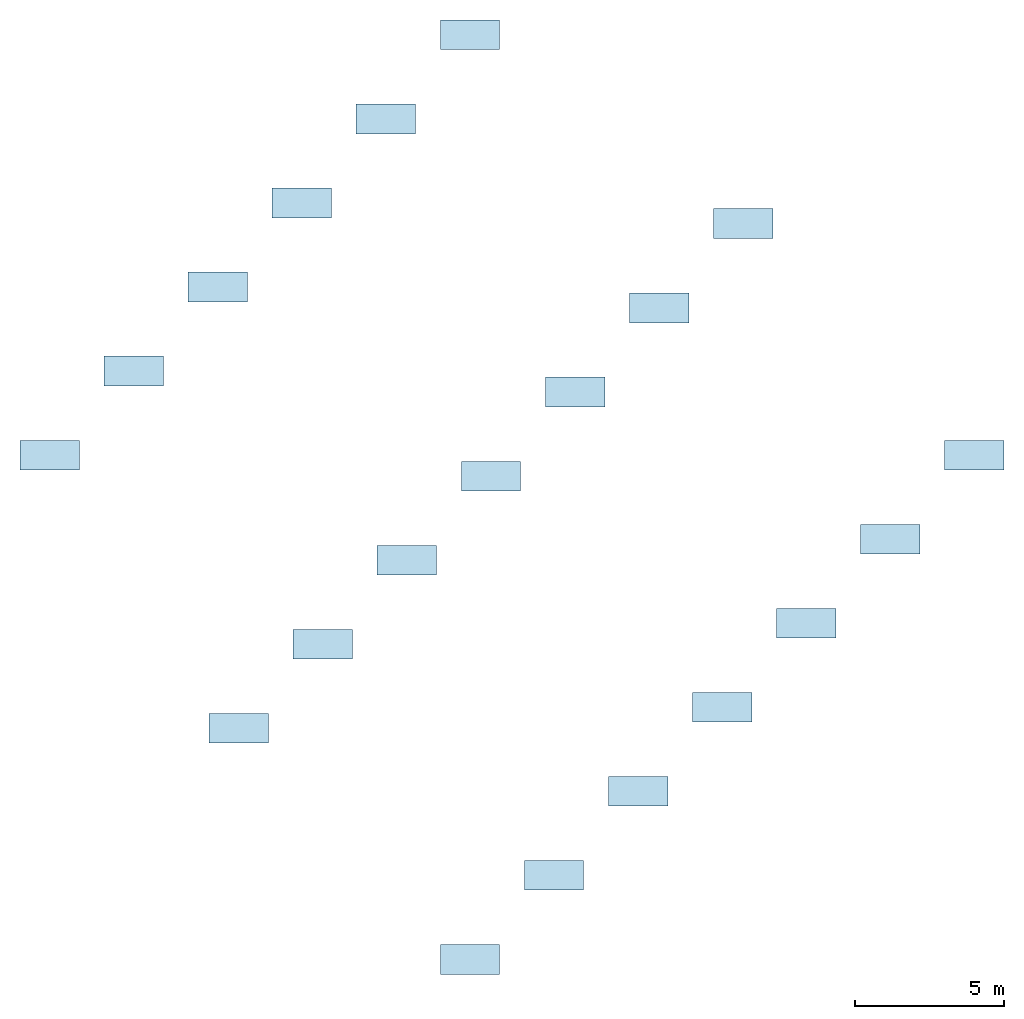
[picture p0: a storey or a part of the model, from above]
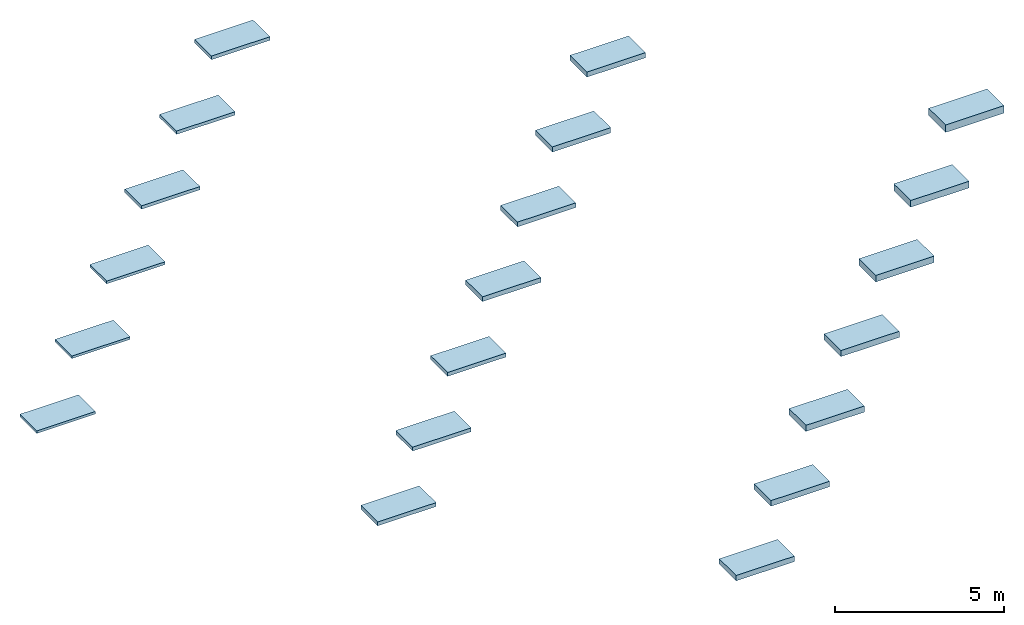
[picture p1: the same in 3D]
Properties of the parts of a building model (IFC2X3), part 1 of 3

# File
Description: ViewDefinition [CoordinationView_V2.0, QuantityTakeOffAddOnView]
Time: 2021-05-19T20:18:04
Written by: The EXPRESS Data Manager Version 5.02.0100.07 : 28 Aug 2013
Made in: 20190108_1515(x64) - Exporter 19.1.0.0 - Alternate UI 19.1.0.0
Comment: STEP Physical File produced by: The EXPRESS Data Manager Version 5.02.0100.07 : 28 Aug 2013 * Module: EDMstepFileFactory/EDMstandAlone * Creation date: Wed May 19 20:18:04 2021 * Host: lt-026 * Database: C:\Users\WF2BF~1.POE\AppData\Local\Temp\{3EFBC2A2-9184-4C69-A8A8-B9213D36A009}\ifc * Database version: 5507 * Database creation date: Wed May 19 20:18:03 2021 * Schema: IFC2X3 * Model: DataRepository.ifc * Model creation date: Wed May 19 20:18:03 2021 * Header model: DataRepository.ifc_HeaderModel * Header model creation date: Wed May 19 20:18:03 2021 * EDMuser: sdai-user * EDMgroup: sdai-group * License ID and type: 5605 : Permanent license. Expiry date: * EDMstepFileFactory options: 020000

# IfcSite, Default
RefLatitude: 42, 24, 53, 508911; RefLongitude: -71, -15, -29, -58837; RefElevation: 0 mm
Other - Category: Project Information

# IfcBuilding
Pset_BuildingCommon - NumberOfStoreys: 2
Pset_ProductRequirements - Category: Project Information; sets with these values: 2

# IfcBuildingStorey: Level:NL_00_niveau (2)
Pset_ProductRequirements - Category: Levels
Dimensions - Computation Height: 0 mm
Identity Data - Structural: no; Building Story: yes
Other - Category: Levels; Family: Level: NL_00_niveau; Family and Type: Level: NL_00_niveau; Type: Level: NL_00_niveau; Type Id: Level: NL_00_niveau
Constraints(Type) - Elevation Base: Project Base Point
Graphics(Type) - Color: 16711680; Line Pattern: NL_00_niveau; Line Weight: 1; Symbol: NLRS_00_LAB_niveau bovenkant_gen_cadix: 1.8mm; Symbol at End 1 Default: no; Symbol at End 2 Default: yes
Identity Data(Type) - Type Name: NL_00_niveau
Other(Type) - Category: Levels; Family Name: Level
Name | LongName = Pset_AirSideSystemInformation, Name = Pset_ProductRequirements, Name = Identity Data, Name | Elevation (mm) = Constraints, Elevation (mm)
Begane grond | Begane grond | 0
Lengte | Lengte | 2500

# IfcRoof: Basic Roof:NLRS_27_RO_Naturoll 035_100x580x7400mm, Basic Roof:NLRS_27_RO_Naturoll 035_100x580x7400mm:35001
In: Lengte
Classification: 27 Daken (Uniformat)
Pset_ElementShading - Roughness: 304.8 mm
Pset_ManufacturerTypeInformation - Manufacturer: Knauf Insulation B.V.
Pset_ProductRequirements - Category: Roofs
Pset_QuantityTakeOff - Reference: NLRS_27_RO_Naturoll 035_100x580x7400mm
Pset_RoofCommon - IsExternal: yes; Reference: NLRS_27_RO_Naturoll 035_100x580x7400mm; ProjectedArea: 2 m2; TotalArea: 2 m2
Constraints - Related to Mass: no; Room Bounding: yes; Base Level: Level: Lengte; Base Offset From Level: 0 mm; Cutoff Offset: 0 mm
Construction - Fascia Depth: 0 mm; Rafter Cut: Plumb Cut; Maximum Ridge Height: 2600 mm
Dimensions - Area: 2 m2; Thickness: 100 mm; Volume: 0.2 m3
Other - Category: Roofs; Family: Basic Roof: NLRS_27_RO_Naturoll 035_100x580x7400mm; Family and Type: Basic Roof: NLRS_27_RO_Naturoll 035_100x580x7400mm; Type: Basic Roof: NLRS_27_RO_Naturoll 035_100x580x7400mm; Type Id: Basic Roof: NLRS_27_RO_Naturoll 035_100x580x7400mm
Phasing - Phase Created: New Construction
Analytical Properties(Type) - Roughness: 1; Thermal mass: 0; Absorptance: 0.1; Heat Transfer Coefficient (U): 0.35; Thermal Resistance (R): 2.85714
Construction(Type) - Default Thickness: 100 mm
Graphics(Type) - Coarse Scale Fill Color: 0
Identity Data(Type) - Type Image: Raster image: Naturoll 035 .jpg (2); Assembly Code: 27; Assembly Description: Daken; Description: Naturoll 035 - 100mm; Manufacturer: Knauf Insulation B.V.; Model: Naturoll 035 is een onbeklede glaswoldeken met ECOSE® Technology; Type Name: NLRS_27_RO_Naturoll 035_100x580x7400mm; URL: www.knaufinsulation.nl
Other(Type) - Category: Roofs; Family Name: Basic Roof

# IfcRoof: Basic Roof:NLRS_27_RO_Naturoll 035_120x380x6200mm, Basic Roof:NLRS_27_RO_Naturoll 035_120x380x6200mm:35023
In: Lengte
Classification: 27 Daken (Uniformat)
Pset_ElementShading - Roughness: 304.8 mm
Pset_ManufacturerTypeInformation - Manufacturer: Knauf Insulation B.V.
Pset_ProductRequirements - Category: Roofs
Pset_QuantityTakeOff - Reference: NLRS_27_RO_Naturoll 035_120x380x6200mm
Pset_RoofCommon - IsExternal: yes; Reference: NLRS_27_RO_Naturoll 035_120x380x6200mm; ProjectedArea: 2 m2; TotalArea: 2 m2
Constraints - Related to Mass: no; Room Bounding: yes; Base Level: Level: Lengte; Base Offset From Level: 0 mm; Cutoff Offset: 0 mm
Construction - Fascia Depth: 0 mm; Rafter Cut: Plumb Cut; Maximum Ridge Height: 2620 mm
Dimensions - Area: 2 m2; Thickness: 120 mm; Volume: 0.24 m3
Other - Category: Roofs; Family: Basic Roof: NLRS_27_RO_Naturoll 035_120x380x6200mm; Family and Type: Basic Roof: NLRS_27_RO_Naturoll 035_120x380x6200mm; Type: Basic Roof: NLRS_27_RO_Naturoll 035_120x380x6200mm; Type Id: Basic Roof: NLRS_27_RO_Naturoll 035_120x380x6200mm
Phasing - Phase Created: New Construction
Analytical Properties(Type) - Roughness: 1; Thermal mass: 0; Absorptance: 0.1; Heat Transfer Coefficient (U): 0.291667; Thermal Resistance (R): 3.42857
Construction(Type) - Default Thickness: 120 mm
Graphics(Type) - Coarse Scale Fill Color: 0
Identity Data(Type) - Type Image: Raster image: Naturoll 035 .jpg (2); Assembly Code: 27; Assembly Description: Daken; Description: Naturoll 035 - 120mm; Manufacturer: Knauf Insulation B.V.; Model: Naturoll 035 is een onbeklede glaswoldeken met ECOSE® Technology; Type Name: NLRS_27_RO_Naturoll 035_120x380x6200mm; URL: www.knaufinsulation.nl
Other(Type) - Category: Roofs; Family Name: Basic Roof

# IfcRoof: Basic Roof:NLRS_27_RO_Naturoll 035_120x580x6200mm, Basic Roof:NLRS_27_RO_Naturoll 035_120x580x6200mm:35045
In: Lengte
Classification: 27 Daken (Uniformat)
Pset_ElementShading - Roughness: 304.8 mm
Pset_ManufacturerTypeInformation - Manufacturer: Knauf Insulation B.V.
Pset_ProductRequirements - Category: Roofs
Pset_QuantityTakeOff - Reference: NLRS_27_RO_Naturoll 035_120x580x6200mm
Pset_RoofCommon - IsExternal: yes; Reference: NLRS_27_RO_Naturoll 035_120x580x6200mm; ProjectedArea: 2 m2; TotalArea: 2 m2
Constraints - Related to Mass: no; Room Bounding: yes; Base Level: Level: Lengte; Base Offset From Level: 0 mm; Cutoff Offset: 0 mm
Construction - Fascia Depth: 0 mm; Rafter Cut: Plumb Cut; Maximum Ridge Height: 2620 mm
Dimensions - Area: 2 m2; Thickness: 120 mm; Volume: 0.24 m3
Other - Category: Roofs; Family: Basic Roof: NLRS_27_RO_Naturoll 035_120x580x6200mm; Family and Type: Basic Roof: NLRS_27_RO_Naturoll 035_120x580x6200mm; Type: Basic Roof: NLRS_27_RO_Naturoll 035_120x580x6200mm; Type Id: Basic Roof: NLRS_27_RO_Naturoll 035_120x580x6200mm
Phasing - Phase Created: New Construction
Analytical Properties(Type) - Roughness: 1; Thermal mass: 0; Absorptance: 0.1; Heat Transfer Coefficient (U): 0.291667; Thermal Resistance (R): 3.42857
Construction(Type) - Default Thickness: 120 mm
Graphics(Type) - Coarse Scale Fill Color: 0
Identity Data(Type) - Type Image: Raster image: Naturoll 035 .jpg (2); Assembly Code: 27; Assembly Description: Daken; Description: Naturoll 035 - 120mm; Manufacturer: Knauf Insulation B.V.; Model: Naturoll 035 is een onbeklede glaswoldeken met ECOSE® Technology; Type Name: NLRS_27_RO_Naturoll 035_120x580x6200mm; URL: www.knaufinsulation.nl
Other(Type) - Category: Roofs; Family Name: Basic Roof

# IfcRoof: Basic Roof:NLRS_27_RO_Naturoll 035_130x590x5500mm, Basic Roof:NLRS_27_RO_Naturoll 035_130x590x5500mm:35067
In: Lengte
Classification: 27 Daken (Uniformat)
Pset_ElementShading - Roughness: 304.8 mm
Pset_ManufacturerTypeInformation - Manufacturer: Knauf Insulation B.V.
Pset_ProductRequirements - Category: Roofs
Pset_QuantityTakeOff - Reference: NLRS_27_RO_Naturoll 035_130x590x5500mm
Pset_RoofCommon - IsExternal: yes; Reference: NLRS_27_RO_Naturoll 035_130x590x5500mm; ProjectedArea: 2 m2; TotalArea: 2 m2
Constraints - Related to Mass: no; Room Bounding: yes; Base Level: Level: Lengte; Base Offset From Level: 0 mm; Cutoff Offset: 0 mm
Construction - Fascia Depth: 0 mm; Rafter Cut: Plumb Cut; Maximum Ridge Height: 2630 mm
Dimensions - Area: 2 m2; Thickness: 130 mm; Volume: 0.26 m3
Other - Category: Roofs; Family: Basic Roof: NLRS_27_RO_Naturoll 035_130x590x5500mm; Family and Type: Basic Roof: NLRS_27_RO_Naturoll 035_130x590x5500mm; Type: Basic Roof: NLRS_27_RO_Naturoll 035_130x590x5500mm; Type Id: Basic Roof: NLRS_27_RO_Naturoll 035_130x590x5500mm
Phasing - Phase Created: New Construction
Analytical Properties(Type) - Roughness: 1; Thermal mass: 0; Absorptance: 0.1; Heat Transfer Coefficient (U): 0.269231; Thermal Resistance (R): 3.71429
Construction(Type) - Default Thickness: 130 mm
Graphics(Type) - Coarse Scale Fill Color: 0
Identity Data(Type) - Type Image: Raster image: Naturoll 035 .jpg (2); Assembly Code: 27; Assembly Description: Daken; Description: Naturoll 035 - 130mm; Manufacturer: Knauf Insulation B.V.; Model: Naturoll 035 is een onbeklede glaswoldeken met ECOSE® Technology; Type Name: NLRS_27_RO_Naturoll 035_130x590x5500mm; URL: www.knaufinsulation.nl
Other(Type) - Category: Roofs; Family Name: Basic Roof

# IfcRoof: Basic Roof:NLRS_27_RO_Naturoll 035_140x380x5300mm, Basic Roof:NLRS_27_RO_Naturoll 035_140x380x5300mm:35117
In: Lengte
Classification: 27 Daken (Uniformat)
Pset_ElementShading - Roughness: 304.8 mm
Pset_ManufacturerTypeInformation - Manufacturer: Knauf Insulation B.V.
Pset_ProductRequirements - Category: Roofs
Pset_QuantityTakeOff - Reference: NLRS_27_RO_Naturoll 035_140x380x5300mm
Pset_RoofCommon - IsExternal: yes; Reference: NLRS_27_RO_Naturoll 035_140x380x5300mm; ProjectedArea: 2 m2; TotalArea: 2 m2
Constraints - Related to Mass: no; Room Bounding: yes; Base Level: Level: Lengte; Base Offset From Level: 0 mm; Cutoff Offset: 0 mm
Construction - Fascia Depth: 0 mm; Rafter Cut: Plumb Cut; Maximum Ridge Height: 2640 mm
Dimensions - Area: 2 m2; Thickness: 140 mm; Volume: 0.28 m3
Other - Category: Roofs; Family: Basic Roof: NLRS_27_RO_Naturoll 035_140x380x5300mm; Family and Type: Basic Roof: NLRS_27_RO_Naturoll 035_140x380x5300mm; Type: Basic Roof: NLRS_27_RO_Naturoll 035_140x380x5300mm; Type Id: Basic Roof: NLRS_27_RO_Naturoll 035_140x380x5300mm
Phasing - Phase Created: New Construction
Analytical Properties(Type) - Roughness: 1; Thermal mass: 0; Thermal Resistance (R): 4; Absorptance: 0.1; Heat Transfer Coefficient (U): 0.25
Construction(Type) - Default Thickness: 140 mm
Graphics(Type) - Coarse Scale Fill Color: 0
Identity Data(Type) - Type Image: Raster image: Naturoll 035 .jpg (2); Assembly Code: 27; Assembly Description: Daken; Description: Naturoll 035 - 140mm; Manufacturer: Knauf Insulation B.V.; Model: Naturoll 035 is een onbeklede glaswoldeken met ECOSE® Technology; Type Name: NLRS_27_RO_Naturoll 035_140x380x5300mm; URL: www.knaufinsulation.nl
Other(Type) - Category: Roofs; Family Name: Basic Roof

# IfcRoof: Basic Roof:NLRS_27_RO_Naturoll 035_140x580x5300mm, Basic Roof:NLRS_27_RO_Naturoll 035_140x580x5300mm:35137
In: Lengte
Classification: 27 Daken (Uniformat)
Pset_ElementShading - Roughness: 304.8 mm
Pset_ManufacturerTypeInformation - Manufacturer: Knauf Insulation B.V.
Pset_ProductRequirements - Category: Roofs
Pset_QuantityTakeOff - Reference: NLRS_27_RO_Naturoll 035_140x580x5300mm
Pset_RoofCommon - IsExternal: yes; Reference: NLRS_27_RO_Naturoll 035_140x580x5300mm; ProjectedArea: 2 m2; TotalArea: 2 m2
Constraints - Related to Mass: no; Room Bounding: yes; Base Level: Level: Lengte; Base Offset From Level: 0 mm; Cutoff Offset: 0 mm
Construction - Fascia Depth: 0 mm; Rafter Cut: Plumb Cut; Maximum Ridge Height: 2640 mm
Dimensions - Area: 2 m2; Thickness: 140 mm; Volume: 0.28 m3
Other - Category: Roofs; Family: Basic Roof: NLRS_27_RO_Naturoll 035_140x580x5300mm; Family and Type: Basic Roof: NLRS_27_RO_Naturoll 035_140x580x5300mm; Type: Basic Roof: NLRS_27_RO_Naturoll 035_140x580x5300mm; Type Id: Basic Roof: NLRS_27_RO_Naturoll 035_140x580x5300mm
Phasing - Phase Created: New Construction
Analytical Properties(Type) - Roughness: 1; Thermal mass: 0; Thermal Resistance (R): 4; Absorptance: 0.1; Heat Transfer Coefficient (U): 0.25
Construction(Type) - Default Thickness: 140 mm
Graphics(Type) - Coarse Scale Fill Color: 0
Identity Data(Type) - Type Image: Raster image: Naturoll 035 .jpg (2); Assembly Code: 27; Assembly Description: Daken; Description: Naturoll 035 - 140mm; Manufacturer: Knauf Insulation B.V.; Model: Naturoll 035 is een onbeklede glaswoldeken met ECOSE® Technology; Type Name: NLRS_27_RO_Naturoll 035_140x580x5300mm; URL: www.knaufinsulation.nl
Other(Type) - Category: Roofs; Family Name: Basic Roof

# IfcRoof: Basic Roof:NLRS_27_RO_Naturoll 035_140x600x5300mm, Basic Roof:NLRS_27_RO_Naturoll 035_140x600x5300mm:35157
In: Lengte
Classification: 27 Daken (Uniformat)
Pset_ElementShading - Roughness: 304.8 mm
Pset_ManufacturerTypeInformation - Manufacturer: Knauf Insulation B.V.
Pset_ProductRequirements - Category: Roofs
Pset_QuantityTakeOff - Reference: NLRS_27_RO_Naturoll 035_140x600x5300mm
Pset_RoofCommon - IsExternal: yes; Reference: NLRS_27_RO_Naturoll 035_140x600x5300mm; ProjectedArea: 2 m2; TotalArea: 2 m2
Constraints - Related to Mass: no; Room Bounding: yes; Base Level: Level: Lengte; Base Offset From Level: 0 mm; Cutoff Offset: 0 mm
Construction - Fascia Depth: 0 mm; Rafter Cut: Plumb Cut; Maximum Ridge Height: 2640 mm
Dimensions - Area: 2 m2; Thickness: 140 mm; Volume: 0.28 m3
Other - Category: Roofs; Family: Basic Roof: NLRS_27_RO_Naturoll 035_140x600x5300mm; Family and Type: Basic Roof: NLRS_27_RO_Naturoll 035_140x600x5300mm; Type: Basic Roof: NLRS_27_RO_Naturoll 035_140x600x5300mm; Type Id: Basic Roof: NLRS_27_RO_Naturoll 035_140x600x5300mm
Phasing - Phase Created: New Construction
Analytical Properties(Type) - Roughness: 1; Thermal mass: 0; Thermal Resistance (R): 4; Absorptance: 0.1; Heat Transfer Coefficient (U): 0.25
Construction(Type) - Default Thickness: 140 mm
Graphics(Type) - Coarse Scale Fill Color: 0
Identity Data(Type) - Type Image: Raster image: Naturoll 035 .jpg (2); Assembly Code: 27; Assembly Description: Daken; Description: Naturoll 035 - 140mm; Manufacturer: Knauf Insulation B.V.; Model: Naturoll 035 is een onbeklede glaswoldeken met ECOSE® Technology; Type Name: NLRS_27_RO_Naturoll 035_140x600x5300mm; URL: www.knaufinsulation.nl
Other(Type) - Category: Roofs; Family Name: Basic Roof

# IfcRoof: Basic Roof:NLRS_27_RO_Naturoll 035_170x380x4350mm, Basic Roof:NLRS_27_RO_Naturoll 035_170x380x4350mm:35177
In: Lengte
Classification: 27 Daken (Uniformat)
Pset_ElementShading - Roughness: 304.8 mm
Pset_ManufacturerTypeInformation - Manufacturer: Knauf Insulation B.V.
Pset_ProductRequirements - Category: Roofs
Pset_QuantityTakeOff - Reference: NLRS_27_RO_Naturoll 035_170x380x4350mm
Pset_RoofCommon - IsExternal: yes; Reference: NLRS_27_RO_Naturoll 035_170x380x4350mm; ProjectedArea: 2 m2; TotalArea: 2 m2
Constraints - Related to Mass: no; Room Bounding: yes; Base Level: Level: Lengte; Base Offset From Level: 0 mm; Cutoff Offset: 0 mm
Construction - Fascia Depth: 0 mm; Rafter Cut: Plumb Cut; Maximum Ridge Height: 2670 mm
Dimensions - Area: 2 m2; Thickness: 170 mm; Volume: 0.34 m3
Other - Category: Roofs; Family: Basic Roof: NLRS_27_RO_Naturoll 035_170x380x4350mm; Family and Type: Basic Roof: NLRS_27_RO_Naturoll 035_170x380x4350mm; Type: Basic Roof: NLRS_27_RO_Naturoll 035_170x380x4350mm; Type Id: Basic Roof: NLRS_27_RO_Naturoll 035_170x380x4350mm
Phasing - Phase Created: New Construction
Analytical Properties(Type) - Roughness: 1; Thermal mass: 0; Absorptance: 0.1; Heat Transfer Coefficient (U): 0.205882; Thermal Resistance (R): 4.85714
Construction(Type) - Default Thickness: 170 mm
Graphics(Type) - Coarse Scale Fill Color: 0
Identity Data(Type) - Type Image: Raster image: Naturoll 035 .jpg (2); Assembly Code: 27; Assembly Description: Daken; Description: Naturoll 035 - 170mm; Manufacturer: Knauf Insulation B.V.; Model: Naturoll 035 is een onbeklede glaswoldeken met ECOSE® Technology; Type Name: NLRS_27_RO_Naturoll 035_170x380x4350mm; URL: www.knaufinsulation.nl
Other(Type) - Category: Roofs; Family Name: Basic Roof

# IfcRoof: Basic Roof:NLRS_27_RO_Naturoll 035_170x580x4350mm, Basic Roof:NLRS_27_RO_Naturoll 035_170x580x4350mm:35197
In: Lengte
Classification: 27 Daken (Uniformat)
Pset_ElementShading - Roughness: 304.8 mm
Pset_ManufacturerTypeInformation - Manufacturer: Knauf Insulation B.V.
Pset_ProductRequirements - Category: Roofs
Pset_QuantityTakeOff - Reference: NLRS_27_RO_Naturoll 035_170x580x4350mm
Pset_RoofCommon - IsExternal: yes; Reference: NLRS_27_RO_Naturoll 035_170x580x4350mm; ProjectedArea: 2 m2; TotalArea: 2 m2
Constraints - Related to Mass: no; Room Bounding: yes; Base Level: Level: Lengte; Base Offset From Level: 0 mm; Cutoff Offset: 0 mm
Construction - Fascia Depth: 0 mm; Rafter Cut: Plumb Cut; Maximum Ridge Height: 2670 mm
Dimensions - Area: 2 m2; Thickness: 170 mm; Volume: 0.34 m3
Other - Category: Roofs; Family: Basic Roof: NLRS_27_RO_Naturoll 035_170x580x4350mm; Family and Type: Basic Roof: NLRS_27_RO_Naturoll 035_170x580x4350mm; Type: Basic Roof: NLRS_27_RO_Naturoll 035_170x580x4350mm; Type Id: Basic Roof: NLRS_27_RO_Naturoll 035_170x580x4350mm
Phasing - Phase Created: New Construction
Analytical Properties(Type) - Roughness: 1; Thermal mass: 0; Absorptance: 0.1; Heat Transfer Coefficient (U): 0.205882; Thermal Resistance (R): 4.85714
Construction(Type) - Default Thickness: 170 mm
Graphics(Type) - Coarse Scale Fill Color: 0
Identity Data(Type) - Type Image: Raster image: Naturoll 035 .jpg (2); Assembly Code: 27; Assembly Description: Daken; Description: Naturoll 035 - 170mm; Manufacturer: Knauf Insulation B.V.; Model: Naturoll 035 is een onbeklede glaswoldeken met ECOSE® Technology; Type Name: NLRS_27_RO_Naturoll 035_170x580x4350mm; URL: www.knaufinsulation.nl
Other(Type) - Category: Roofs; Family Name: Basic Roof

# IfcRoof: Basic Roof:NLRS_27_RO_Naturoll 035_185x380x4000mm, Basic Roof:NLRS_27_RO_Naturoll 035_185x380x4000mm:35217
In: Lengte
Classification: 27 Daken (Uniformat)
Pset_ElementShading - Roughness: 304.8 mm
Pset_ManufacturerTypeInformation - Manufacturer: Knauf Insulation B.V.
Pset_ProductRequirements - Category: Roofs
Pset_QuantityTakeOff - Reference: NLRS_27_RO_Naturoll 035_185x380x4000mm
Pset_RoofCommon - IsExternal: yes; Reference: NLRS_27_RO_Naturoll 035_185x380x4000mm; ProjectedArea: 2 m2; TotalArea: 2 m2
Constraints - Related to Mass: no; Room Bounding: yes; Base Level: Level: Lengte; Base Offset From Level: 0 mm; Cutoff Offset: 0 mm
Construction - Fascia Depth: 0 mm; Rafter Cut: Plumb Cut; Maximum Ridge Height: 2685 mm
Dimensions - Area: 2 m2; Thickness: 185 mm; Volume: 0.37 m3
Other - Category: Roofs; Family: Basic Roof: NLRS_27_RO_Naturoll 035_185x380x4000mm; Family and Type: Basic Roof: NLRS_27_RO_Naturoll 035_185x380x4000mm; Type: Basic Roof: NLRS_27_RO_Naturoll 035_185x380x4000mm; Type Id: Basic Roof: NLRS_27_RO_Naturoll 035_185x380x4000mm
Phasing - Phase Created: New Construction
Analytical Properties(Type) - Roughness: 1; Thermal mass: 0; Absorptance: 0.1; Heat Transfer Coefficient (U): 0.189189; Thermal Resistance (R): 5.28571
Construction(Type) - Default Thickness: 185 mm
Graphics(Type) - Coarse Scale Fill Color: 0
Identity Data(Type) - Type Image: Raster image: Naturoll 035 .jpg (2); Assembly Code: 27; Assembly Description: Daken; Description: Naturoll 035 - 185mm; Manufacturer: Knauf Insulation B.V.; Model: Naturoll 035 is een onbeklede glaswoldeken met ECOSE® Technology; Type Name: NLRS_27_RO_Naturoll 035_185x380x4000mm; URL: www.knaufinsulation.nl
Other(Type) - Category: Roofs; Family Name: Basic Roof

# IfcRoof: Basic Roof:NLRS_27_RO_Naturoll 035_185x580x4000mm, Basic Roof:NLRS_27_RO_Naturoll 035_185x580x4000mm:37505
In: Lengte
Classification: 27 Daken (Uniformat)
Pset_ElementShading - Roughness: 304.8 mm
Pset_ManufacturerTypeInformation - Manufacturer: Knauf Insulation B.V.
Pset_ProductRequirements - Category: Roofs
Pset_QuantityTakeOff - Reference: NLRS_27_RO_Naturoll 035_185x580x4000mm
Pset_RoofCommon - IsExternal: yes; Reference: NLRS_27_RO_Naturoll 035_185x580x4000mm; ProjectedArea: 2 m2; TotalArea: 2 m2
Constraints - Related to Mass: no; Room Bounding: yes; Base Level: Level: Lengte; Base Offset From Level: 0 mm; Cutoff Offset: 0 mm
Construction - Fascia Depth: 0 mm; Rafter Cut: Plumb Cut; Maximum Ridge Height: 2685 mm
Dimensions - Area: 2 m2; Thickness: 185 mm; Volume: 0.37 m3
Other - Category: Roofs; Family: Basic Roof: NLRS_27_RO_Naturoll 035_185x580x4000mm; Family and Type: Basic Roof: NLRS_27_RO_Naturoll 035_185x580x4000mm; Type: Basic Roof: NLRS_27_RO_Naturoll 035_185x580x4000mm; Type Id: Basic Roof: NLRS_27_RO_Naturoll 035_185x580x4000mm
Phasing - Phase Created: New Construction
Analytical Properties(Type) - Roughness: 1; Thermal mass: 0; Absorptance: 0.1; Heat Transfer Coefficient (U): 0.189189; Thermal Resistance (R): 5.28571
Construction(Type) - Default Thickness: 185 mm
Graphics(Type) - Coarse Scale Fill Color: 0
Identity Data(Type) - Type Image: Raster image: Naturoll 035 .jpg (2); Assembly Code: 27; Assembly Description: Daken; Description: Naturoll 035 - 185mm; Manufacturer: Knauf Insulation B.V.; Model: Naturoll 035 is een onbeklede glaswoldeken met ECOSE® Technology; Type Name: NLRS_27_RO_Naturoll 035_185x580x4000mm; URL: www.knaufinsulation.nl
Other(Type) - Category: Roofs; Family Name: Basic Roof

# IfcRoof: Basic Roof:NLRS_27_RO_Naturoll 035_195x580x3800mm, Basic Roof:NLRS_27_RO_Naturoll 035_195x580x3800mm:35644
In: Lengte
Classification: 27 Daken (Uniformat)
Pset_ElementShading - Roughness: 304.8 mm
Pset_ManufacturerTypeInformation - Manufacturer: Knauf Insulation B.V.
Pset_ProductRequirements - Category: Roofs
Pset_QuantityTakeOff - Reference: NLRS_27_RO_Naturoll 035_195x580x3800mm
Pset_RoofCommon - IsExternal: yes; Reference: NLRS_27_RO_Naturoll 035_195x580x3800mm; ProjectedArea: 2 m2; TotalArea: 2 m2
Constraints - Related to Mass: no; Room Bounding: yes; Base Level: Level: Lengte; Base Offset From Level: 0 mm; Cutoff Offset: 0 mm
Construction - Fascia Depth: 0 mm; Rafter Cut: Plumb Cut; Maximum Ridge Height: 2695 mm
Dimensions - Area: 2 m2; Thickness: 195 mm; Volume: 0.39 m3
Other - Category: Roofs; Family: Basic Roof: NLRS_27_RO_Naturoll 035_195x580x3800mm; Family and Type: Basic Roof: NLRS_27_RO_Naturoll 035_195x580x3800mm; Type: Basic Roof: NLRS_27_RO_Naturoll 035_195x580x3800mm; Type Id: Basic Roof: NLRS_27_RO_Naturoll 035_195x580x3800mm
Phasing - Phase Created: New Construction
Analytical Properties(Type) - Roughness: 1; Thermal mass: 0; Absorptance: 0.1; Heat Transfer Coefficient (U): 0.179487; Thermal Resistance (R): 5.57143
Construction(Type) - Default Thickness: 195 mm
Graphics(Type) - Coarse Scale Fill Color: 0
Identity Data(Type) - Type Image: Raster image: Naturoll 035 .jpg (2); Assembly Code: 27; Assembly Description: Daken; Description: Naturoll 035 - 195mm; Manufacturer: Knauf Insulation B.V.; Model: Naturoll 035 is een onbeklede glaswoldeken met ECOSE® Technology; Type Name: NLRS_27_RO_Naturoll 035_195x580x3800mm; URL: www.knaufinsulation.nl
Other(Type) - Category: Roofs; Family Name: Basic Roof

# IfcRoof: Basic Roof:NLRS_27_RO_Naturoll 035_200x580x3700mm, Basic Roof:NLRS_27_RO_Naturoll 035_200x580x3700mm:35405
In: Lengte
Classification: 27 Daken (Uniformat)
Pset_ElementShading - Roughness: 304.8 mm
Pset_ManufacturerTypeInformation - Manufacturer: Knauf Insulation B.V.
Pset_ProductRequirements - Category: Roofs
Pset_QuantityTakeOff - Reference: NLRS_27_RO_Naturoll 035_200x580x3700mm
Pset_RoofCommon - IsExternal: yes; Reference: NLRS_27_RO_Naturoll 035_200x580x3700mm; ProjectedArea: 2 m2; TotalArea: 2 m2
Constraints - Related to Mass: no; Room Bounding: yes; Base Level: Level: Lengte; Base Offset From Level: 0 mm; Cutoff Offset: 0 mm
Construction - Fascia Depth: 0 mm; Rafter Cut: Plumb Cut; Maximum Ridge Height: 2700 mm
Dimensions - Area: 2 m2; Thickness: 200 mm; Volume: 0.4 m3
Other - Category: Roofs; Family: Basic Roof: NLRS_27_RO_Naturoll 035_200x580x3700mm; Family and Type: Basic Roof: NLRS_27_RO_Naturoll 035_200x580x3700mm; Type: Basic Roof: NLRS_27_RO_Naturoll 035_200x580x3700mm; Type Id: Basic Roof: NLRS_27_RO_Naturoll 035_200x580x3700mm
Phasing - Phase Created: New Construction
Analytical Properties(Type) - Roughness: 1; Thermal mass: 0; Absorptance: 0.1; Heat Transfer Coefficient (U): 0.175; Thermal Resistance (R): 5.71429
Construction(Type) - Default Thickness: 200 mm
Graphics(Type) - Coarse Scale Fill Color: 0
Identity Data(Type) - Type Image: Raster image: Naturoll 035 .jpg (2); Assembly Code: 27; Assembly Description: Daken; Description: Naturoll 035 - 200mm; Manufacturer: Knauf Insulation B.V.; Model: Naturoll 035 is een onbeklede glaswoldeken met ECOSE® Technology; Type Name: NLRS_27_RO_Naturoll 035_200x580x3700mm; URL: www.knaufinsulation.nl
Other(Type) - Category: Roofs; Family Name: Basic Roof

# IfcRoof: Basic Roof:NLRS_27_RO_Naturoll 035_220x380x3400mm, Basic Roof:NLRS_27_RO_Naturoll 035_220x380x3400mm:35424
In: Lengte
Classification: 27 Daken (Uniformat)
Pset_ElementShading - Roughness: 304.8 mm
Pset_ManufacturerTypeInformation - Manufacturer: Knauf Insulation B.V.
Pset_ProductRequirements - Category: Roofs
Pset_QuantityTakeOff - Reference: NLRS_27_RO_Naturoll 035_220x380x3400mm
Pset_RoofCommon - IsExternal: yes; Reference: NLRS_27_RO_Naturoll 035_220x380x3400mm; ProjectedArea: 2 m2; TotalArea: 2 m2
Constraints - Related to Mass: no; Room Bounding: yes; Base Level: Level: Lengte; Base Offset From Level: 0 mm; Cutoff Offset: 0 mm
Construction - Fascia Depth: 0 mm; Rafter Cut: Plumb Cut; Maximum Ridge Height: 2720 mm
Dimensions - Area: 2 m2; Thickness: 220 mm; Volume: 0.44 m3
Other - Category: Roofs; Family: Basic Roof: NLRS_27_RO_Naturoll 035_220x380x3400mm; Family and Type: Basic Roof: NLRS_27_RO_Naturoll 035_220x380x3400mm; Type: Basic Roof: NLRS_27_RO_Naturoll 035_220x380x3400mm; Type Id: Basic Roof: NLRS_27_RO_Naturoll 035_220x380x3400mm
Phasing - Phase Created: New Construction
Analytical Properties(Type) - Roughness: 1; Thermal mass: 0; Absorptance: 0.1; Heat Transfer Coefficient (U): 0.159091; Thermal Resistance (R): 6.28571
Construction(Type) - Default Thickness: 220 mm
Graphics(Type) - Coarse Scale Fill Color: 0
Identity Data(Type) - Type Image: Raster image: Naturoll 035 .jpg (2); Assembly Code: 27; Assembly Description: Daken; Description: Naturoll 035 - 220mm; Manufacturer: Knauf Insulation B.V.; Model: Naturoll 035 is een onbeklede glaswoldeken met ECOSE® Technology; Type Name: NLRS_27_RO_Naturoll 035_220x380x3400mm; URL: www.knaufinsulation.nl
Other(Type) - Category: Roofs; Family Name: Basic Roof

# IfcRoof: Basic Roof:NLRS_27_RO_Naturoll 035_220x580x3100mm, Basic Roof:NLRS_27_RO_Naturoll 035_220x580x3100mm:35443
In: Lengte
Classification: 27 Daken (Uniformat)
Pset_ElementShading - Roughness: 304.8 mm
Pset_ManufacturerTypeInformation - Manufacturer: Knauf Insulation B.V.
Pset_ProductRequirements - Category: Roofs
Pset_QuantityTakeOff - Reference: NLRS_27_RO_Naturoll 035_220x580x3100mm
Pset_RoofCommon - IsExternal: yes; Reference: NLRS_27_RO_Naturoll 035_220x580x3100mm; ProjectedArea: 2 m2; TotalArea: 2 m2
Constraints - Related to Mass: no; Room Bounding: yes; Base Level: Level: Lengte; Base Offset From Level: 0 mm; Cutoff Offset: 0 mm
Construction - Fascia Depth: 0 mm; Rafter Cut: Plumb Cut; Maximum Ridge Height: 2720 mm
Dimensions - Area: 2 m2; Thickness: 220 mm; Volume: 0.44 m3
Other - Category: Roofs; Family: Basic Roof: NLRS_27_RO_Naturoll 035_220x580x3100mm; Family and Type: Basic Roof: NLRS_27_RO_Naturoll 035_220x580x3100mm; Type: Basic Roof: NLRS_27_RO_Naturoll 035_220x580x3100mm; Type Id: Basic Roof: NLRS_27_RO_Naturoll 035_220x580x3100mm
Phasing - Phase Created: New Construction
Analytical Properties(Type) - Roughness: 1; Thermal mass: 0; Absorptance: 0.1; Heat Transfer Coefficient (U): 0.159091; Thermal Resistance (R): 6.28571
Construction(Type) - Default Thickness: 220 mm
Graphics(Type) - Coarse Scale Fill Color: 0
Identity Data(Type) - Type Image: Raster image: Naturoll 035 .jpg (2); Assembly Code: 27; Assembly Description: Daken; Description: Naturoll 035 - 220mm; Manufacturer: Knauf Insulation B.V.; Model: Naturoll 035 is een onbeklede glaswoldeken met ECOSE® Technology; Type Name: NLRS_27_RO_Naturoll 035_220x580x3100mm; URL: www.knaufinsulation.nl
Other(Type) - Category: Roofs; Family Name: Basic Roof

# IfcRoof: Basic Roof:NLRS_27_RO_Naturoll 035_235x580x3100mm, Basic Roof:NLRS_27_RO_Naturoll 035_235x580x3100mm:35462
In: Lengte
Classification: 27 Daken (Uniformat)
Pset_ElementShading - Roughness: 304.8 mm
Pset_ManufacturerTypeInformation - Manufacturer: Knauf Insulation B.V.
Pset_ProductRequirements - Category: Roofs
Pset_QuantityTakeOff - Reference: NLRS_27_RO_Naturoll 035_235x580x3100mm
Pset_RoofCommon - IsExternal: yes; Reference: NLRS_27_RO_Naturoll 035_235x580x3100mm; ProjectedArea: 2 m2; TotalArea: 2 m2
Constraints - Related to Mass: no; Room Bounding: yes; Base Level: Level: Lengte; Base Offset From Level: 0 mm; Cutoff Offset: 0 mm
Construction - Fascia Depth: 0 mm; Rafter Cut: Plumb Cut; Maximum Ridge Height: 2735 mm
Dimensions - Area: 2 m2; Thickness: 235 mm; Volume: 0.47 m3
Other - Category: Roofs; Family: Basic Roof: NLRS_27_RO_Naturoll 035_235x580x3100mm; Family and Type: Basic Roof: NLRS_27_RO_Naturoll 035_235x580x3100mm; Type: Basic Roof: NLRS_27_RO_Naturoll 035_235x580x3100mm; Type Id: Basic Roof: NLRS_27_RO_Naturoll 035_235x580x3100mm
Phasing - Phase Created: New Construction
Analytical Properties(Type) - Roughness: 1; Thermal mass: 0; Absorptance: 0.1; Heat Transfer Coefficient (U): 0.148936; Thermal Resistance (R): 6.71429
Construction(Type) - Default Thickness: 235 mm
Graphics(Type) - Coarse Scale Fill Color: 0
Identity Data(Type) - Type Image: Raster image: Naturoll 035 .jpg (2); Assembly Code: 27; Assembly Description: Daken; Description: Naturoll 035 - 235mm; Manufacturer: Knauf Insulation B.V.; Model: Naturoll 035 is een onbeklede glaswoldeken met ECOSE® Technology; Type Name: NLRS_27_RO_Naturoll 035_235x580x3100mm; URL: www.knaufinsulation.nl
Other(Type) - Category: Roofs; Family Name: Basic Roof

# IfcRoof: Basic Roof:NLRS_27_RO_Naturoll 035_240x580x3100mm, Basic Roof:NLRS_27_RO_Naturoll 035_240x580x3100mm:35481
In: Lengte
Classification: 27 Daken (Uniformat)
Pset_ElementShading - Roughness: 304.8 mm
Pset_ManufacturerTypeInformation - Manufacturer: Knauf Insulation B.V.
Pset_ProductRequirements - Category: Roofs
Pset_QuantityTakeOff - Reference: NLRS_27_RO_Naturoll 035_240x580x3100mm
Pset_RoofCommon - IsExternal: yes; Reference: NLRS_27_RO_Naturoll 035_240x580x3100mm; ProjectedArea: 2 m2; TotalArea: 2 m2
Constraints - Related to Mass: no; Room Bounding: yes; Base Level: Level: Lengte; Base Offset From Level: 0 mm; Cutoff Offset: 0 mm
Construction - Fascia Depth: 0 mm; Rafter Cut: Plumb Cut; Maximum Ridge Height: 2740 mm
Dimensions - Area: 2 m2; Thickness: 240 mm; Volume: 0.48 m3
Other - Category: Roofs; Family: Basic Roof: NLRS_27_RO_Naturoll 035_240x580x3100mm; Family and Type: Basic Roof: NLRS_27_RO_Naturoll 035_240x580x3100mm; Type: Basic Roof: NLRS_27_RO_Naturoll 035_240x580x3100mm; Type Id: Basic Roof: NLRS_27_RO_Naturoll 035_240x580x3100mm
Phasing - Phase Created: New Construction
Analytical Properties(Type) - Roughness: 1; Thermal mass: 0; Absorptance: 0.1; Heat Transfer Coefficient (U): 0.145833; Thermal Resistance (R): 6.85714
Construction(Type) - Default Thickness: 240 mm
Graphics(Type) - Coarse Scale Fill Color: 0
Identity Data(Type) - Type Image: Raster image: Naturoll 035 .jpg (2); Assembly Code: 27; Assembly Description: Daken; Description: Naturoll 035 - 240mm; Manufacturer: Knauf Insulation B.V.; Model: Naturoll 035 is een onbeklede glaswoldeken met ECOSE® Technology; Type Name: NLRS_27_RO_Naturoll 035_240x580x3100mm; URL: www.knaufinsulation.nl
Other(Type) - Category: Roofs; Family Name: Basic Roof

# IfcRoof: Basic Roof:NLRS_27_RO_Naturoll 035_270x590x2600mm, Basic Roof:NLRS_27_RO_Naturoll 035_270x590x2600mm:35500
In: Lengte
Classification: 27 Daken (Uniformat)
Pset_ElementShading - Roughness: 304.8 mm
Pset_ManufacturerTypeInformation - Manufacturer: Knauf Insulation B.V.
Pset_ProductRequirements - Category: Roofs
Pset_QuantityTakeOff - Reference: NLRS_27_RO_Naturoll 035_270x590x2600mm
Pset_RoofCommon - IsExternal: yes; Reference: NLRS_27_RO_Naturoll 035_270x590x2600mm; ProjectedArea: 2 m2; TotalArea: 2 m2
Constraints - Related to Mass: no; Room Bounding: yes; Base Level: Level: Lengte; Base Offset From Level: 0 mm; Cutoff Offset: 0 mm
Construction - Fascia Depth: 0 mm; Rafter Cut: Plumb Cut; Maximum Ridge Height: 2770 mm
Dimensions - Area: 2 m2; Thickness: 270 mm; Volume: 0.54 m3
Other - Category: Roofs; Family: Basic Roof: NLRS_27_RO_Naturoll 035_270x590x2600mm; Family and Type: Basic Roof: NLRS_27_RO_Naturoll 035_270x590x2600mm; Type: Basic Roof: NLRS_27_RO_Naturoll 035_270x590x2600mm; Type Id: Basic Roof: NLRS_27_RO_Naturoll 035_270x590x2600mm
Phasing - Phase Created: New Construction
Analytical Properties(Type) - Roughness: 1; Thermal mass: 0; Absorptance: 0.1; Heat Transfer Coefficient (U): 0.12963; Thermal Resistance (R): 7.71429
Construction(Type) - Default Thickness: 270 mm
Graphics(Type) - Coarse Scale Fill Color: 0
Identity Data(Type) - Type Image: Raster image: Naturoll 035 .jpg (2); Assembly Code: 27; Assembly Description: Daken; Description: Naturoll 035 - 270mm; Manufacturer: Knauf Insulation B.V.; Model: Naturoll 035 is een onbeklede glaswoldeken met ECOSE® Technology; Type Name: NLRS_27_RO_Naturoll 035_270x590x2600mm; URL: www.knaufinsulation.nl
Other(Type) - Category: Roofs; Family Name: Basic Roof

# IfcRoof: Basic Roof:NLRS_27_RO_Naturoll 035_90x380x7600mm, Basic Roof:NLRS_27_RO_Naturoll 035_90x380x7600mm:34727
In: Lengte
Classification: 27 Daken (Uniformat)
Pset_ElementShading - Roughness: 304.8 mm
Pset_ManufacturerTypeInformation - Manufacturer: Knauf Insulation B.V.
Pset_ProductRequirements - Category: Roofs
Pset_QuantityTakeOff - Reference: NLRS_27_RO_Naturoll 035_90x380x7600mm
Pset_RoofCommon - IsExternal: yes; Reference: NLRS_27_RO_Naturoll 035_90x380x7600mm; ProjectedArea: 2 m2; TotalArea: 2 m2
Constraints - Related to Mass: no; Room Bounding: yes; Base Level: Level: Lengte; Base Offset From Level: 0 mm; Cutoff Offset: 0 mm
Construction - Fascia Depth: 0 mm; Maximum Ridge Height: 2590 mm; Rafter Cut: Plumb Cut
Dimensions - Area: 2 m2; Thickness: 90 mm; Volume: 0.18 m3
Other - Category: Roofs; Family: Basic Roof: NLRS_27_RO_Naturoll 035_90x380x7600mm; Family and Type: Basic Roof: NLRS_27_RO_Naturoll 035_90x380x7600mm; Type: Basic Roof: NLRS_27_RO_Naturoll 035_90x380x7600mm; Type Id: Basic Roof: NLRS_27_RO_Naturoll 035_90x380x7600mm
Phasing - Phase Created: New Construction
Analytical Properties(Type) - Roughness: 1; Thermal mass: 0; Absorptance: 0.1; Heat Transfer Coefficient (U): 0.388889; Thermal Resistance (R): 2.57143
Construction(Type) - Default Thickness: 90 mm
Graphics(Type) - Coarse Scale Fill Color: 0
Identity Data(Type) - Type Image: Raster image: Naturoll 035 .jpg (2); Assembly Code: 27; Assembly Description: Daken; Description: Naturoll 035 - 90mm; Manufacturer: Knauf Insulation B.V.; Model: Naturoll 035 is een onbeklede glaswoldeken met ECOSE® Technology; Type Name: NLRS_27_RO_Naturoll 035_90x380x7600mm; URL: www.knaufinsulation.nl
Other(Type) - Category: Roofs; Family Name: Basic Roof

# IfcRoof: Basic Roof:NLRS_27_RO_Naturoll 035_90x580x7600mm, Basic Roof:NLRS_27_RO_Naturoll 035_90x580x7600mm:34921
In: Lengte
Classification: 27 Daken (Uniformat)
Pset_ElementShading - Roughness: 304.8 mm
Pset_ManufacturerTypeInformation - Manufacturer: Knauf Insulation B.V.
Pset_ProductRequirements - Category: Roofs
Pset_QuantityTakeOff - Reference: NLRS_27_RO_Naturoll 035_90x580x7600mm
Pset_RoofCommon - IsExternal: yes; Reference: NLRS_27_RO_Naturoll 035_90x580x7600mm; ProjectedArea: 2 m2; TotalArea: 2 m2
Constraints - Related to Mass: no; Room Bounding: yes; Base Level: Level: Lengte; Base Offset From Level: 0 mm; Cutoff Offset: 0 mm
Construction - Fascia Depth: 0 mm; Rafter Cut: Plumb Cut; Maximum Ridge Height: 2590 mm
Dimensions - Area: 2 m2; Thickness: 90 mm; Volume: 0.18 m3
Other - Category: Roofs; Family: Basic Roof: NLRS_27_RO_Naturoll 035_90x580x7600mm; Family and Type: Basic Roof: NLRS_27_RO_Naturoll 035_90x580x7600mm; Type: Basic Roof: NLRS_27_RO_Naturoll 035_90x580x7600mm; Type Id: Basic Roof: NLRS_27_RO_Naturoll 035_90x580x7600mm
Phasing - Phase Created: New Construction
Analytical Properties(Type) - Roughness: 1; Thermal mass: 0; Absorptance: 0.1; Heat Transfer Coefficient (U): 0.388889; Thermal Resistance (R): 2.57143
Construction(Type) - Default Thickness: 90 mm
Graphics(Type) - Coarse Scale Fill Color: 0
Identity Data(Type) - Type Image: Raster image: Naturoll 035 .jpg (2); Assembly Code: 27; Assembly Description: Daken; Description: Naturoll 035 - 90mm; Manufacturer: Knauf Insulation B.V.; Model: Naturoll 035 is een onbeklede glaswoldeken met ECOSE® Technology; Type Name: NLRS_27_RO_Naturoll 035_90x580x7600mm; URL: www.knaufinsulation.nl
Other(Type) - Category: Roofs; Family Name: Basic Roof

# IfcSlab: Basic Roof:NLRS_27_RO_Naturoll 035_100x580x7400mm, Basic Roof:NLRS_27_RO_Naturoll 035_100x580x7400mm:35001
In: Lengte
PredefinedType: ROOF; Classification: 27 Daken (Uniformat); Material: Knauf Insulation_Ecose® glaswol_naturoll 035 100 mm
Pset_ElementShading - Roughness: 304.8 mm
Pset_ManufacturerTypeInformation - Manufacturer: Knauf Insulation B.V.
Pset_ProductRequirements - Category: Roofs
Pset_QuantityTakeOff - Reference: NLRS_27_RO_Naturoll 035_100x580x7400mm
Pset_ReinforcementBarPitchOfSlab - Description: Naturoll 035 - 100mm; Reference: NLRS_27_RO_Naturoll 035_100x580x7400mm
Pset_SlabCommon - PitchAngle: 0 deg; IsExternal: yes; ThermalTransmittance: 0.35 kg/K/s3; Reference: NLRS_27_RO_Naturoll 035_100x580x7400mm
BaseQuantities - GrossArea: 0.185806 m2; NetArea: 4.6 m2; GrossVolume: 18.5806 m3; NetVolume: 0.2 m3; Perimeter: 6000 mm; Width: 100 mm

# IfcSlab: Basic Roof:NLRS_27_RO_Naturoll 035_120x380x6200mm, Basic Roof:NLRS_27_RO_Naturoll 035_120x380x6200mm:35023
In: Lengte
PredefinedType: ROOF; Classification: 27 Daken (Uniformat); Material: Knauf Insulation_Ecose® glaswol_naturoll 035 120 mm
Pset_ElementShading - Roughness: 304.8 mm
Pset_ManufacturerTypeInformation - Manufacturer: Knauf Insulation B.V.
Pset_ProductRequirements - Category: Roofs
Pset_QuantityTakeOff - Reference: NLRS_27_RO_Naturoll 035_120x380x6200mm
Pset_ReinforcementBarPitchOfSlab - Description: Naturoll 035 - 120mm; Reference: NLRS_27_RO_Naturoll 035_120x380x6200mm
Pset_SlabCommon - PitchAngle: 0 deg; IsExternal: yes; Reference: NLRS_27_RO_Naturoll 035_120x380x6200mm; ThermalTransmittance: 0.291667 kg/K/s3
BaseQuantities - GrossArea: 0.185806 m2; NetArea: 4.72 m2; GrossVolume: 22.2967 m3; NetVolume: 0.24 m3; Perimeter: 6000 mm; Width: 120 mm

# IfcSlab: Basic Roof:NLRS_27_RO_Naturoll 035_120x580x6200mm, Basic Roof:NLRS_27_RO_Naturoll 035_120x580x6200mm:35045
In: Lengte
PredefinedType: ROOF; Classification: 27 Daken (Uniformat); Material: Knauf Insulation_Ecose® glaswol_naturoll 035 120 mm
Pset_ElementShading - Roughness: 304.8 mm
Pset_ManufacturerTypeInformation - Manufacturer: Knauf Insulation B.V.
Pset_ProductRequirements - Category: Roofs
Pset_QuantityTakeOff - Reference: NLRS_27_RO_Naturoll 035_120x580x6200mm
Pset_ReinforcementBarPitchOfSlab - Description: Naturoll 035 - 120mm; Reference: NLRS_27_RO_Naturoll 035_120x580x6200mm
Pset_SlabCommon - PitchAngle: 0 deg; IsExternal: yes; Reference: NLRS_27_RO_Naturoll 035_120x580x6200mm; ThermalTransmittance: 0.291667 kg/K/s3
BaseQuantities - GrossArea: 0.185806 m2; NetArea: 4.72 m2; GrossVolume: 22.2967 m3; NetVolume: 0.24 m3; Perimeter: 6000 mm; Width: 120 mm

# IfcSlab: Basic Roof:NLRS_27_RO_Naturoll 035_130x590x5500mm, Basic Roof:NLRS_27_RO_Naturoll 035_130x590x5500mm:35067
In: Lengte
PredefinedType: ROOF; Classification: 27 Daken (Uniformat); Material: Knauf Insulation_Ecose® glaswol_naturoll 035 130 mm
Pset_ElementShading - Roughness: 304.8 mm
Pset_ManufacturerTypeInformation - Manufacturer: Knauf Insulation B.V.
Pset_ProductRequirements - Category: Roofs
Pset_QuantityTakeOff - Reference: NLRS_27_RO_Naturoll 035_130x590x5500mm
Pset_ReinforcementBarPitchOfSlab - Description: Naturoll 035 - 130mm; Reference: NLRS_27_RO_Naturoll 035_130x590x5500mm
Pset_SlabCommon - PitchAngle: 0 deg; IsExternal: yes; Reference: NLRS_27_RO_Naturoll 035_130x590x5500mm; ThermalTransmittance: 0.269231 kg/K/s3
BaseQuantities - GrossArea: 0.185806 m2; NetArea: 4.78 m2; GrossVolume: 24.1548 m3; NetVolume: 0.26 m3; Perimeter: 6000 mm; Width: 130 mm

# IfcSlab: Basic Roof:NLRS_27_RO_Naturoll 035_140x380x5300mm, Basic Roof:NLRS_27_RO_Naturoll 035_140x380x5300mm:35117
In: Lengte
PredefinedType: ROOF; Classification: 27 Daken (Uniformat); Material: Knauf Insulation_Ecose® glaswol_naturoll 035 140 mm
Pset_ElementShading - Roughness: 304.8 mm
Pset_ManufacturerTypeInformation - Manufacturer: Knauf Insulation B.V.
Pset_ProductRequirements - Category: Roofs
Pset_QuantityTakeOff - Reference: NLRS_27_RO_Naturoll 035_140x380x5300mm
Pset_ReinforcementBarPitchOfSlab - Description: Naturoll 035 - 140mm; Reference: NLRS_27_RO_Naturoll 035_140x380x5300mm
Pset_SlabCommon - PitchAngle: 0 deg; IsExternal: yes; ThermalTransmittance: 0.25 kg/K/s3; Reference: NLRS_27_RO_Naturoll 035_140x380x5300mm
BaseQuantities - GrossArea: 0.185806 m2; NetArea: 4.84 m2; GrossVolume: 26.0129 m3; NetVolume: 0.28 m3; Perimeter: 6000 mm; Width: 140 mm

# IfcSlab: Basic Roof:NLRS_27_RO_Naturoll 035_140x580x5300mm, Basic Roof:NLRS_27_RO_Naturoll 035_140x580x5300mm:35137
In: Lengte
PredefinedType: ROOF; Classification: 27 Daken (Uniformat); Material: Knauf Insulation_Ecose® glaswol_naturoll 035 140 mm
Pset_ElementShading - Roughness: 304.8 mm
Pset_ManufacturerTypeInformation - Manufacturer: Knauf Insulation B.V.
Pset_ProductRequirements - Category: Roofs
Pset_QuantityTakeOff - Reference: NLRS_27_RO_Naturoll 035_140x580x5300mm
Pset_ReinforcementBarPitchOfSlab - Description: Naturoll 035 - 140mm; Reference: NLRS_27_RO_Naturoll 035_140x580x5300mm
Pset_SlabCommon - PitchAngle: 0 deg; IsExternal: yes; ThermalTransmittance: 0.25 kg/K/s3; Reference: NLRS_27_RO_Naturoll 035_140x580x5300mm
BaseQuantities - GrossArea: 0.185806 m2; NetArea: 4.84 m2; GrossVolume: 26.0129 m3; NetVolume: 0.28 m3; Perimeter: 6000 mm; Width: 140 mm

# IfcSlab: Basic Roof:NLRS_27_RO_Naturoll 035_140x600x5300mm, Basic Roof:NLRS_27_RO_Naturoll 035_140x600x5300mm:35157
In: Lengte
PredefinedType: ROOF; Classification: 27 Daken (Uniformat); Material: Knauf Insulation_Ecose® glaswol_naturoll 035 140 mm
Pset_ElementShading - Roughness: 304.8 mm
Pset_ManufacturerTypeInformation - Manufacturer: Knauf Insulation B.V.
Pset_ProductRequirements - Category: Roofs
Pset_QuantityTakeOff - Reference: NLRS_27_RO_Naturoll 035_140x600x5300mm
Pset_ReinforcementBarPitchOfSlab - Description: Naturoll 035 - 140mm; Reference: NLRS_27_RO_Naturoll 035_140x600x5300mm
Pset_SlabCommon - PitchAngle: 0 deg; IsExternal: yes; ThermalTransmittance: 0.25 kg/K/s3; Reference: NLRS_27_RO_Naturoll 035_140x600x5300mm
BaseQuantities - GrossArea: 0.185806 m2; NetArea: 4.84 m2; GrossVolume: 26.0129 m3; NetVolume: 0.28 m3; Perimeter: 6000 mm; Width: 140 mm

# IfcSlab: Basic Roof:NLRS_27_RO_Naturoll 035_170x380x4350mm, Basic Roof:NLRS_27_RO_Naturoll 035_170x380x4350mm:35177
In: Lengte
PredefinedType: ROOF; Classification: 27 Daken (Uniformat); Material: Knauf Insulation_Ecose® glaswol_naturoll 035 170 mm
Pset_ElementShading - Roughness: 304.8 mm
Pset_ManufacturerTypeInformation - Manufacturer: Knauf Insulation B.V.
Pset_ProductRequirements - Category: Roofs
Pset_QuantityTakeOff - Reference: NLRS_27_RO_Naturoll 035_170x380x4350mm
Pset_ReinforcementBarPitchOfSlab - Description: Naturoll 035 - 170mm; Reference: NLRS_27_RO_Naturoll 035_170x380x4350mm
Pset_SlabCommon - PitchAngle: 0 deg; IsExternal: yes; Reference: NLRS_27_RO_Naturoll 035_170x380x4350mm; ThermalTransmittance: 0.205882 kg/K/s3
BaseQuantities - GrossArea: 0.185806 m2; NetArea: 5.02 m2; GrossVolume: 31.587 m3; NetVolume: 0.34 m3; Perimeter: 6000 mm; Width: 170 mm

# IfcSlab: Basic Roof:NLRS_27_RO_Naturoll 035_170x580x4350mm, Basic Roof:NLRS_27_RO_Naturoll 035_170x580x4350mm:35197
In: Lengte
PredefinedType: ROOF; Classification: 27 Daken (Uniformat); Material: Knauf Insulation_Ecose® glaswol_naturoll 035 170 mm
Pset_ElementShading - Roughness: 304.8 mm
Pset_ManufacturerTypeInformation - Manufacturer: Knauf Insulation B.V.
Pset_ProductRequirements - Category: Roofs
Pset_QuantityTakeOff - Reference: NLRS_27_RO_Naturoll 035_170x580x4350mm
Pset_ReinforcementBarPitchOfSlab - Description: Naturoll 035 - 170mm; Reference: NLRS_27_RO_Naturoll 035_170x580x4350mm
Pset_SlabCommon - PitchAngle: 0 deg; IsExternal: yes; Reference: NLRS_27_RO_Naturoll 035_170x580x4350mm; ThermalTransmittance: 0.205882 kg/K/s3
BaseQuantities - GrossArea: 0.185806 m2; NetArea: 5.02 m2; GrossVolume: 31.587 m3; NetVolume: 0.34 m3; Perimeter: 6000 mm; Width: 170 mm

# IfcSlab: Basic Roof:NLRS_27_RO_Naturoll 035_185x380x4000mm, Basic Roof:NLRS_27_RO_Naturoll 035_185x380x4000mm:35217
In: Lengte
PredefinedType: ROOF; Classification: 27 Daken (Uniformat); Material: Knauf Insulation_Ecose® glaswol_naturoll 035 185 mm
Pset_ElementShading - Roughness: 304.8 mm
Pset_ManufacturerTypeInformation - Manufacturer: Knauf Insulation B.V.
Pset_ProductRequirements - Category: Roofs
Pset_QuantityTakeOff - Reference: NLRS_27_RO_Naturoll 035_185x380x4000mm
Pset_ReinforcementBarPitchOfSlab - Description: Naturoll 035 - 185mm; Reference: NLRS_27_RO_Naturoll 035_185x380x4000mm
Pset_SlabCommon - PitchAngle: 0 deg; IsExternal: yes; Reference: NLRS_27_RO_Naturoll 035_185x380x4000mm; ThermalTransmittance: 0.189189 kg/K/s3
BaseQuantities - GrossArea: 0.185806 m2; NetArea: 5.11 m2; GrossVolume: 34.3741 m3; NetVolume: 0.37 m3; Perimeter: 6000 mm; Width: 185 mm

# IfcSlab: Basic Roof:NLRS_27_RO_Naturoll 035_185x580x4000mm, Basic Roof:NLRS_27_RO_Naturoll 035_185x580x4000mm:37505
In: Lengte
PredefinedType: ROOF; Classification: 27 Daken (Uniformat); Material: Knauf Insulation_Ecose® glaswol_naturoll 035 185 mm
Pset_ElementShading - Roughness: 304.8 mm
Pset_ManufacturerTypeInformation - Manufacturer: Knauf Insulation B.V.
Pset_ProductRequirements - Category: Roofs
Pset_QuantityTakeOff - Reference: NLRS_27_RO_Naturoll 035_185x580x4000mm
Pset_ReinforcementBarPitchOfSlab - Description: Naturoll 035 - 185mm; Reference: NLRS_27_RO_Naturoll 035_185x580x4000mm
Pset_SlabCommon - PitchAngle: 0 deg; IsExternal: yes; Reference: NLRS_27_RO_Naturoll 035_185x580x4000mm; ThermalTransmittance: 0.189189 kg/K/s3
BaseQuantities - GrossArea: 0.185806 m2; NetArea: 5.11 m2; GrossVolume: 34.3741 m3; NetVolume: 0.37 m3; Perimeter: 6000 mm; Width: 185 mm

# IfcSlab: Basic Roof:NLRS_27_RO_Naturoll 035_195x580x3800mm, Basic Roof:NLRS_27_RO_Naturoll 035_195x580x3800mm:35644
In: Lengte
PredefinedType: ROOF; Classification: 27 Daken (Uniformat); Material: Knauf Insulation_Ecose® glaswol_naturoll 035 195 mm
Pset_ElementShading - Roughness: 304.8 mm
Pset_ManufacturerTypeInformation - Manufacturer: Knauf Insulation B.V.
Pset_ProductRequirements - Category: Roofs
Pset_QuantityTakeOff - Reference: NLRS_27_RO_Naturoll 035_195x580x3800mm
Pset_ReinforcementBarPitchOfSlab - Description: Naturoll 035 - 195mm; Reference: NLRS_27_RO_Naturoll 035_195x580x3800mm
Pset_SlabCommon - PitchAngle: 0 deg; IsExternal: yes; Reference: NLRS_27_RO_Naturoll 035_195x580x3800mm; ThermalTransmittance: 0.179487 kg/K/s3
BaseQuantities - GrossArea: 0.185806 m2; NetArea: 5.17 m2; GrossVolume: 36.2322 m3; NetVolume: 0.39 m3; Perimeter: 6000 mm; Width: 195 mm

# IfcSlab: Basic Roof:NLRS_27_RO_Naturoll 035_200x580x3700mm, Basic Roof:NLRS_27_RO_Naturoll 035_200x580x3700mm:35405
In: Lengte
PredefinedType: ROOF; Classification: 27 Daken (Uniformat); Material: Knauf Insulation_Ecose® glaswol_naturoll 035 200 mm
Pset_ElementShading - Roughness: 304.8 mm
Pset_ManufacturerTypeInformation - Manufacturer: Knauf Insulation B.V.
Pset_ProductRequirements - Category: Roofs
Pset_QuantityTakeOff - Reference: NLRS_27_RO_Naturoll 035_200x580x3700mm
Pset_ReinforcementBarPitchOfSlab - Description: Naturoll 035 - 200mm; Reference: NLRS_27_RO_Naturoll 035_200x580x3700mm
Pset_SlabCommon - PitchAngle: 0 deg; IsExternal: yes; Reference: NLRS_27_RO_Naturoll 035_200x580x3700mm; ThermalTransmittance: 0.175 kg/K/s3
BaseQuantities - GrossArea: 0.185806 m2; NetArea: 5.2 m2; GrossVolume: 37.1612 m3; NetVolume: 0.4 m3; Perimeter: 6000 mm; Width: 200 mm

# IfcSlab: Basic Roof:NLRS_27_RO_Naturoll 035_220x380x3400mm, Basic Roof:NLRS_27_RO_Naturoll 035_220x380x3400mm:35424
In: Lengte
PredefinedType: ROOF; Classification: 27 Daken (Uniformat); Material: Knauf Insulation_Ecose® glaswol_naturoll 035 220 mm
Pset_ElementShading - Roughness: 304.8 mm
Pset_ManufacturerTypeInformation - Manufacturer: Knauf Insulation B.V.
Pset_ProductRequirements - Category: Roofs
Pset_QuantityTakeOff - Reference: NLRS_27_RO_Naturoll 035_220x380x3400mm
Pset_ReinforcementBarPitchOfSlab - Description: Naturoll 035 - 220mm; Reference: NLRS_27_RO_Naturoll 035_220x380x3400mm
Pset_SlabCommon - PitchAngle: 0 deg; IsExternal: yes; Reference: NLRS_27_RO_Naturoll 035_220x380x3400mm; ThermalTransmittance: 0.159091 kg/K/s3
BaseQuantities - GrossArea: 0.185806 m2; NetArea: 5.32 m2; GrossVolume: 40.8773 m3; NetVolume: 0.44 m3; Perimeter: 6000 mm; Width: 220 mm

# IfcSlab: Basic Roof:NLRS_27_RO_Naturoll 035_220x580x3100mm, Basic Roof:NLRS_27_RO_Naturoll 035_220x580x3100mm:35443
In: Lengte
PredefinedType: ROOF; Classification: 27 Daken (Uniformat); Material: Knauf Insulation_Ecose® glaswol_naturoll 035 220 mm
Pset_ElementShading - Roughness: 304.8 mm
Pset_ManufacturerTypeInformation - Manufacturer: Knauf Insulation B.V.
Pset_ProductRequirements - Category: Roofs
Pset_QuantityTakeOff - Reference: NLRS_27_RO_Naturoll 035_220x580x3100mm
Pset_ReinforcementBarPitchOfSlab - Description: Naturoll 035 - 220mm; Reference: NLRS_27_RO_Naturoll 035_220x580x3100mm
Pset_SlabCommon - PitchAngle: 0 deg; IsExternal: yes; Reference: NLRS_27_RO_Naturoll 035_220x580x3100mm; ThermalTransmittance: 0.159091 kg/K/s3
BaseQuantities - GrossArea: 0.185806 m2; NetArea: 5.32 m2; GrossVolume: 40.8773 m3; NetVolume: 0.44 m3; Perimeter: 6000 mm; Width: 220 mm

# IfcSlab: Basic Roof:NLRS_27_RO_Naturoll 035_235x580x3100mm, Basic Roof:NLRS_27_RO_Naturoll 035_235x580x3100mm:35462
In: Lengte
PredefinedType: ROOF; Classification: 27 Daken (Uniformat); Material: Knauf Insulation_Ecose® glaswol_naturoll 035 235 mm
Pset_ElementShading - Roughness: 304.8 mm
Pset_ManufacturerTypeInformation - Manufacturer: Knauf Insulation B.V.
Pset_ProductRequirements - Category: Roofs
Pset_QuantityTakeOff - Reference: NLRS_27_RO_Naturoll 035_235x580x3100mm
Pset_ReinforcementBarPitchOfSlab - Description: Naturoll 035 - 235mm; Reference: NLRS_27_RO_Naturoll 035_235x580x3100mm
Pset_SlabCommon - PitchAngle: 0 deg; IsExternal: yes; Reference: NLRS_27_RO_Naturoll 035_235x580x3100mm; ThermalTransmittance: 0.148936 kg/K/s3
BaseQuantities - GrossArea: 0.185806 m2; NetArea: 5.41 m2; GrossVolume: 43.6644 m3; NetVolume: 0.47 m3; Perimeter: 6000 mm; Width: 235 mm

# IfcSlab: Basic Roof:NLRS_27_RO_Naturoll 035_240x580x3100mm, Basic Roof:NLRS_27_RO_Naturoll 035_240x580x3100mm:35481
In: Lengte
PredefinedType: ROOF; Classification: 27 Daken (Uniformat); Material: Knauf Insulation_Ecose® glaswol_naturoll 035 240 mm
Pset_ElementShading - Roughness: 304.8 mm
Pset_ManufacturerTypeInformation - Manufacturer: Knauf Insulation B.V.
Pset_ProductRequirements - Category: Roofs
Pset_QuantityTakeOff - Reference: NLRS_27_RO_Naturoll 035_240x580x3100mm
Pset_ReinforcementBarPitchOfSlab - Description: Naturoll 035 - 240mm; Reference: NLRS_27_RO_Naturoll 035_240x580x3100mm
Pset_SlabCommon - PitchAngle: 0 deg; IsExternal: yes; Reference: NLRS_27_RO_Naturoll 035_240x580x3100mm; ThermalTransmittance: 0.145833 kg/K/s3
BaseQuantities - GrossArea: 0.185806 m2; NetArea: 5.44 m2; GrossVolume: 44.5935 m3; NetVolume: 0.48 m3; Perimeter: 6000 mm; Width: 240 mm

# IfcSlab: Basic Roof:NLRS_27_RO_Naturoll 035_270x590x2600mm, Basic Roof:NLRS_27_RO_Naturoll 035_270x590x2600mm:35500
In: Lengte
PredefinedType: ROOF; Classification: 27 Daken (Uniformat); Material: Knauf Insulation_Ecose® glaswol_naturoll 035 270 mm
Pset_ElementShading - Roughness: 304.8 mm
Pset_ManufacturerTypeInformation - Manufacturer: Knauf Insulation B.V.
Pset_ProductRequirements - Category: Roofs
Pset_QuantityTakeOff - Reference: NLRS_27_RO_Naturoll 035_270x590x2600mm
Pset_ReinforcementBarPitchOfSlab - Description: Naturoll 035 - 270mm; Reference: NLRS_27_RO_Naturoll 035_270x590x2600mm
Pset_SlabCommon - PitchAngle: 0 deg; IsExternal: yes; Reference: NLRS_27_RO_Naturoll 035_270x590x2600mm; ThermalTransmittance: 0.12963 kg/K/s3
BaseQuantities - GrossArea: 0.185806 m2; NetArea: 5.62 m2; GrossVolume: 50.1676 m3; NetVolume: 0.54 m3; Perimeter: 6000 mm; Width: 270 mm

# IfcSlab: Basic Roof:NLRS_27_RO_Naturoll 035_90x380x7600mm, Basic Roof:NLRS_27_RO_Naturoll 035_90x380x7600mm:34727
In: Lengte
PredefinedType: ROOF; Classification: 27 Daken (Uniformat); Material: Knauf Insulation_Ecose® glaswol_naturoll 035 90 mm
Pset_ElementShading - Roughness: 304.8 mm
Pset_ManufacturerTypeInformation - Manufacturer: Knauf Insulation B.V.
Pset_ProductRequirements - Category: Roofs
Pset_QuantityTakeOff - Reference: NLRS_27_RO_Naturoll 035_90x380x7600mm
Pset_ReinforcementBarPitchOfSlab - Description: Naturoll 035 - 90mm; Reference: NLRS_27_RO_Naturoll 035_90x380x7600mm
Pset_SlabCommon - PitchAngle: 0 deg; IsExternal: yes; Reference: NLRS_27_RO_Naturoll 035_90x380x7600mm; ThermalTransmittance: 0.388889 kg/K/s3
BaseQuantities - GrossArea: 0.185806 m2; NetArea: 4.54 m2; GrossVolume: 16.7225 m3; NetVolume: 0.18 m3; Perimeter: 6000 mm; Width: 90 mm

# IfcSlab: Basic Roof:NLRS_27_RO_Naturoll 035_90x580x7600mm, Basic Roof:NLRS_27_RO_Naturoll 035_90x580x7600mm:34921
In: Lengte
PredefinedType: ROOF; Classification: 27 Daken (Uniformat); Material: Knauf Insulation_Ecose® glaswol_naturoll 035 90 mm
Pset_ElementShading - Roughness: 304.8 mm
Pset_ManufacturerTypeInformation - Manufacturer: Knauf Insulation B.V.
Pset_ProductRequirements - Category: Roofs
Pset_QuantityTakeOff - Reference: NLRS_27_RO_Naturoll 035_90x580x7600mm
Pset_ReinforcementBarPitchOfSlab - Description: Naturoll 035 - 90mm; Reference: NLRS_27_RO_Naturoll 035_90x580x7600mm
Pset_SlabCommon - PitchAngle: 0 deg; IsExternal: yes; Reference: NLRS_27_RO_Naturoll 035_90x580x7600mm; ThermalTransmittance: 0.388889 kg/K/s3
BaseQuantities - GrossArea: 0.185806 m2; NetArea: 4.54 m2; GrossVolume: 16.7225 m3; NetVolume: 0.18 m3; Perimeter: 6000 mm; Width: 90 mm

# IfcSlab: Floor:NLRS_23_FL_Naturoll 035_100x580x7400mm, Floor:NLRS_23_FL_Naturoll 035_100x580x7400mm:34991
In: Begane grond
Type - PredefinedType: FLOOR; Material: Knauf Insulation_Ecose® glaswol_naturoll 035 100 mm
Type - Analytical Properties - Roughness: 1; Thermal mass: 0; Absorptance: 0.1; Heat Transfer Coefficient (U): 0.35; Thermal Resistance (R): 2.85714
Type - Construction - Function: Interior; Default Thickness: 100 mm
Type - Graphics - Coarse Scale Fill Color: 0
Type - Identity Data - Type Image: Raster image: Naturoll 035 .jpg (2); Assembly Code: 23; Assembly Description: Vloeren; Description: Naturoll 035 - 100mm; Manufacturer: Knauf Insulation B.V.; Model: Naturoll 035 is een onbeklede glaswoldeken met ECOSE® Technology; Type Name: NLRS_23_FL_Naturoll 035_100x580x7400mm; URL: www.knaufinsulation.nl
Type - Other - Category: Floors; Family Name: Floor
Type - Pset_ElementShading - Roughness: 304.8 mm
Type - Pset_ManufacturerTypeInformation - Manufacturer: Knauf Insulation B.V.
Type - Pset_ProductRequirements - Category: Floors
Type - Pset_QuantityTakeOff - Reference: NLRS_23_FL_Naturoll 035_100x580x7400mm
Type - Pset_ReinforcementBarPitchOfSlab - Description: Naturoll 035 - 100mm; Reference: NLRS_23_FL_Naturoll 035_100x580x7400mm
Type - Pset_SlabCommon - IsExternal: no; Reference: NLRS_23_FL_Naturoll 035_100x580x7400mm; ThermalTransmittance: 0.35 kg/K/s3
Classification: 23 Vloeren (Uniformat)
Pset_SlabCommon - LoadBearing: no; PitchAngle: 0 deg
BaseQuantities - GrossArea: 2 m2; NetArea: 4.6 m2; GrossVolume: 200 m3; NetVolume: 0.2 m3; Perimeter: 6000 mm; Width: 100 mm
Constraints - Height Offset From Level: 0 mm; Level: Level: Begane grond; Related to Mass: no; Room Bounding: yes
Dimensions - Elevation at Top: 0 mm; Area: 2 m2; Elevation at Bottom: -100 mm; Perimeter: 6000 mm; Thickness: 100 mm; Volume: 0.2 m3
Other - Family: Floor: NLRS_23_FL_Naturoll 035_100x580x7400mm; Family and Type: Floor: NLRS_23_FL_Naturoll 035_100x580x7400mm; Type: Floor: NLRS_23_FL_Naturoll 035_100x580x7400mm; Type Id: Floor: NLRS_23_FL_Naturoll 035_100x580x7400mm
Phasing - Phase Created: New Construction
Structural - Enable Analytical Model: no; Structural: no

# IfcSlab: Floor:NLRS_23_FL_Naturoll 035_120x380x6200mm, Floor:NLRS_23_FL_Naturoll 035_120x380x6200mm:35013
In: Begane grond
Type - PredefinedType: FLOOR; Material: Knauf Insulation_Ecose® glaswol_naturoll 035 120 mm
Type - Analytical Properties - Roughness: 1; Thermal mass: 0; Absorptance: 0.1; Heat Transfer Coefficient (U): 0.291667; Thermal Resistance (R): 3.42857
Type - Construction - Function: Interior; Default Thickness: 120 mm
Type - Graphics - Coarse Scale Fill Color: 0
Type - Identity Data - Type Image: Raster image: Naturoll 035 .jpg (2); Assembly Code: 23; Assembly Description: Vloeren; Description: Naturoll 035 - 120mm; Manufacturer: Knauf Insulation B.V.; Model: Naturoll 035 is een onbeklede glaswoldeken met ECOSE® Technology; Type Name: NLRS_23_FL_Naturoll 035_120x380x6200mm; URL: www.knaufinsulation.nl
Type - Other - Category: Floors; Family Name: Floor
Type - Pset_ElementShading - Roughness: 304.8 mm
Type - Pset_ManufacturerTypeInformation - Manufacturer: Knauf Insulation B.V.
Type - Pset_ProductRequirements - Category: Floors
Type - Pset_QuantityTakeOff - Reference: NLRS_23_FL_Naturoll 035_120x380x6200mm
Type - Pset_ReinforcementBarPitchOfSlab - Description: Naturoll 035 - 120mm; Reference: NLRS_23_FL_Naturoll 035_120x380x6200mm
Type - Pset_SlabCommon - IsExternal: no; Reference: NLRS_23_FL_Naturoll 035_120x380x6200mm; ThermalTransmittance: 0.291667 kg/K/s3
Classification: 23 Vloeren (Uniformat)
Pset_SlabCommon - LoadBearing: no; PitchAngle: 0 deg
BaseQuantities - GrossArea: 2 m2; NetArea: 4.72 m2; GrossVolume: 240 m3; NetVolume: 0.24 m3; Perimeter: 6000 mm; Width: 120 mm
Constraints - Height Offset From Level: 0 mm; Level: Level: Begane grond; Related to Mass: no; Room Bounding: yes
Dimensions - Elevation at Top: 0 mm; Area: 2 m2; Elevation at Bottom: -120 mm; Perimeter: 6000 mm; Thickness: 120 mm; Volume: 0.24 m3
Other - Family: Floor: NLRS_23_FL_Naturoll 035_120x380x6200mm; Family and Type: Floor: NLRS_23_FL_Naturoll 035_120x380x6200mm; Type: Floor: NLRS_23_FL_Naturoll 035_120x380x6200mm; Type Id: Floor: NLRS_23_FL_Naturoll 035_120x380x6200mm
Phasing - Phase Created: New Construction
Structural - Enable Analytical Model: no; Structural: no

# IfcSlab: Floor:NLRS_23_FL_Naturoll 035_120x580x6200mm, Floor:NLRS_23_FL_Naturoll 035_120x580x6200mm:35035
In: Begane grond
Type - PredefinedType: FLOOR; Material: Knauf Insulation_Ecose® glaswol_naturoll 035 120 mm
Type - Analytical Properties - Roughness: 1; Thermal mass: 0; Absorptance: 0.1; Heat Transfer Coefficient (U): 0.291667; Thermal Resistance (R): 3.42857
Type - Construction - Function: Interior; Default Thickness: 120 mm
Type - Graphics - Coarse Scale Fill Color: 0
Type - Identity Data - Type Image: Raster image: Naturoll 035 .jpg (2); Assembly Code: 23; Assembly Description: Vloeren; Description: Naturoll 035 - 120mm; Manufacturer: Knauf Insulation B.V.; Model: Naturoll 035 is een onbeklede glaswoldeken met ECOSE® Technology; Type Name: NLRS_23_FL_Naturoll 035_120x580x6200mm; URL: www.knaufinsulation.nl
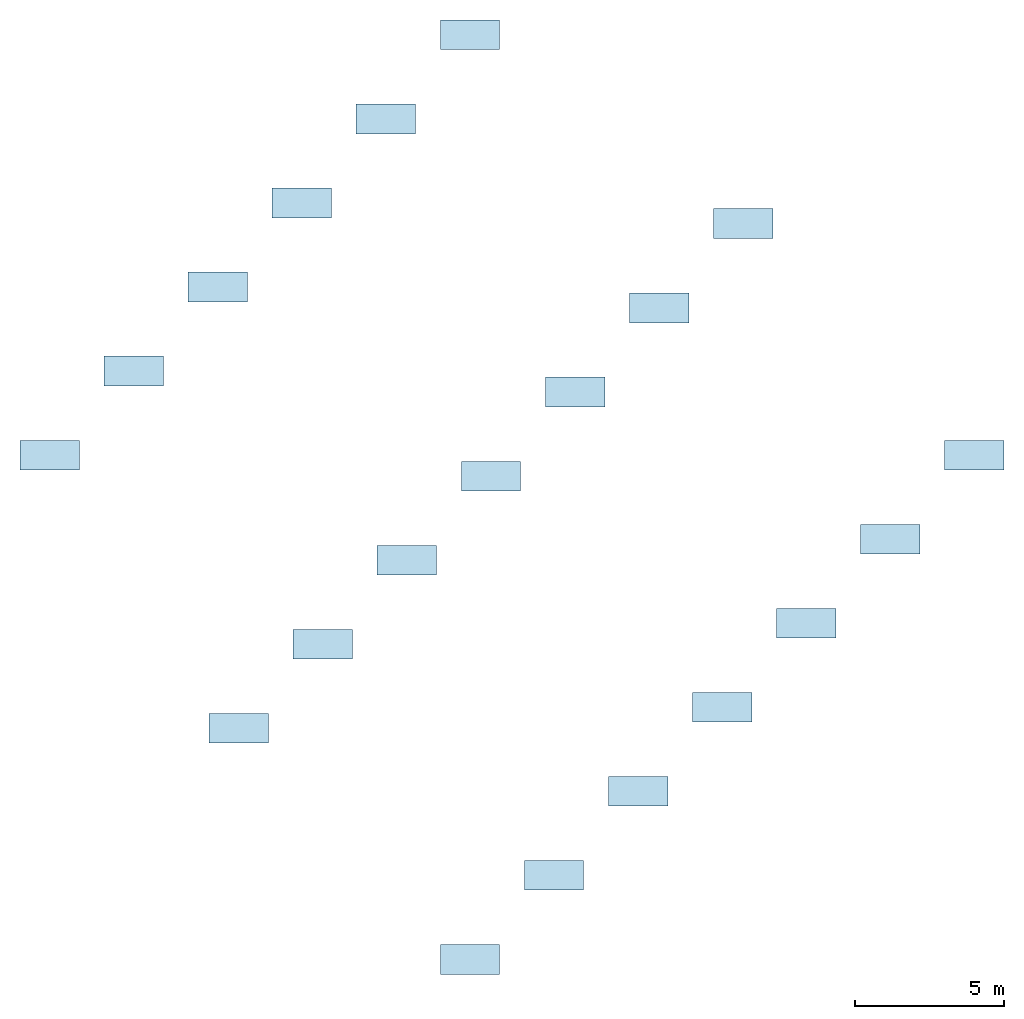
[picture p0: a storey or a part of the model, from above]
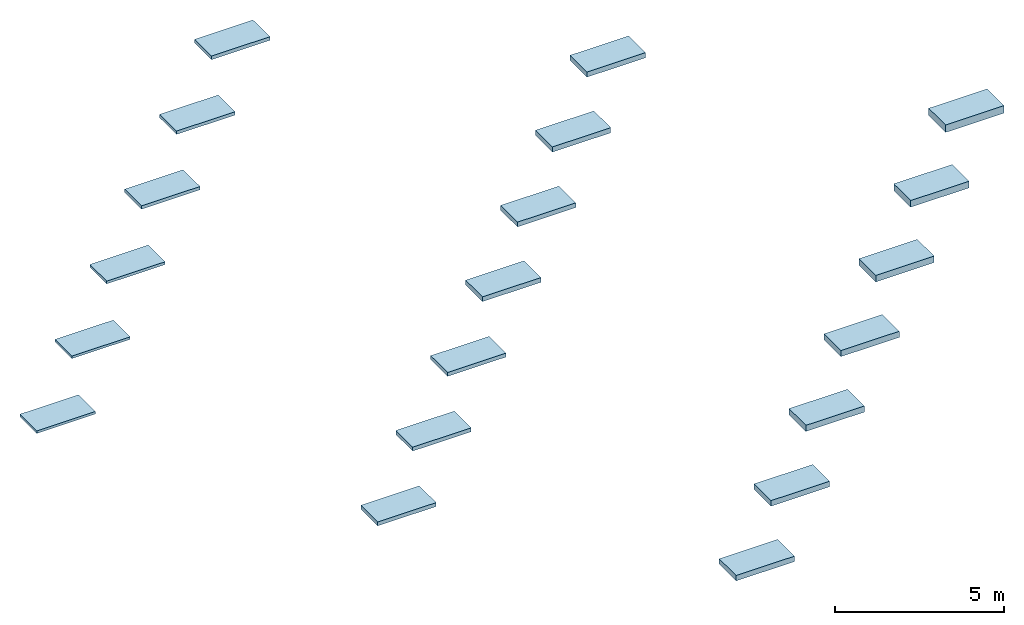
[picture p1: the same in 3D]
Properties of the parts of a building model (IFC2X3), part 2 of 3

# IfcSlab: Floor:NLRS_23_FL_Naturoll 035_120x580x6200mm, Floor:NLRS_23_FL_Naturoll 035_120x580x6200mm:35035
Type - Other - Category: Floors; Family Name: Floor
Type - Pset_ElementShading - Roughness: 304.8 mm
Type - Pset_ManufacturerTypeInformation - Manufacturer: Knauf Insulation B.V.
Type - Pset_ProductRequirements - Category: Floors
Type - Pset_QuantityTakeOff - Reference: NLRS_23_FL_Naturoll 035_120x580x6200mm
Type - Pset_ReinforcementBarPitchOfSlab - Description: Naturoll 035 - 120mm; Reference: NLRS_23_FL_Naturoll 035_120x580x6200mm
Type - Pset_SlabCommon - IsExternal: no; Reference: NLRS_23_FL_Naturoll 035_120x580x6200mm; ThermalTransmittance: 0.291667 kg/K/s3
Classification: 23 Vloeren (Uniformat)
Pset_SlabCommon - LoadBearing: no; PitchAngle: 0 deg
BaseQuantities - GrossArea: 2 m2; NetArea: 4.72 m2; GrossVolume: 240 m3; NetVolume: 0.24 m3; Perimeter: 6000 mm; Width: 120 mm
Constraints - Height Offset From Level: 0 mm; Related to Mass: no; Room Bounding: yes; Level: Level: Begane grond
Dimensions - Elevation at Top: 0 mm; Area: 2 m2; Elevation at Bottom: -120 mm; Perimeter: 6000 mm; Thickness: 120 mm; Volume: 0.24 m3
Other - Family: Floor: NLRS_23_FL_Naturoll 035_120x580x6200mm; Family and Type: Floor: NLRS_23_FL_Naturoll 035_120x580x6200mm; Type: Floor: NLRS_23_FL_Naturoll 035_120x580x6200mm; Type Id: Floor: NLRS_23_FL_Naturoll 035_120x580x6200mm
Phasing - Phase Created: New Construction
Structural - Enable Analytical Model: no; Structural: no

# IfcSlab: Floor:NLRS_23_FL_Naturoll 035_130x590x5500mm, Floor:NLRS_23_FL_Naturoll 035_130x590x5500mm:35057
In: Begane grond
Type - PredefinedType: FLOOR; Material: Knauf Insulation_Ecose® glaswol_naturoll 035 130 mm
Type - Analytical Properties - Roughness: 1; Thermal mass: 0; Absorptance: 0.1; Heat Transfer Coefficient (U): 0.269231; Thermal Resistance (R): 3.71429
Type - Construction - Function: Interior; Default Thickness: 130 mm
Type - Graphics - Coarse Scale Fill Color: 0
Type - Identity Data - Type Image: Raster image: Naturoll 035 .jpg (2); Assembly Code: 23; Assembly Description: Vloeren; Description: Naturoll 035 - 130mm; Manufacturer: Knauf Insulation B.V.; Model: Naturoll 035 is een onbeklede glaswoldeken met ECOSE® Technology; Type Name: NLRS_23_FL_Naturoll 035_130x590x5500mm; URL: www.knaufinsulation.nl
Type - Other - Category: Floors; Family Name: Floor
Type - Pset_ElementShading - Roughness: 304.8 mm
Type - Pset_ManufacturerTypeInformation - Manufacturer: Knauf Insulation B.V.
Type - Pset_ProductRequirements - Category: Floors
Type - Pset_QuantityTakeOff - Reference: NLRS_23_FL_Naturoll 035_130x590x5500mm
Type - Pset_ReinforcementBarPitchOfSlab - Description: Naturoll 035 - 130mm; Reference: NLRS_23_FL_Naturoll 035_130x590x5500mm
Type - Pset_SlabCommon - IsExternal: no; Reference: NLRS_23_FL_Naturoll 035_130x590x5500mm; ThermalTransmittance: 0.269231 kg/K/s3
Classification: 23 Vloeren (Uniformat)
Pset_SlabCommon - LoadBearing: no; PitchAngle: 0 deg
BaseQuantities - GrossArea: 2 m2; NetArea: 4.78 m2; GrossVolume: 260 m3; NetVolume: 0.26 m3; Perimeter: 6000 mm; Width: 130 mm
Constraints - Height Offset From Level: 0 mm; Related to Mass: no; Room Bounding: yes; Level: Level: Begane grond
Dimensions - Elevation at Top: 0 mm; Area: 2 m2; Elevation at Bottom: -130 mm; Perimeter: 6000 mm; Thickness: 130 mm; Volume: 0.26 m3
Other - Family: Floor: NLRS_23_FL_Naturoll 035_130x590x5500mm; Family and Type: Floor: NLRS_23_FL_Naturoll 035_130x590x5500mm; Type: Floor: NLRS_23_FL_Naturoll 035_130x590x5500mm; Type Id: Floor: NLRS_23_FL_Naturoll 035_130x590x5500mm
Phasing - Phase Created: New Construction
Structural - Enable Analytical Model: no; Structural: no

# IfcSlab: Floor:NLRS_23_FL_Naturoll 035_140x380x5300mm, Floor:NLRS_23_FL_Naturoll 035_140x380x5300mm:35107
In: Begane grond
Type - PredefinedType: FLOOR; Material: Knauf Insulation_Ecose® glaswol_naturoll 035 140 mm
Type - Analytical Properties - Roughness: 1; Thermal mass: 0; Absorptance: 0.1; Heat Transfer Coefficient (U): 0.25; Thermal Resistance (R): 4
Type - Construction - Function: Interior; Default Thickness: 140 mm
Type - Graphics - Coarse Scale Fill Color: 0
Type - Identity Data - Type Image: Raster image: Naturoll 035 .jpg (2); Assembly Code: 23; Assembly Description: Vloeren; Description: Naturoll 035 - 140mm; Manufacturer: Knauf Insulation B.V.; Model: Naturoll 035 is een onbeklede glaswoldeken met ECOSE® Technology; Type Name: NLRS_23_FL_Naturoll 035_140x380x5300mm; URL: www.knaufinsulation.nl
Type - Other - Category: Floors; Family Name: Floor
Type - Pset_ElementShading - Roughness: 304.8 mm
Type - Pset_ManufacturerTypeInformation - Manufacturer: Knauf Insulation B.V.
Type - Pset_ProductRequirements - Category: Floors
Type - Pset_QuantityTakeOff - Reference: NLRS_23_FL_Naturoll 035_140x380x5300mm
Type - Pset_ReinforcementBarPitchOfSlab - Description: Naturoll 035 - 140mm; Reference: NLRS_23_FL_Naturoll 035_140x380x5300mm
Type - Pset_SlabCommon - IsExternal: no; Reference: NLRS_23_FL_Naturoll 035_140x380x5300mm; ThermalTransmittance: 0.25 kg/K/s3
Classification: 23 Vloeren (Uniformat)
Pset_SlabCommon - LoadBearing: no; PitchAngle: 0 deg
BaseQuantities - GrossArea: 2 m2; NetArea: 4.84 m2; GrossVolume: 280 m3; NetVolume: 0.28 m3; Perimeter: 6000 mm; Width: 140 mm
Constraints - Height Offset From Level: 0 mm; Level: Level: Begane grond; Related to Mass: no; Room Bounding: yes
Dimensions - Elevation at Top: 0 mm; Area: 2 m2; Elevation at Bottom: -140 mm; Perimeter: 6000 mm; Thickness: 140 mm; Volume: 0.28 m3
Other - Family: Floor: NLRS_23_FL_Naturoll 035_140x380x5300mm; Family and Type: Floor: NLRS_23_FL_Naturoll 035_140x380x5300mm; Type: Floor: NLRS_23_FL_Naturoll 035_140x380x5300mm; Type Id: Floor: NLRS_23_FL_Naturoll 035_140x380x5300mm
Phasing - Phase Created: New Construction
Structural - Enable Analytical Model: no; Structural: no

# IfcSlab: Floor:NLRS_23_FL_Naturoll 035_140x580x5300mm, Floor:NLRS_23_FL_Naturoll 035_140x580x5300mm:35127
In: Begane grond
Type - PredefinedType: FLOOR; Material: Knauf Insulation_Ecose® glaswol_naturoll 035 140 mm
Type - Analytical Properties - Roughness: 1; Thermal mass: 0; Thermal Resistance (R): 4; Absorptance: 0.1; Heat Transfer Coefficient (U): 0.25
Type - Construction - Function: Interior; Default Thickness: 140 mm
Type - Graphics - Coarse Scale Fill Color: 0
Type - Identity Data - Type Image: Raster image: Naturoll 035 .jpg (2); Assembly Code: 23; Assembly Description: Vloeren; Description: Naturoll 035 - 140mm; Manufacturer: Knauf Insulation B.V.; Model: Naturoll 035 is een onbeklede glaswoldeken met ECOSE® Technology; Type Name: NLRS_23_FL_Naturoll 035_140x580x5300mm; URL: www.knaufinsulation.nl
Type - Other - Category: Floors; Family Name: Floor
Type - Pset_ElementShading - Roughness: 304.8 mm
Type - Pset_ManufacturerTypeInformation - Manufacturer: Knauf Insulation B.V.
Type - Pset_ProductRequirements - Category: Floors
Type - Pset_QuantityTakeOff - Reference: NLRS_23_FL_Naturoll 035_140x580x5300mm
Type - Pset_ReinforcementBarPitchOfSlab - Description: Naturoll 035 - 140mm; Reference: NLRS_23_FL_Naturoll 035_140x580x5300mm
Type - Pset_SlabCommon - IsExternal: no; ThermalTransmittance: 0.25 kg/K/s3; Reference: NLRS_23_FL_Naturoll 035_140x580x5300mm
Classification: 23 Vloeren (Uniformat)
Pset_SlabCommon - LoadBearing: no; PitchAngle: 0 deg
BaseQuantities - GrossArea: 2 m2; NetArea: 4.84 m2; GrossVolume: 280 m3; NetVolume: 0.28 m3; Perimeter: 6000 mm; Width: 140 mm
Constraints - Height Offset From Level: 0 mm; Level: Level: Begane grond; Related to Mass: no; Room Bounding: yes
Dimensions - Elevation at Top: 0 mm; Area: 2 m2; Elevation at Bottom: -140 mm; Perimeter: 6000 mm; Thickness: 140 mm; Volume: 0.28 m3
Other - Family: Floor: NLRS_23_FL_Naturoll 035_140x580x5300mm; Family and Type: Floor: NLRS_23_FL_Naturoll 035_140x580x5300mm; Type: Floor: NLRS_23_FL_Naturoll 035_140x580x5300mm; Type Id: Floor: NLRS_23_FL_Naturoll 035_140x580x5300mm
Phasing - Phase Created: New Construction
Structural - Enable Analytical Model: no; Structural: no

# IfcSlab: Floor:NLRS_23_FL_Naturoll 035_140x600x5300mm, Floor:NLRS_23_FL_Naturoll 035_140x600x5300mm:35147
In: Begane grond
Type - PredefinedType: FLOOR; Material: Knauf Insulation_Ecose® glaswol_naturoll 035 140 mm
Type - Analytical Properties - Roughness: 1; Thermal mass: 0; Thermal Resistance (R): 4; Absorptance: 0.1; Heat Transfer Coefficient (U): 0.25
Type - Construction - Function: Interior; Default Thickness: 140 mm
Type - Graphics - Coarse Scale Fill Color: 0
Type - Identity Data - Type Image: Raster image: Naturoll 035 .jpg (2); Assembly Code: 23; Assembly Description: Vloeren; Description: Naturoll 035 - 140mm; Manufacturer: Knauf Insulation B.V.; Model: Naturoll 035 is een onbeklede glaswoldeken met ECOSE® Technology; Type Name: NLRS_23_FL_Naturoll 035_140x600x5300mm; URL: www.knaufinsulation.nl
Type - Other - Category: Floors; Family Name: Floor
Type - Pset_ElementShading - Roughness: 304.8 mm
Type - Pset_ManufacturerTypeInformation - Manufacturer: Knauf Insulation B.V.
Type - Pset_ProductRequirements - Category: Floors
Type - Pset_QuantityTakeOff - Reference: NLRS_23_FL_Naturoll 035_140x600x5300mm
Type - Pset_ReinforcementBarPitchOfSlab - Description: Naturoll 035 - 140mm; Reference: NLRS_23_FL_Naturoll 035_140x600x5300mm
Type - Pset_SlabCommon - IsExternal: no; ThermalTransmittance: 0.25 kg/K/s3; Reference: NLRS_23_FL_Naturoll 035_140x600x5300mm
Classification: 23 Vloeren (Uniformat)
Pset_SlabCommon - LoadBearing: no; PitchAngle: 0 deg
BaseQuantities - GrossArea: 2 m2; NetArea: 4.84 m2; GrossVolume: 280 m3; NetVolume: 0.28 m3; Perimeter: 6000 mm; Width: 140 mm
Constraints - Height Offset From Level: 0 mm; Related to Mass: no; Room Bounding: yes; Level: Level: Begane grond
Dimensions - Elevation at Top: 0 mm; Area: 2 m2; Elevation at Bottom: -140 mm; Perimeter: 6000 mm; Thickness: 140 mm; Volume: 0.28 m3
Other - Family: Floor: NLRS_23_FL_Naturoll 035_140x600x5300mm; Family and Type: Floor: NLRS_23_FL_Naturoll 035_140x600x5300mm; Type: Floor: NLRS_23_FL_Naturoll 035_140x600x5300mm; Type Id: Floor: NLRS_23_FL_Naturoll 035_140x600x5300mm
Phasing - Phase Created: New Construction
Structural - Enable Analytical Model: no; Structural: no

# IfcSlab: Floor:NLRS_23_FL_Naturoll 035_170x380x4350mm, Floor:NLRS_23_FL_Naturoll 035_170x380x4350mm:35167
In: Begane grond
Type - PredefinedType: FLOOR; Material: Knauf Insulation_Ecose® glaswol_naturoll 035 170 mm
Type - Analytical Properties - Roughness: 1; Thermal mass: 0; Absorptance: 0.1; Heat Transfer Coefficient (U): 0.205882; Thermal Resistance (R): 4.85714
Type - Construction - Function: Interior; Default Thickness: 170 mm
Type - Graphics - Coarse Scale Fill Color: 0
Type - Identity Data - Type Image: Raster image: Naturoll 035 .jpg (2); Assembly Code: 23; Assembly Description: Vloeren; Description: Naturoll 035 - 170mm; Manufacturer: Knauf Insulation B.V.; Model: Naturoll 035 is een onbeklede glaswoldeken met ECOSE® Technology; Type Name: NLRS_23_FL_Naturoll 035_170x380x4350mm; URL: www.knaufinsulation.nl
Type - Other - Category: Floors; Family Name: Floor
Type - Pset_ElementShading - Roughness: 304.8 mm
Type - Pset_ManufacturerTypeInformation - Manufacturer: Knauf Insulation B.V.
Type - Pset_ProductRequirements - Category: Floors
Type - Pset_QuantityTakeOff - Reference: NLRS_23_FL_Naturoll 035_170x380x4350mm
Type - Pset_ReinforcementBarPitchOfSlab - Description: Naturoll 035 - 170mm; Reference: NLRS_23_FL_Naturoll 035_170x380x4350mm
Type - Pset_SlabCommon - IsExternal: no; Reference: NLRS_23_FL_Naturoll 035_170x380x4350mm; ThermalTransmittance: 0.205882 kg/K/s3
Classification: 23 Vloeren (Uniformat)
Pset_SlabCommon - LoadBearing: no; PitchAngle: 0 deg
BaseQuantities - GrossArea: 2 m2; NetArea: 5.02 m2; GrossVolume: 340 m3; NetVolume: 0.34 m3; Perimeter: 6000 mm; Width: 170 mm
Constraints - Height Offset From Level: 0 mm; Level: Level: Begane grond; Related to Mass: no; Room Bounding: yes
Dimensions - Elevation at Top: 0 mm; Area: 2 m2; Elevation at Bottom: -170 mm; Perimeter: 6000 mm; Thickness: 170 mm; Volume: 0.34 m3
Other - Family: Floor: NLRS_23_FL_Naturoll 035_170x380x4350mm; Family and Type: Floor: NLRS_23_FL_Naturoll 035_170x380x4350mm; Type: Floor: NLRS_23_FL_Naturoll 035_170x380x4350mm; Type Id: Floor: NLRS_23_FL_Naturoll 035_170x380x4350mm
Phasing - Phase Created: New Construction
Structural - Enable Analytical Model: no; Structural: no

# IfcSlab: Floor:NLRS_23_FL_Naturoll 035_170x580x4350mm, Floor:NLRS_23_FL_Naturoll 035_170x580x4350mm:35187
In: Begane grond
Type - PredefinedType: FLOOR; Material: Knauf Insulation_Ecose® glaswol_naturoll 035 170 mm
Type - Analytical Properties - Roughness: 1; Thermal mass: 0; Absorptance: 0.1; Heat Transfer Coefficient (U): 0.205882; Thermal Resistance (R): 4.85714
Type - Construction - Function: Interior; Default Thickness: 170 mm
Type - Graphics - Coarse Scale Fill Color: 0
Type - Identity Data - Type Image: Raster image: Naturoll 035 .jpg (2); Assembly Code: 23; Assembly Description: Vloeren; Description: Naturoll 035 - 170mm; Manufacturer: Knauf Insulation B.V.; Model: Naturoll 035 is een onbeklede glaswoldeken met ECOSE® Technology; Type Name: NLRS_23_FL_Naturoll 035_170x580x4350mm; URL: www.knaufinsulation.nl
Type - Other - Category: Floors; Family Name: Floor
Type - Pset_ElementShading - Roughness: 304.8 mm
Type - Pset_ManufacturerTypeInformation - Manufacturer: Knauf Insulation B.V.
Type - Pset_ProductRequirements - Category: Floors
Type - Pset_QuantityTakeOff - Reference: NLRS_23_FL_Naturoll 035_170x580x4350mm
Type - Pset_ReinforcementBarPitchOfSlab - Description: Naturoll 035 - 170mm; Reference: NLRS_23_FL_Naturoll 035_170x580x4350mm
Type - Pset_SlabCommon - IsExternal: no; Reference: NLRS_23_FL_Naturoll 035_170x580x4350mm; ThermalTransmittance: 0.205882 kg/K/s3
Classification: 23 Vloeren (Uniformat)
Pset_SlabCommon - LoadBearing: no; PitchAngle: 0 deg
BaseQuantities - GrossArea: 2 m2; NetArea: 5.02 m2; GrossVolume: 340 m3; NetVolume: 0.34 m3; Perimeter: 6000 mm; Width: 170 mm
Constraints - Height Offset From Level: 0 mm; Level: Level: Begane grond; Related to Mass: no; Room Bounding: yes
Dimensions - Elevation at Top: 0 mm; Area: 2 m2; Elevation at Bottom: -170 mm; Perimeter: 6000 mm; Thickness: 170 mm; Volume: 0.34 m3
Other - Family: Floor: NLRS_23_FL_Naturoll 035_170x580x4350mm; Family and Type: Floor: NLRS_23_FL_Naturoll 035_170x580x4350mm; Type: Floor: NLRS_23_FL_Naturoll 035_170x580x4350mm; Type Id: Floor: NLRS_23_FL_Naturoll 035_170x580x4350mm
Phasing - Phase Created: New Construction
Structural - Enable Analytical Model: no; Structural: no

# IfcSlab: Floor:NLRS_23_FL_Naturoll 035_185x380x4000mm, Floor:NLRS_23_FL_Naturoll 035_185x380x4000mm:35207
In: Begane grond
Type - PredefinedType: FLOOR; Material: Knauf Insulation_Ecose® glaswol_naturoll 035 185 mm
Type - Analytical Properties - Roughness: 1; Thermal mass: 0; Absorptance: 0.1; Heat Transfer Coefficient (U): 0.189189; Thermal Resistance (R): 5.28571
Type - Construction - Function: Interior; Default Thickness: 185 mm
Type - Graphics - Coarse Scale Fill Color: 0
Type - Identity Data - Type Image: Raster image: Naturoll 035 .jpg (2); Assembly Code: 23; Assembly Description: Vloeren; Description: Naturoll 035 - 185mm; Manufacturer: Knauf Insulation B.V.; Model: Naturoll 035 is een onbeklede glaswoldeken met ECOSE® Technology; Type Name: NLRS_23_FL_Naturoll 035_185x380x4000mm; URL: www.knaufinsulation.nl
Type - Other - Category: Floors; Family Name: Floor
Type - Pset_ElementShading - Roughness: 304.8 mm
Type - Pset_ManufacturerTypeInformation - Manufacturer: Knauf Insulation B.V.
Type - Pset_ProductRequirements - Category: Floors
Type - Pset_QuantityTakeOff - Reference: NLRS_23_FL_Naturoll 035_185x380x4000mm
Type - Pset_ReinforcementBarPitchOfSlab - Description: Naturoll 035 - 185mm; Reference: NLRS_23_FL_Naturoll 035_185x380x4000mm
Type - Pset_SlabCommon - IsExternal: no; Reference: NLRS_23_FL_Naturoll 035_185x380x4000mm; ThermalTransmittance: 0.189189 kg/K/s3
Classification: 23 Vloeren (Uniformat)
Pset_SlabCommon - LoadBearing: no; PitchAngle: 0 deg
BaseQuantities - GrossArea: 2 m2; NetArea: 5.11 m2; GrossVolume: 370 m3; NetVolume: 0.37 m3; Perimeter: 6000 mm; Width: 185 mm
Constraints - Height Offset From Level: 0 mm; Level: Level: Begane grond; Related to Mass: no; Room Bounding: yes
Dimensions - Elevation at Top: 0 mm; Area: 2 m2; Elevation at Bottom: -185 mm; Perimeter: 6000 mm; Thickness: 185 mm; Volume: 0.37 m3
Other - Family: Floor: NLRS_23_FL_Naturoll 035_185x380x4000mm; Family and Type: Floor: NLRS_23_FL_Naturoll 035_185x380x4000mm; Type: Floor: NLRS_23_FL_Naturoll 035_185x380x4000mm; Type Id: Floor: NLRS_23_FL_Naturoll 035_185x380x4000mm
Phasing - Phase Created: New Construction
Structural - Enable Analytical Model: no; Structural: no

# IfcSlab: Floor:NLRS_23_FL_Naturoll 035_185x580x4000mm, Floor:NLRS_23_FL_Naturoll 035_185x580x4000mm:37495
In: Begane grond
Type - PredefinedType: FLOOR; Material: Knauf Insulation_Ecose® glaswol_naturoll 035 185 mm
Type - Analytical Properties - Roughness: 1; Thermal mass: 0; Absorptance: 0.1; Heat Transfer Coefficient (U): 0.189189; Thermal Resistance (R): 5.28571
Type - Construction - Function: Interior; Default Thickness: 185 mm
Type - Graphics - Coarse Scale Fill Color: 0
Type - Identity Data - Type Image: Raster image: Naturoll 035 .jpg (2); Assembly Code: 23; Assembly Description: Vloeren; Description: Naturoll 035 - 185mm; Manufacturer: Knauf Insulation B.V.; Model: Naturoll 035 is een onbeklede glaswoldeken met ECOSE® Technology; Type Name: NLRS_23_FL_Naturoll 035_185x580x4000mm; URL: www.knaufinsulation.nl
Type - Other - Category: Floors; Family Name: Floor
Type - Pset_ElementShading - Roughness: 304.8 mm
Type - Pset_ManufacturerTypeInformation - Manufacturer: Knauf Insulation B.V.
Type - Pset_ProductRequirements - Category: Floors
Type - Pset_QuantityTakeOff - Reference: NLRS_23_FL_Naturoll 035_185x580x4000mm
Type - Pset_ReinforcementBarPitchOfSlab - Description: Naturoll 035 - 185mm; Reference: NLRS_23_FL_Naturoll 035_185x580x4000mm
Type - Pset_SlabCommon - IsExternal: no; Reference: NLRS_23_FL_Naturoll 035_185x580x4000mm; ThermalTransmittance: 0.189189 kg/K/s3
Classification: 23 Vloeren (Uniformat)
Pset_SlabCommon - LoadBearing: no; PitchAngle: 0 deg
BaseQuantities - GrossArea: 2 m2; NetArea: 5.11 m2; GrossVolume: 370 m3; NetVolume: 0.37 m3; Perimeter: 6000 mm; Width: 185 mm
Constraints - Height Offset From Level: 0 mm; Related to Mass: no; Room Bounding: yes; Level: Level: Begane grond
Dimensions - Elevation at Top: 0 mm; Area: 2 m2; Elevation at Bottom: -185 mm; Perimeter: 6000 mm; Thickness: 185 mm; Volume: 0.37 m3
Other - Family: Floor: NLRS_23_FL_Naturoll 035_185x580x4000mm; Family and Type: Floor: NLRS_23_FL_Naturoll 035_185x580x4000mm; Type: Floor: NLRS_23_FL_Naturoll 035_185x580x4000mm; Type Id: Floor: NLRS_23_FL_Naturoll 035_185x580x4000mm
Phasing - Phase Created: New Construction
Structural - Enable Analytical Model: no; Structural: no

# IfcSlab: Floor:NLRS_23_FL_Naturoll 035_195x580x3800mm, Floor:NLRS_23_FL_Naturoll 035_195x580x3800mm:35634
In: Begane grond
Type - PredefinedType: FLOOR; Material: Knauf Insulation_Ecose® glaswol_naturoll 035 195 mm
Type - Analytical Properties - Roughness: 1; Thermal mass: 0; Absorptance: 0.1; Heat Transfer Coefficient (U): 0.179487; Thermal Resistance (R): 5.57143
Type - Construction - Function: Interior; Default Thickness: 195 mm
Type - Graphics - Coarse Scale Fill Color: 0
Type - Identity Data - Type Image: Raster image: Naturoll 035 .jpg (2); Assembly Code: 23; Assembly Description: Vloeren; Description: Naturoll 035 - 195mm; Manufacturer: Knauf Insulation B.V.; Model: Naturoll 035 is een onbeklede glaswoldeken met ECOSE® Technology; Type Name: NLRS_23_FL_Naturoll 035_195x580x3800mm; URL: www.knaufinsulation.nl
Type - Other - Category: Floors; Family Name: Floor
Type - Pset_ElementShading - Roughness: 304.8 mm
Type - Pset_ManufacturerTypeInformation - Manufacturer: Knauf Insulation B.V.
Type - Pset_ProductRequirements - Category: Floors
Type - Pset_QuantityTakeOff - Reference: NLRS_23_FL_Naturoll 035_195x580x3800mm
Type - Pset_ReinforcementBarPitchOfSlab - Description: Naturoll 035 - 195mm; Reference: NLRS_23_FL_Naturoll 035_195x580x3800mm
Type - Pset_SlabCommon - IsExternal: no; Reference: NLRS_23_FL_Naturoll 035_195x580x3800mm; ThermalTransmittance: 0.179487 kg/K/s3
Classification: 23 Vloeren (Uniformat)
Pset_SlabCommon - LoadBearing: no; PitchAngle: 0 deg
BaseQuantities - GrossArea: 2 m2; NetArea: 5.17 m2; GrossVolume: 390 m3; NetVolume: 0.39 m3; Perimeter: 6000 mm; Width: 195 mm
Constraints - Height Offset From Level: 0 mm; Level: Level: Begane grond; Related to Mass: no; Room Bounding: yes
Dimensions - Elevation at Top: 0 mm; Area: 2 m2; Elevation at Bottom: -195 mm; Perimeter: 6000 mm; Thickness: 195 mm; Volume: 0.39 m3
Other - Family: Floor: NLRS_23_FL_Naturoll 035_195x580x3800mm; Family and Type: Floor: NLRS_23_FL_Naturoll 035_195x580x3800mm; Type: Floor: NLRS_23_FL_Naturoll 035_195x580x3800mm; Type Id: Floor: NLRS_23_FL_Naturoll 035_195x580x3800mm
Phasing - Phase Created: New Construction
Structural - Enable Analytical Model: no; Structural: no

# IfcSlab: Floor:NLRS_23_FL_Naturoll 035_200x580x3700mm, Floor:NLRS_23_FL_Naturoll 035_200x580x3700mm:35395
In: Begane grond
Type - PredefinedType: FLOOR; Material: Knauf Insulation_Ecose® glaswol_naturoll 035 200 mm
Type - Analytical Properties - Roughness: 1; Thermal mass: 0; Absorptance: 0.1; Heat Transfer Coefficient (U): 0.175; Thermal Resistance (R): 5.71429
Type - Construction - Function: Interior; Default Thickness: 200 mm
Type - Graphics - Coarse Scale Fill Color: 0
Type - Identity Data - Type Image: Raster image: Naturoll 035 .jpg (2); Assembly Code: 23; Assembly Description: Vloeren; Description: Naturoll 035 - 200mm; Manufacturer: Knauf Insulation B.V.; Model: Naturoll 035 is een onbeklede glaswoldeken met ECOSE® Technology; Type Name: NLRS_23_FL_Naturoll 035_200x580x3700mm; URL: www.knaufinsulation.nl
Type - Other - Category: Floors; Family Name: Floor
Type - Pset_ElementShading - Roughness: 304.8 mm
Type - Pset_ManufacturerTypeInformation - Manufacturer: Knauf Insulation B.V.
Type - Pset_ProductRequirements - Category: Floors
Type - Pset_QuantityTakeOff - Reference: NLRS_23_FL_Naturoll 035_200x580x3700mm
Type - Pset_ReinforcementBarPitchOfSlab - Description: Naturoll 035 - 200mm; Reference: NLRS_23_FL_Naturoll 035_200x580x3700mm
Type - Pset_SlabCommon - IsExternal: no; Reference: NLRS_23_FL_Naturoll 035_200x580x3700mm; ThermalTransmittance: 0.175 kg/K/s3
Classification: 23 Vloeren (Uniformat)
Pset_SlabCommon - LoadBearing: no; PitchAngle: 0 deg
BaseQuantities - GrossArea: 2 m2; NetArea: 5.2 m2; GrossVolume: 400 m3; NetVolume: 0.4 m3; Perimeter: 6000 mm; Width: 200 mm
Constraints - Height Offset From Level: 0 mm; Level: Level: Begane grond; Related to Mass: no; Room Bounding: yes
Dimensions - Elevation at Top: 0 mm; Area: 2 m2; Elevation at Bottom: -200 mm; Perimeter: 6000 mm; Thickness: 200 mm; Volume: 0.4 m3
Other - Family: Floor: NLRS_23_FL_Naturoll 035_200x580x3700mm; Family and Type: Floor: NLRS_23_FL_Naturoll 035_200x580x3700mm; Type: Floor: NLRS_23_FL_Naturoll 035_200x580x3700mm; Type Id: Floor: NLRS_23_FL_Naturoll 035_200x580x3700mm
Phasing - Phase Created: New Construction
Structural - Enable Analytical Model: no; Structural: no

# IfcSlab: Floor:NLRS_23_FL_Naturoll 035_220x380x3400mm, Floor:NLRS_23_FL_Naturoll 035_220x380x3400mm:35414
In: Begane grond
Type - PredefinedType: FLOOR; Material: Knauf Insulation_Ecose® glaswol_naturoll 035 220 mm
Type - Analytical Properties - Roughness: 1; Thermal mass: 0; Absorptance: 0.1; Heat Transfer Coefficient (U): 0.159091; Thermal Resistance (R): 6.28571
Type - Construction - Function: Interior; Default Thickness: 220 mm
Type - Graphics - Coarse Scale Fill Color: 0
Type - Identity Data - Type Image: Raster image: Naturoll 035 .jpg (2); Assembly Code: 23; Assembly Description: Vloeren; Description: Naturoll 035 - 220mm; Manufacturer: Knauf Insulation B.V.; Model: Naturoll 035 is een onbeklede glaswoldeken met ECOSE® Technology; Type Name: NLRS_23_FL_Naturoll 035_220x380x3400mm; URL: www.knaufinsulation.nl
Type - Other - Category: Floors; Family Name: Floor
Type - Pset_ElementShading - Roughness: 304.8 mm
Type - Pset_ManufacturerTypeInformation - Manufacturer: Knauf Insulation B.V.
Type - Pset_ProductRequirements - Category: Floors
Type - Pset_QuantityTakeOff - Reference: NLRS_23_FL_Naturoll 035_220x380x3400mm
Type - Pset_ReinforcementBarPitchOfSlab - Description: Naturoll 035 - 220mm; Reference: NLRS_23_FL_Naturoll 035_220x380x3400mm
Type - Pset_SlabCommon - IsExternal: no; Reference: NLRS_23_FL_Naturoll 035_220x380x3400mm; ThermalTransmittance: 0.159091 kg/K/s3
Classification: 23 Vloeren (Uniformat)
Pset_SlabCommon - LoadBearing: no; PitchAngle: 0 deg
BaseQuantities - GrossArea: 2 m2; NetArea: 5.32 m2; GrossVolume: 440 m3; NetVolume: 0.44 m3; Perimeter: 6000 mm; Width: 220 mm
Constraints - Height Offset From Level: 0 mm; Level: Level: Begane grond; Related to Mass: no; Room Bounding: yes
Dimensions - Elevation at Top: 0 mm; Area: 2 m2; Elevation at Bottom: -220 mm; Perimeter: 6000 mm; Thickness: 220 mm; Volume: 0.44 m3
Other - Family: Floor: NLRS_23_FL_Naturoll 035_220x380x3400mm; Family and Type: Floor: NLRS_23_FL_Naturoll 035_220x380x3400mm; Type: Floor: NLRS_23_FL_Naturoll 035_220x380x3400mm; Type Id: Floor: NLRS_23_FL_Naturoll 035_220x380x3400mm
Phasing - Phase Created: New Construction
Structural - Enable Analytical Model: no; Structural: no

# IfcSlab: Floor:NLRS_23_FL_Naturoll 035_220x580x3400mm, Floor:NLRS_23_FL_Naturoll 035_220x580x3400mm:35433
In: Begane grond
Type - PredefinedType: FLOOR; Material: Knauf Insulation_Ecose® glaswol_naturoll 035 220 mm
Type - Analytical Properties - Roughness: 1; Thermal mass: 0; Absorptance: 0.1; Heat Transfer Coefficient (U): 0.159091; Thermal Resistance (R): 6.28571
Type - Construction - Function: Interior; Default Thickness: 220 mm
Type - Graphics - Coarse Scale Fill Color: 0
Type - Identity Data - Type Image: Raster image: Naturoll 035 .jpg (2); Assembly Code: 23; Assembly Description: Vloeren; Description: Naturoll 035 - 220mm; Manufacturer: Knauf Insulation B.V.; Model: Naturoll 035 is een onbeklede glaswoldeken met ECOSE® Technology; Type Name: NLRS_23_FL_Naturoll 035_220x580x3400mm; URL: www.knaufinsulation.nl
Type - Other - Category: Floors; Family Name: Floor
Type - Pset_ElementShading - Roughness: 304.8 mm
Type - Pset_ManufacturerTypeInformation - Manufacturer: Knauf Insulation B.V.
Type - Pset_ProductRequirements - Category: Floors
Type - Pset_QuantityTakeOff - Reference: NLRS_23_FL_Naturoll 035_220x580x3400mm
Type - Pset_ReinforcementBarPitchOfSlab - Description: Naturoll 035 - 220mm; Reference: NLRS_23_FL_Naturoll 035_220x580x3400mm
Type - Pset_SlabCommon - IsExternal: no; Reference: NLRS_23_FL_Naturoll 035_220x580x3400mm; ThermalTransmittance: 0.159091 kg/K/s3
Classification: 23 Vloeren (Uniformat)
Pset_SlabCommon - LoadBearing: no; PitchAngle: 0 deg
BaseQuantities - GrossArea: 2 m2; NetArea: 5.32 m2; GrossVolume: 440 m3; NetVolume: 0.44 m3; Perimeter: 6000 mm; Width: 220 mm
Constraints - Height Offset From Level: 0 mm; Related to Mass: no; Room Bounding: yes; Level: Level: Begane grond
Dimensions - Elevation at Top: 0 mm; Area: 2 m2; Elevation at Bottom: -220 mm; Perimeter: 6000 mm; Thickness: 220 mm; Volume: 0.44 m3
Other - Family: Floor: NLRS_23_FL_Naturoll 035_220x580x3400mm; Family and Type: Floor: NLRS_23_FL_Naturoll 035_220x580x3400mm; Type: Floor: NLRS_23_FL_Naturoll 035_220x580x3400mm; Type Id: Floor: NLRS_23_FL_Naturoll 035_220x580x3400mm
Phasing - Phase Created: New Construction
Structural - Enable Analytical Model: no; Structural: no

# IfcSlab: Floor:NLRS_23_FL_Naturoll 035_235x580x3100mm, Floor:NLRS_23_FL_Naturoll 035_235x580x3100mm:35452
In: Begane grond
Type - PredefinedType: FLOOR; Material: Knauf Insulation_Ecose® glaswol_naturoll 035 235 mm
Type - Analytical Properties - Roughness: 1; Thermal mass: 0; Absorptance: 0.1; Heat Transfer Coefficient (U): 0.148936; Thermal Resistance (R): 6.71429
Type - Construction - Function: Interior; Default Thickness: 235 mm
Type - Graphics - Coarse Scale Fill Color: 0
Type - Identity Data - Type Image: Raster image: Naturoll 035 .jpg (2); Assembly Code: 23; Assembly Description: Vloeren; Description: Naturoll 035 - 235mm; Manufacturer: Knauf Insulation B.V.; Model: Naturoll 035 is een onbeklede glaswoldeken met ECOSE® Technology; Type Name: NLRS_23_FL_Naturoll 035_235x580x3100mm; URL: www.knaufinsulation.nl
Type - Other - Category: Floors; Family Name: Floor
Type - Pset_ElementShading - Roughness: 304.8 mm
Type - Pset_ManufacturerTypeInformation - Manufacturer: Knauf Insulation B.V.
Type - Pset_ProductRequirements - Category: Floors
Type - Pset_QuantityTakeOff - Reference: NLRS_23_FL_Naturoll 035_235x580x3100mm
Type - Pset_ReinforcementBarPitchOfSlab - Description: Naturoll 035 - 235mm; Reference: NLRS_23_FL_Naturoll 035_235x580x3100mm
Type - Pset_SlabCommon - IsExternal: no; Reference: NLRS_23_FL_Naturoll 035_235x580x3100mm; ThermalTransmittance: 0.148936 kg/K/s3
Classification: 23 Vloeren (Uniformat)
Pset_SlabCommon - LoadBearing: no; PitchAngle: 0 deg
BaseQuantities - GrossArea: 2 m2; NetArea: 5.41 m2; GrossVolume: 470 m3; NetVolume: 0.47 m3; Perimeter: 6000 mm; Width: 235 mm
Constraints - Height Offset From Level: 0 mm; Level: Level: Begane grond; Related to Mass: no; Room Bounding: yes
Dimensions - Elevation at Top: 0 mm; Area: 2 m2; Elevation at Bottom: -235 mm; Perimeter: 6000 mm; Thickness: 235 mm; Volume: 0.47 m3
Other - Family: Floor: NLRS_23_FL_Naturoll 035_235x580x3100mm; Family and Type: Floor: NLRS_23_FL_Naturoll 035_235x580x3100mm; Type: Floor: NLRS_23_FL_Naturoll 035_235x580x3100mm; Type Id: Floor: NLRS_23_FL_Naturoll 035_235x580x3100mm
Phasing - Phase Created: New Construction
Structural - Enable Analytical Model: no; Structural: no

# IfcSlab: Floor:NLRS_23_FL_Naturoll 035_240x580x3100mm, Floor:NLRS_23_FL_Naturoll 035_240x580x3100mm:35471
In: Begane grond
Type - PredefinedType: FLOOR; Material: Knauf Insulation_Ecose® glaswol_naturoll 035 240 mm
Type - Analytical Properties - Roughness: 1; Thermal mass: 0; Absorptance: 0.1; Heat Transfer Coefficient (U): 0.145833; Thermal Resistance (R): 6.85714
Type - Construction - Function: Interior; Default Thickness: 240 mm
Type - Graphics - Coarse Scale Fill Color: 0
Type - Identity Data - Type Image: Raster image: Naturoll 035 .jpg (2); Assembly Code: 23; Assembly Description: Vloeren; Description: Naturoll 035 - 240mm; Manufacturer: Knauf Insulation B.V.; Model: Naturoll 035 is een onbeklede glaswoldeken met ECOSE® Technology; Type Name: NLRS_23_FL_Naturoll 035_240x580x3100mm; URL: www.knaufinsulation.nl
Type - Other - Category: Floors; Family Name: Floor
Type - Pset_ElementShading - Roughness: 304.8 mm
Type - Pset_ManufacturerTypeInformation - Manufacturer: Knauf Insulation B.V.
Type - Pset_ProductRequirements - Category: Floors
Type - Pset_QuantityTakeOff - Reference: NLRS_23_FL_Naturoll 035_240x580x3100mm
Type - Pset_ReinforcementBarPitchOfSlab - Description: Naturoll 035 - 240mm; Reference: NLRS_23_FL_Naturoll 035_240x580x3100mm
Type - Pset_SlabCommon - IsExternal: no; Reference: NLRS_23_FL_Naturoll 035_240x580x3100mm; ThermalTransmittance: 0.145833 kg/K/s3
Classification: 23 Vloeren (Uniformat)
Pset_SlabCommon - LoadBearing: no; PitchAngle: 0 deg
BaseQuantities - GrossArea: 2 m2; NetArea: 5.44 m2; GrossVolume: 480 m3; NetVolume: 0.48 m3; Perimeter: 6000 mm; Width: 240 mm
Constraints - Height Offset From Level: 0 mm; Level: Level: Begane grond; Related to Mass: no; Room Bounding: yes
Dimensions - Elevation at Top: 0 mm; Area: 2 m2; Elevation at Bottom: -240 mm; Perimeter: 6000 mm; Thickness: 240 mm; Volume: 0.48 m3
Other - Family: Floor: NLRS_23_FL_Naturoll 035_240x580x3100mm; Family and Type: Floor: NLRS_23_FL_Naturoll 035_240x580x3100mm; Type: Floor: NLRS_23_FL_Naturoll 035_240x580x3100mm; Type Id: Floor: NLRS_23_FL_Naturoll 035_240x580x3100mm
Phasing - Phase Created: New Construction
Structural - Enable Analytical Model: no; Structural: no

# IfcSlab: Floor:NLRS_23_FL_Naturoll 035_270x590x3100mm, Floor:NLRS_23_FL_Naturoll 035_270x590x3100mm:35490
In: Begane grond
Type - PredefinedType: FLOOR; Material: Knauf Insulation_Ecose® glaswol_naturoll 035 270 mm
Type - Analytical Properties - Roughness: 1; Thermal mass: 0; Absorptance: 0.1; Heat Transfer Coefficient (U): 0.12963; Thermal Resistance (R): 7.71429
Type - Construction - Function: Interior; Default Thickness: 270 mm
Type - Graphics - Coarse Scale Fill Color: 0
Type - Identity Data - Type Image: Raster image: Naturoll 035 .jpg (2); Assembly Code: 23; Assembly Description: Vloeren; Description: Naturoll 035 - 270mm; Manufacturer: Knauf Insulation B.V.; Model: Naturoll 035 is een onbeklede glaswoldeken met ECOSE® Technology; Type Name: NLRS_23_FL_Naturoll 035_270x590x3100mm; URL: www.knaufinsulation.nl
Type - Other - Category: Floors; Family Name: Floor
Type - Pset_ElementShading - Roughness: 304.8 mm
Type - Pset_ManufacturerTypeInformation - Manufacturer: Knauf Insulation B.V.
Type - Pset_ProductRequirements - Category: Floors
Type - Pset_QuantityTakeOff - Reference: NLRS_23_FL_Naturoll 035_270x590x3100mm
Type - Pset_ReinforcementBarPitchOfSlab - Description: Naturoll 035 - 270mm; Reference: NLRS_23_FL_Naturoll 035_270x590x3100mm
Type - Pset_SlabCommon - IsExternal: no; Reference: NLRS_23_FL_Naturoll 035_270x590x3100mm; ThermalTransmittance: 0.12963 kg/K/s3
Classification: 23 Vloeren (Uniformat)
Pset_SlabCommon - LoadBearing: no; PitchAngle: 0 deg
BaseQuantities - GrossArea: 2 m2; NetArea: 5.62 m2; GrossVolume: 540 m3; NetVolume: 0.54 m3; Perimeter: 6000 mm; Width: 270 mm
Constraints - Height Offset From Level: 0 mm; Level: Level: Begane grond; Related to Mass: no; Room Bounding: yes
Dimensions - Elevation at Top: 0 mm; Area: 2 m2; Elevation at Bottom: -270 mm; Perimeter: 6000 mm; Thickness: 270 mm; Volume: 0.54 m3
Other - Family: Floor: NLRS_23_FL_Naturoll 035_270x590x3100mm; Family and Type: Floor: NLRS_23_FL_Naturoll 035_270x590x3100mm; Type: Floor: NLRS_23_FL_Naturoll 035_270x590x3100mm; Type Id: Floor: NLRS_23_FL_Naturoll 035_270x590x3100mm
Phasing - Phase Created: New Construction
Structural - Enable Analytical Model: no; Structural: no

# IfcSlab: Floor:NLRS_23_FL_Naturoll 035_90x380x7600mm, Floor:NLRS_23_FL_Naturoll 035_90x380x7600mm:33541
In: Begane grond
Type - PredefinedType: FLOOR; Material: Knauf Insulation_Ecose® glaswol_naturoll 035 90 mm
Type - Analytical Properties - Absorptance: 0.1; Heat Transfer Coefficient (U): 0.388889; Roughness: 1; Thermal mass: 0; Thermal Resistance (R): 2.57143
Type - Construction - Default Thickness: 90 mm; Function: Interior
Type - Graphics - Coarse Scale Fill Color: 0
Type - Identity Data - Assembly Code: 23; Assembly Description: Vloeren; Description: Naturoll 035 - 90mm; Manufacturer: Knauf Insulation B.V.; Model: Naturoll 035 is een onbeklede glaswoldeken met ECOSE® Technology; Type Image: Raster image: Naturoll 035 .jpg (2); Type Name: NLRS_23_FL_Naturoll 035_90x380x7600mm; URL: www.knaufinsulation.nl
Type - Other - Category: Floors; Family Name: Floor
Type - Pset_ElementShading - Roughness: 304.8 mm
Type - Pset_ManufacturerTypeInformation - Manufacturer: Knauf Insulation B.V.
Type - Pset_ProductRequirements - Category: Floors
Type - Pset_QuantityTakeOff - Reference: NLRS_23_FL_Naturoll 035_90x380x7600mm
Type - Pset_ReinforcementBarPitchOfSlab - Description: Naturoll 035 - 90mm; Reference: NLRS_23_FL_Naturoll 035_90x380x7600mm
Type - Pset_SlabCommon - Reference: NLRS_23_FL_Naturoll 035_90x380x7600mm; IsExternal: no; ThermalTransmittance: 0.388889 kg/K/s3
Classification: 23 Vloeren (Uniformat)
Pset_SlabCommon - LoadBearing: no; PitchAngle: 0 deg
BaseQuantities - GrossArea: 2 m2; NetArea: 4.54 m2; GrossVolume: 180 m3; NetVolume: 0.18 m3; Perimeter: 6000 mm; Width: 90 mm
Constraints - Height Offset From Level: 0 mm; Level: Level: Begane grond; Related to Mass: no; Room Bounding: yes
Dimensions - Area: 2 m2; Elevation at Bottom: -90 mm; Elevation at Top: 0 mm; Perimeter: 6000 mm; Thickness: 90 mm; Volume: 0.18 m3
Other - Family: Floor: NLRS_23_FL_Naturoll 035_90x380x7600mm; Family and Type: Floor: NLRS_23_FL_Naturoll 035_90x380x7600mm; Type: Floor: NLRS_23_FL_Naturoll 035_90x380x7600mm; Type Id: Floor: NLRS_23_FL_Naturoll 035_90x380x7600mm
Phasing - Phase Created: New Construction
Structural - Enable Analytical Model: no; Structural: no

# IfcSlab: Floor:NLRS_23_FL_Naturoll 035_90x580x7600mm, Floor:NLRS_23_FL_Naturoll 035_90x580x7600mm:34911
In: Begane grond
Type - PredefinedType: FLOOR; Material: Knauf Insulation_Ecose® glaswol_naturoll 035 90 mm
Type - Analytical Properties - Roughness: 1; Thermal mass: 0; Absorptance: 0.1; Heat Transfer Coefficient (U): 0.388889; Thermal Resistance (R): 2.57143
Type - Construction - Function: Interior; Default Thickness: 90 mm
Type - Graphics - Coarse Scale Fill Color: 0
Type - Identity Data - Type Image: Raster image: Naturoll 035 .jpg (2); Assembly Code: 23; Assembly Description: Vloeren; Description: Naturoll 035 - 90mm; Manufacturer: Knauf Insulation B.V.; Model: Naturoll 035 is een onbeklede glaswoldeken met ECOSE® Technology; Type Name: NLRS_23_FL_Naturoll 035_90x580x7600mm; URL: www.knaufinsulation.nl
Type - Other - Category: Floors; Family Name: Floor
Type - Pset_ElementShading - Roughness: 304.8 mm
Type - Pset_ManufacturerTypeInformation - Manufacturer: Knauf Insulation B.V.
Type - Pset_ProductRequirements - Category: Floors
Type - Pset_QuantityTakeOff - Reference: NLRS_23_FL_Naturoll 035_90x580x7600mm
Type - Pset_ReinforcementBarPitchOfSlab - Description: Naturoll 035 - 90mm; Reference: NLRS_23_FL_Naturoll 035_90x580x7600mm
Type - Pset_SlabCommon - IsExternal: no; Reference: NLRS_23_FL_Naturoll 035_90x580x7600mm; ThermalTransmittance: 0.388889 kg/K/s3
Classification: 23 Vloeren (Uniformat)
Pset_SlabCommon - LoadBearing: no; PitchAngle: 0 deg
BaseQuantities - GrossArea: 2 m2; NetArea: 4.54 m2; GrossVolume: 180 m3; NetVolume: 0.18 m3; Perimeter: 6000 mm; Width: 90 mm
Constraints - Height Offset From Level: 0 mm; Level: Level: Begane grond; Related to Mass: no; Room Bounding: yes
Dimensions - Elevation at Top: 0 mm; Area: 2 m2; Elevation at Bottom: -90 mm; Perimeter: 6000 mm; Thickness: 90 mm; Volume: 0.18 m3
Other - Family: Floor: NLRS_23_FL_Naturoll 035_90x580x7600mm; Family and Type: Floor: NLRS_23_FL_Naturoll 035_90x580x7600mm; Type: Floor: NLRS_23_FL_Naturoll 035_90x580x7600mm; Type Id: Floor: NLRS_23_FL_Naturoll 035_90x580x7600mm
Phasing - Phase Created: New Construction
Structural - Enable Analytical Model: no; Structural: no

# IfcWallStandardCase: Basic Wall:NLRS_21_WA_Naturoll 035_100x580x7400mm (2)
In: Begane grond
Type - PredefinedType: STANDARD; Material: Knauf Insulation_Ecose® glaswol_naturoll 035 100 mm
Type - Analytical Properties - Roughness: 1; Thermal mass: 0; Absorptance: 0.1; Heat Transfer Coefficient (U): 0.35; Thermal Resistance (R): 2.85714
Type - Construction - Function: Exterior; Wrapping at Inserts: Do not wrap; Width: 100 mm
Type - Graphics - Coarse Scale Fill Color: 0
Type - Identity Data - Type Image: Raster image: Naturoll 035 .jpg (2); Assembly Code: 21; Assembly Description: Buitenwanden; Description: Naturoll 035 - 100mm; Manufacturer: Knauf Insulation B.V.; Model: Naturoll 035 is een onbeklede glaswoldeken met ECOSE® Technology; Type Name: NLRS_21_WA_Naturoll 035_100x580x7400mm; URL: www.knaufinsulation.nl
Type - Other - Category: Walls; Family Name: Basic Wall
Type - Pset_ElementShading - Roughness: 304.8 mm
Type - Pset_ManufacturerTypeInformation - Manufacturer: Knauf Insulation B.V.
Type - Pset_ProductRequirements - Category: Walls
Type - Pset_QuantityTakeOff - Reference: NLRS_21_WA_Naturoll 035_100x580x7400mm
Type - Pset_ReinforcementBarPitchOfWall - Description: Naturoll 035 - 100mm; Reference: NLRS_21_WA_Naturoll 035_100x580x7400mm
Type - Pset_WallCommon - IsExternal: no; ThermalTransmittance: 0.35 kg/K/s3; Reference: NLRS_21_WA_Naturoll 035_100x580x7400mm
Classification: 21 Buitenwanden (Uniformat)
BaseQuantities - Height: 2500 mm; Width: 100 mm
Constraints - Related to Mass: no; Room Bounding: yes; Base Constraint: Level: Begane grond; Base Extension Distance: 0 mm; Base is Attached: no; Base Offset: 0 mm; Top Constraint: Level: Lengte; Top Extension Distance: 0 mm; Top is Attached: no; Top Offset: 0 mm; Unconnected Height: 2500 mm
Other - Family: Basic Wall: NLRS_21_WA_Naturoll 035_100x580x7400mm; Family and Type: Basic Wall: NLRS_21_WA_Naturoll 035_100x580x7400mm; Type: Basic Wall: NLRS_21_WA_Naturoll 035_100x580x7400mm; Type Id: Basic Wall: NLRS_21_WA_Naturoll 035_100x580x7400mm
Phasing - Phase Created: New Construction
Structural - Enable Analytical Model: no; Structural: no; Structural Usage: Non-bearing
Pset_WallCommon - LoadBearing: no; IsExternal: yes; ExtendToStructure: no
Name (Basic Wall:NLRS_21_WA_Naturoll 035_100x580x7400mm:...) | BaseQuantities, Length (mm) = Dimensions, Length (mm) | GrossFootprintArea (m2) | NetVolume (m3) | NetSideArea (m2) | Location Line | Area (m2) | Volume (m3)
34996 | 2000 | 0.2 | 500000000 | 5000000 | Core Face: Interior | 5 | 0.5
34998 | 1000 | 0.1 | 250000000 | 2500000 | Wall Centerline | 2.5 | 0.25

# IfcWallStandardCase: Basic Wall:NLRS_21_WA_Naturoll 035_120x380x6200mm (2)
In: Begane grond
Type - PredefinedType: STANDARD; Material: Knauf Insulation_Ecose® glaswol_naturoll 035 120 mm
Type - Analytical Properties - Roughness: 1; Thermal mass: 0; Absorptance: 0.1; Heat Transfer Coefficient (U): 0.291667; Thermal Resistance (R): 3.42857
Type - Construction - Function: Exterior; Wrapping at Inserts: Do not wrap; Width: 120 mm
Type - Graphics - Coarse Scale Fill Color: 0
Type - Identity Data - Type Image: Raster image: Naturoll 035 .jpg (2); Assembly Code: 21; Assembly Description: Buitenwanden; Description: Naturoll 035 - 120mm; Manufacturer: Knauf Insulation B.V.; Model: Naturoll 035 is een onbeklede glaswoldeken met ECOSE® Technology; Type Name: NLRS_21_WA_Naturoll 035_120x380x6200mm; URL: www.knaufinsulation.nl
Type - Other - Category: Walls; Family Name: Basic Wall
Type - Pset_ElementShading - Roughness: 304.8 mm
Type - Pset_ManufacturerTypeInformation - Manufacturer: Knauf Insulation B.V.
Type - Pset_ProductRequirements - Category: Walls
Type - Pset_QuantityTakeOff - Reference: NLRS_21_WA_Naturoll 035_120x380x6200mm
Type - Pset_ReinforcementBarPitchOfWall - Description: Naturoll 035 - 120mm; Reference: NLRS_21_WA_Naturoll 035_120x380x6200mm
Type - Pset_WallCommon - IsExternal: no; Reference: NLRS_21_WA_Naturoll 035_120x380x6200mm; ThermalTransmittance: 0.291667 kg/K/s3
Classification: 21 Buitenwanden (Uniformat)
BaseQuantities - Height: 2500 mm; Width: 120 mm
Constraints - Related to Mass: no; Room Bounding: yes; Base Constraint: Level: Begane grond; Base Extension Distance: 0 mm; Base is Attached: no; Base Offset: 0 mm; Top Constraint: Level: Lengte; Top Extension Distance: 0 mm; Top is Attached: no; Top Offset: 0 mm; Unconnected Height: 2500 mm
Other - Family: Basic Wall: NLRS_21_WA_Naturoll 035_120x380x6200mm; Family and Type: Basic Wall: NLRS_21_WA_Naturoll 035_120x380x6200mm; Type: Basic Wall: NLRS_21_WA_Naturoll 035_120x380x6200mm; Type Id: Basic Wall: NLRS_21_WA_Naturoll 035_120x380x6200mm
Phasing - Phase Created: New Construction
Structural - Enable Analytical Model: no; Structural: no; Structural Usage: Non-bearing
Pset_WallCommon - LoadBearing: no; IsExternal: yes; ExtendToStructure: no
Name (Basic Wall:NLRS_21_WA_Naturoll 035_120x380x6200mm:...) | BaseQuantities, Length (mm) = Dimensions, Length (mm) | GrossFootprintArea (m2) | NetVolume (m3) | NetSideArea (m2) | Location Line | Area (m2) | Volume (m3)
35018 | 2000 | 0.24 | 600000000 | 5000000 | Core Face: Interior | 5 | 0.6
35020 | 1000 | 0.12 | 300000000 | 2500000 | Wall Centerline | 2.5 | 0.3

# IfcWallStandardCase: Basic Wall:NLRS_21_WA_Naturoll 035_120x580x6200mm (2)
In: Begane grond
Type - PredefinedType: STANDARD; Material: Knauf Insulation_Ecose® glaswol_naturoll 035 120 mm
Type - Analytical Properties - Roughness: 1; Thermal mass: 0; Absorptance: 0.1; Heat Transfer Coefficient (U): 0.291667; Thermal Resistance (R): 3.42857
Type - Construction - Function: Exterior; Wrapping at Inserts: Do not wrap; Width: 120 mm
Type - Graphics - Coarse Scale Fill Color: 0
Type - Identity Data - Type Image: Raster image: Naturoll 035 .jpg (2); Assembly Code: 21; Assembly Description: Buitenwanden; Description: Naturoll 035 - 120mm; Manufacturer: Knauf Insulation B.V.; Model: Naturoll 035 is een onbeklede glaswoldeken met ECOSE® Technology; Type Name: NLRS_21_WA_Naturoll 035_120x580x6200mm; URL: www.knaufinsulation.nl
Type - Other - Category: Walls; Family Name: Basic Wall
Type - Pset_ElementShading - Roughness: 304.8 mm
Type - Pset_ManufacturerTypeInformation - Manufacturer: Knauf Insulation B.V.
Type - Pset_ProductRequirements - Category: Walls
Type - Pset_QuantityTakeOff - Reference: NLRS_21_WA_Naturoll 035_120x580x6200mm
Type - Pset_ReinforcementBarPitchOfWall - Description: Naturoll 035 - 120mm; Reference: NLRS_21_WA_Naturoll 035_120x580x6200mm
Type - Pset_WallCommon - IsExternal: no; Reference: NLRS_21_WA_Naturoll 035_120x580x6200mm; ThermalTransmittance: 0.291667 kg/K/s3
Classification: 21 Buitenwanden (Uniformat)
BaseQuantities - Height: 2500 mm; Width: 120 mm
Constraints - Related to Mass: no; Room Bounding: yes; Base Constraint: Level: Begane grond; Base Extension Distance: 0 mm; Base is Attached: no; Base Offset: 0 mm; Top Constraint: Level: Lengte; Top Extension Distance: 0 mm; Top is Attached: no; Top Offset: 0 mm; Unconnected Height: 2500 mm
Other - Family: Basic Wall: NLRS_21_WA_Naturoll 035_120x580x6200mm; Family and Type: Basic Wall: NLRS_21_WA_Naturoll 035_120x580x6200mm; Type: Basic Wall: NLRS_21_WA_Naturoll 035_120x580x6200mm; Type Id: Basic Wall: NLRS_21_WA_Naturoll 035_120x580x6200mm
Phasing - Phase Created: New Construction
Structural - Enable Analytical Model: no; Structural: no; Structural Usage: Non-bearing
Pset_WallCommon - LoadBearing: no; IsExternal: yes; ExtendToStructure: no
Name (Basic Wall:NLRS_21_WA_Naturoll 035_120x580x6200mm:...) | BaseQuantities, Length (mm) = Dimensions, Length (mm) | GrossFootprintArea (m2) | NetVolume (m3) | NetSideArea (m2) | Location Line | Area (m2) | Volume (m3)
35040 | 2000 | 0.24 | 600000000 | 5000000 | Core Face: Interior | 5 | 0.6
35042 | 1000 | 0.12 | 300000000 | 2500000 | Wall Centerline | 2.5 | 0.3

# IfcWallStandardCase: Basic Wall:NLRS_21_WA_Naturoll 035_130x590x5500mm (2)
In: Begane grond
Type - PredefinedType: STANDARD; Material: Knauf Insulation_Ecose® glaswol_naturoll 035 130 mm
Type - Analytical Properties - Roughness: 1; Thermal mass: 0; Absorptance: 0.1; Heat Transfer Coefficient (U): 0.269231; Thermal Resistance (R): 3.71429
Type - Construction - Function: Exterior; Wrapping at Inserts: Do not wrap; Width: 130 mm
Type - Graphics - Coarse Scale Fill Color: 0
Type - Identity Data - Type Image: Raster image: Naturoll 035 .jpg (2); Assembly Code: 21; Assembly Description: Buitenwanden; Description: Naturoll 035 - 130mm; Manufacturer: Knauf Insulation B.V.; Model: Naturoll 035 is een onbeklede glaswoldeken met ECOSE® Technology; Type Name: NLRS_21_WA_Naturoll 035_130x590x5500mm; URL: www.knaufinsulation.nl
Type - Other - Category: Walls; Family Name: Basic Wall
Type - Pset_ElementShading - Roughness: 304.8 mm
Type - Pset_ManufacturerTypeInformation - Manufacturer: Knauf Insulation B.V.
Type - Pset_ProductRequirements - Category: Walls
Type - Pset_QuantityTakeOff - Reference: NLRS_21_WA_Naturoll 035_130x590x5500mm
Type - Pset_ReinforcementBarPitchOfWall - Description: Naturoll 035 - 130mm; Reference: NLRS_21_WA_Naturoll 035_130x590x5500mm
Type - Pset_WallCommon - IsExternal: no; Reference: NLRS_21_WA_Naturoll 035_130x590x5500mm; ThermalTransmittance: 0.269231 kg/K/s3
Classification: 21 Buitenwanden (Uniformat)
BaseQuantities - Height: 2500 mm; Width: 130 mm
Constraints - Related to Mass: no; Room Bounding: yes; Base Constraint: Level: Begane grond; Base Extension Distance: 0 mm; Base is Attached: no; Base Offset: 0 mm; Top Constraint: Level: Lengte; Top Extension Distance: 0 mm; Top is Attached: no; Top Offset: 0 mm; Unconnected Height: 2500 mm
Other - Family: Basic Wall: NLRS_21_WA_Naturoll 035_130x590x5500mm; Family and Type: Basic Wall: NLRS_21_WA_Naturoll 035_130x590x5500mm; Type: Basic Wall: NLRS_21_WA_Naturoll 035_130x590x5500mm; Type Id: Basic Wall: NLRS_21_WA_Naturoll 035_130x590x5500mm
Phasing - Phase Created: New Construction
Structural - Enable Analytical Model: no; Structural: no; Structural Usage: Non-bearing
Pset_WallCommon - LoadBearing: no; IsExternal: yes; ExtendToStructure: no
Name (Basic Wall:NLRS_21_WA_Naturoll 035_130x590x5500mm:...) | BaseQuantities, Length (mm) = Dimensions, Length (mm) | GrossFootprintArea (m2) | NetVolume (m3) | NetSideArea (m2) | Location Line | Area (m2) | Volume (m3)
35062 | 2000 | 0.26 | 650000000 | 5000000 | Core Face: Interior | 5 | 0.65
35064 | 1000 | 0.13 | 325000000 | 2500000 | Wall Centerline | 2.5 | 0.325

# IfcWallStandardCase: Basic Wall:NLRS_21_WA_Naturoll 035_140x380x5300mm (2)
In: Begane grond
Type - PredefinedType: STANDARD; Material: Knauf Insulation_Ecose® glaswol_naturoll 035 140 mm
Type - Analytical Properties - Roughness: 1; Thermal mass: 0; Thermal Resistance (R): 4; Absorptance: 0.1; Heat Transfer Coefficient (U): 0.25
Type - Construction - Function: Exterior; Wrapping at Inserts: Do not wrap; Width: 140 mm
Type - Graphics - Coarse Scale Fill Color: 0
Type - Identity Data - Type Image: Raster image: Naturoll 035 .jpg (2); Assembly Code: 21; Assembly Description: Buitenwanden; Description: Naturoll 035 - 140mm; Manufacturer: Knauf Insulation B.V.; Model: Naturoll 035 is een onbeklede glaswoldeken met ECOSE® Technology; Type Name: NLRS_21_WA_Naturoll 035_140x380x5300mm; URL: www.knaufinsulation.nl
Type - Other - Category: Walls; Family Name: Basic Wall
Type - Pset_ElementShading - Roughness: 304.8 mm
Type - Pset_ManufacturerTypeInformation - Manufacturer: Knauf Insulation B.V.
Type - Pset_ProductRequirements - Category: Walls
Type - Pset_QuantityTakeOff - Reference: NLRS_21_WA_Naturoll 035_140x380x5300mm
Type - Pset_ReinforcementBarPitchOfWall - Description: Naturoll 035 - 140mm; Reference: NLRS_21_WA_Naturoll 035_140x380x5300mm
Type - Pset_WallCommon - IsExternal: no; ThermalTransmittance: 0.25 kg/K/s3; Reference: NLRS_21_WA_Naturoll 035_140x380x5300mm
Classification: 21 Buitenwanden (Uniformat)
BaseQuantities - Height: 2500 mm; Width: 140 mm
Constraints - Related to Mass: no; Room Bounding: yes; Base Constraint: Level: Begane grond; Base Extension Distance: 0 mm; Base is Attached: no; Base Offset: 0 mm; Top Constraint: Level: Lengte; Top Extension Distance: 0 mm; Top is Attached: no; Top Offset: 0 mm; Unconnected Height: 2500 mm
Other - Family: Basic Wall: NLRS_21_WA_Naturoll 035_140x380x5300mm; Family and Type: Basic Wall: NLRS_21_WA_Naturoll 035_140x380x5300mm; Type: Basic Wall: NLRS_21_WA_Naturoll 035_140x380x5300mm; Type Id: Basic Wall: NLRS_21_WA_Naturoll 035_140x380x5300mm
Phasing - Phase Created: New Construction
Structural - Enable Analytical Model: no; Structural: no; Structural Usage: Non-bearing
Pset_WallCommon - LoadBearing: no; IsExternal: yes; ExtendToStructure: no
Name (Basic Wall:NLRS_21_WA_Naturoll 035_140x380x5300mm:...) | BaseQuantities, Length (mm) = Dimensions, Length (mm) | GrossFootprintArea (m2) | NetVolume (m3) | NetSideArea (m2) | Location Line | Area (m2) | Volume (m3)
35112 | 2000 | 0.28 | 700000000 | 5000000 | Core Face: Interior | 5 | 0.7
35114 | 1000 | 0.14 | 350000000 | 2500000 | Wall Centerline | 2.5 | 0.35

# IfcWallStandardCase: Basic Wall:NLRS_21_WA_Naturoll 035_140x580x5300mm (2)
In: Begane grond
Type - PredefinedType: STANDARD; Material: Knauf Insulation_Ecose® glaswol_naturoll 035 140 mm
Type - Analytical Properties - Roughness: 1; Thermal mass: 0; Thermal Resistance (R): 4; Absorptance: 0.1; Heat Transfer Coefficient (U): 0.25
Type - Construction - Function: Exterior; Wrapping at Inserts: Do not wrap; Width: 140 mm
Type - Graphics - Coarse Scale Fill Color: 0
Type - Identity Data - Type Image: Raster image: Naturoll 035 .jpg (2); Assembly Code: 21; Assembly Description: Buitenwanden; Description: Naturoll 035 - 140mm; Manufacturer: Knauf Insulation B.V.; Model: Naturoll 035 is een onbeklede glaswoldeken met ECOSE® Technology; Type Name: NLRS_21_WA_Naturoll 035_140x580x5300mm; URL: www.knaufinsulation.nl
Type - Other - Category: Walls; Family Name: Basic Wall
Type - Pset_ElementShading - Roughness: 304.8 mm
Type - Pset_ManufacturerTypeInformation - Manufacturer: Knauf Insulation B.V.
Type - Pset_ProductRequirements - Category: Walls
Type - Pset_QuantityTakeOff - Reference: NLRS_21_WA_Naturoll 035_140x580x5300mm
Type - Pset_ReinforcementBarPitchOfWall - Description: Naturoll 035 - 140mm; Reference: NLRS_21_WA_Naturoll 035_140x580x5300mm
Type - Pset_WallCommon - IsExternal: no; ThermalTransmittance: 0.25 kg/K/s3; Reference: NLRS_21_WA_Naturoll 035_140x580x5300mm
Classification: 21 Buitenwanden (Uniformat)
BaseQuantities - Height: 2500 mm; Width: 140 mm
Constraints - Related to Mass: no; Room Bounding: yes; Base Constraint: Level: Begane grond; Base Extension Distance: 0 mm; Base is Attached: no; Base Offset: 0 mm; Top Constraint: Level: Lengte; Top Extension Distance: 0 mm; Top is Attached: no; Top Offset: 0 mm; Unconnected Height: 2500 mm
Other - Family: Basic Wall: NLRS_21_WA_Naturoll 035_140x580x5300mm; Family and Type: Basic Wall: NLRS_21_WA_Naturoll 035_140x580x5300mm; Type: Basic Wall: NLRS_21_WA_Naturoll 035_140x580x5300mm; Type Id: Basic Wall: NLRS_21_WA_Naturoll 035_140x580x5300mm
Phasing - Phase Created: New Construction
Structural - Enable Analytical Model: no; Structural: no; Structural Usage: Non-bearing
Pset_WallCommon - LoadBearing: no; IsExternal: yes; ExtendToStructure: no
Name (Basic Wall:NLRS_21_WA_Naturoll 035_140x580x5300mm:...) | BaseQuantities, Length (mm) = Dimensions, Length (mm) | GrossFootprintArea (m2) | NetVolume (m3) | NetSideArea (m2) | Location Line | Area (m2) | Volume (m3)
35132 | 2000 | 0.28 | 700000000 | 5000000 | Core Face: Interior | 5 | 0.7
35134 | 1000 | 0.14 | 350000000 | 2500000 | Wall Centerline | 2.5 | 0.35

# IfcWallStandardCase: Basic Wall:NLRS_21_WA_Naturoll 035_140x600x5300mm (2)
In: Begane grond
Type - PredefinedType: STANDARD; Material: Knauf Insulation_Ecose® glaswol_naturoll 035 140 mm
Type - Analytical Properties - Roughness: 1; Thermal mass: 0; Thermal Resistance (R): 4; Absorptance: 0.1; Heat Transfer Coefficient (U): 0.25
Type - Construction - Function: Exterior; Wrapping at Inserts: Do not wrap; Width: 140 mm
Type - Graphics - Coarse Scale Fill Color: 0
Type - Identity Data - Type Image: Raster image: Naturoll 035 .jpg (2); Assembly Code: 21; Assembly Description: Buitenwanden; Description: Naturoll 035 - 140mm; Manufacturer: Knauf Insulation B.V.; Model: Naturoll 035 is een onbeklede glaswoldeken met ECOSE® Technology; Type Name: NLRS_21_WA_Naturoll 035_140x600x5300mm; URL: www.knaufinsulation.nl
Type - Other - Category: Walls; Family Name: Basic Wall
Type - Pset_ElementShading - Roughness: 304.8 mm
Type - Pset_ManufacturerTypeInformation - Manufacturer: Knauf Insulation B.V.
Type - Pset_ProductRequirements - Category: Walls
Type - Pset_QuantityTakeOff - Reference: NLRS_21_WA_Naturoll 035_140x600x5300mm
Type - Pset_ReinforcementBarPitchOfWall - Description: Naturoll 035 - 140mm; Reference: NLRS_21_WA_Naturoll 035_140x600x5300mm
Type - Pset_WallCommon - IsExternal: no; ThermalTransmittance: 0.25 kg/K/s3; Reference: NLRS_21_WA_Naturoll 035_140x600x5300mm
Classification: 21 Buitenwanden (Uniformat)
BaseQuantities - Height: 2500 mm; Width: 140 mm
Constraints - Related to Mass: no; Room Bounding: yes; Base Constraint: Level: Begane grond; Base Extension Distance: 0 mm; Base is Attached: no; Base Offset: 0 mm; Top Constraint: Level: Lengte; Top Extension Distance: 0 mm; Top is Attached: no; Top Offset: 0 mm; Unconnected Height: 2500 mm
Other - Family: Basic Wall: NLRS_21_WA_Naturoll 035_140x600x5300mm; Family and Type: Basic Wall: NLRS_21_WA_Naturoll 035_140x600x5300mm; Type: Basic Wall: NLRS_21_WA_Naturoll 035_140x600x5300mm; Type Id: Basic Wall: NLRS_21_WA_Naturoll 035_140x600x5300mm
Phasing - Phase Created: New Construction
Structural - Enable Analytical Model: no; Structural: no; Structural Usage: Non-bearing
Pset_WallCommon - LoadBearing: no; IsExternal: yes; ExtendToStructure: no
Name (Basic Wall:NLRS_21_WA_Naturoll 035_140x600x5300mm:...) | BaseQuantities, Length (mm) = Dimensions, Length (mm) | GrossFootprintArea (m2) | NetVolume (m3) | NetSideArea (m2) | Location Line | Area (m2) | Volume (m3)
35152 | 2000 | 0.28 | 700000000 | 5000000 | Core Face: Interior | 5 | 0.7
35154 | 1000 | 0.14 | 350000000 | 2500000 | Wall Centerline | 2.5 | 0.35

# IfcWallStandardCase: Basic Wall:NLRS_21_WA_Naturoll 035_170x380x4350mm (2)
In: Begane grond
Type - PredefinedType: STANDARD; Material: Knauf Insulation_Ecose® glaswol_naturoll 035 170 mm
Type - Analytical Properties - Roughness: 1; Thermal mass: 0; Absorptance: 0.1; Heat Transfer Coefficient (U): 0.205882; Thermal Resistance (R): 4.85714
Type - Construction - Function: Exterior; Wrapping at Inserts: Do not wrap; Width: 170 mm
Type - Graphics - Coarse Scale Fill Color: 0
Type - Identity Data - Type Image: Raster image: Naturoll 035 .jpg (2); Assembly Code: 21; Assembly Description: Buitenwanden; Description: Naturoll 035 - 170mm; Manufacturer: Knauf Insulation B.V.; Model: Naturoll 035 is een onbeklede glaswoldeken met ECOSE® Technology; Type Name: NLRS_21_WA_Naturoll 035_170x380x4350mm; URL: www.knaufinsulation.nl
Type - Other - Category: Walls; Family Name: Basic Wall
Type - Pset_ElementShading - Roughness: 304.8 mm
Type - Pset_ManufacturerTypeInformation - Manufacturer: Knauf Insulation B.V.
Type - Pset_ProductRequirements - Category: Walls
Type - Pset_QuantityTakeOff - Reference: NLRS_21_WA_Naturoll 035_170x380x4350mm
Type - Pset_ReinforcementBarPitchOfWall - Description: Naturoll 035 - 170mm; Reference: NLRS_21_WA_Naturoll 035_170x380x4350mm
Type - Pset_WallCommon - IsExternal: no; Reference: NLRS_21_WA_Naturoll 035_170x380x4350mm; ThermalTransmittance: 0.205882 kg/K/s3
Classification: 21 Buitenwanden (Uniformat)
BaseQuantities - Height: 2500 mm; Width: 170 mm
Constraints - Related to Mass: no; Room Bounding: yes; Base Constraint: Level: Begane grond; Base Extension Distance: 0 mm; Base is Attached: no; Base Offset: 0 mm; Top Constraint: Level: Lengte; Top Extension Distance: 0 mm; Top is Attached: no; Top Offset: 0 mm; Unconnected Height: 2500 mm
Other - Family: Basic Wall: NLRS_21_WA_Naturoll 035_170x380x4350mm; Family and Type: Basic Wall: NLRS_21_WA_Naturoll 035_170x380x4350mm; Type: Basic Wall: NLRS_21_WA_Naturoll 035_170x380x4350mm; Type Id: Basic Wall: NLRS_21_WA_Naturoll 035_170x380x4350mm
Phasing - Phase Created: New Construction
Structural - Enable Analytical Model: no; Structural: no; Structural Usage: Non-bearing
Pset_WallCommon - LoadBearing: no; IsExternal: yes; ExtendToStructure: no
Name (Basic Wall:NLRS_21_WA_Naturoll 035_170x380x4350mm:...) | BaseQuantities, Length (mm) = Dimensions, Length (mm) | GrossFootprintArea (m2) | NetVolume (m3) | NetSideArea (m2) | Location Line | Area (m2) | Volume (m3)
35172 | 2000 | 0.34 | 850000000 | 5000000 | Core Face: Interior | 5 | 0.85
35174 | 1000 | 0.17 | 425000000 | 2500000 | Wall Centerline | 2.5 | 0.425

# IfcWallStandardCase: Basic Wall:NLRS_21_WA_Naturoll 035_170x580x4350mm (2)
In: Begane grond
Type - PredefinedType: STANDARD; Material: Knauf Insulation_Ecose® glaswol_naturoll 035 170 mm
Type - Analytical Properties - Roughness: 1; Thermal mass: 0; Absorptance: 0.1; Heat Transfer Coefficient (U): 0.205882; Thermal Resistance (R): 4.85714
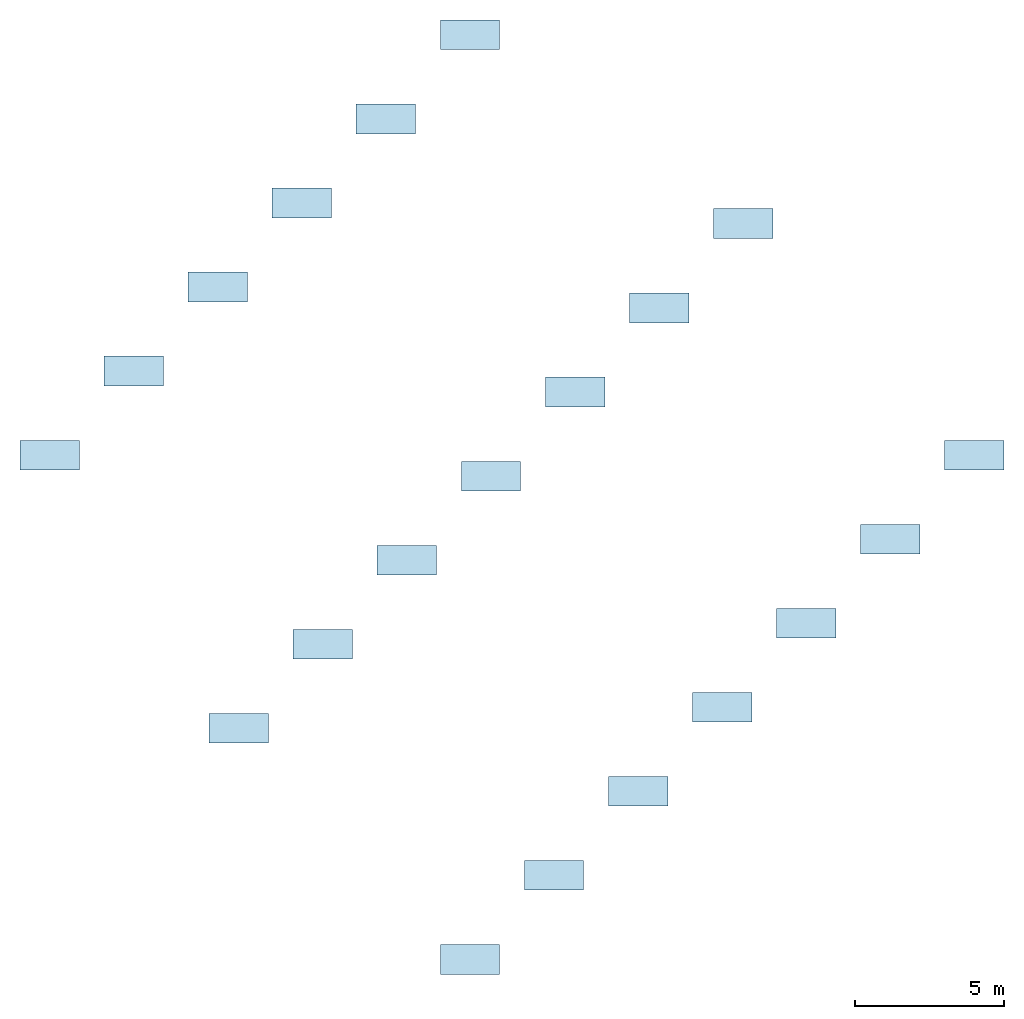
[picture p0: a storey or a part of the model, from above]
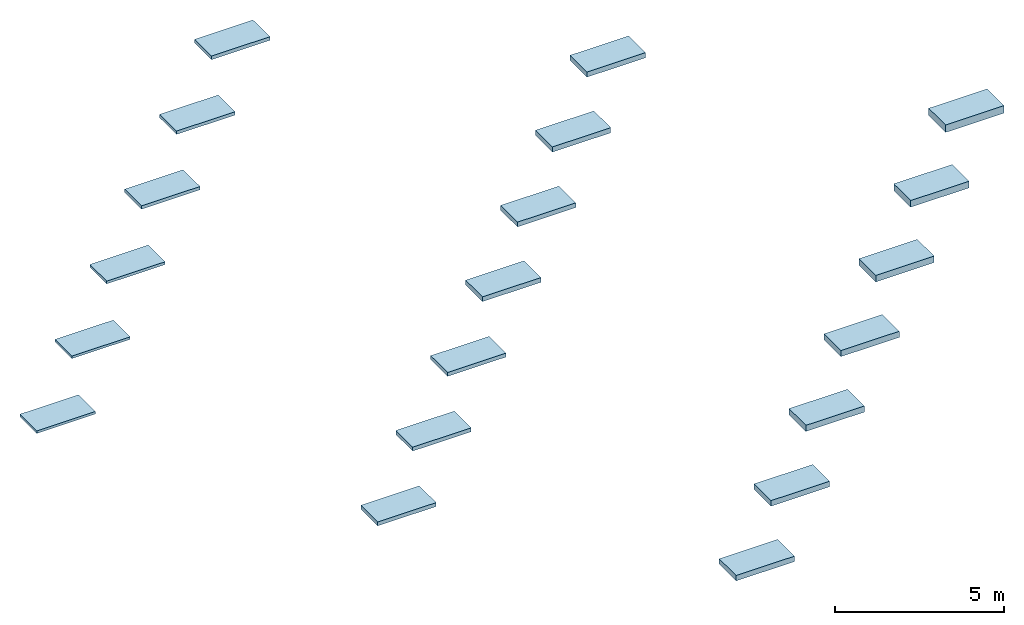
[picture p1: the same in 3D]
Properties of the parts of a building model (IFC2X3), part 3 of 3

# IfcWallStandardCase: Basic Wall:NLRS_21_WA_Naturoll 035_170x580x4350mm (2)
Type - Construction - Function: Exterior; Wrapping at Inserts: Do not wrap; Width: 170 mm
Type - Graphics - Coarse Scale Fill Color: 0
Type - Identity Data - Type Image: Raster image: Naturoll 035 .jpg (2); Assembly Code: 21; Assembly Description: Buitenwanden; Description: Naturoll 035 - 170mm; Manufacturer: Knauf Insulation B.V.; Model: Naturoll 035 is een onbeklede glaswoldeken met ECOSE® Technology; Type Name: NLRS_21_WA_Naturoll 035_170x580x4350mm; URL: www.knaufinsulation.nl
Type - Other - Category: Walls; Family Name: Basic Wall
Type - Pset_ElementShading - Roughness: 304.8 mm
Type - Pset_ManufacturerTypeInformation - Manufacturer: Knauf Insulation B.V.
Type - Pset_ProductRequirements - Category: Walls
Type - Pset_QuantityTakeOff - Reference: NLRS_21_WA_Naturoll 035_170x580x4350mm
Type - Pset_ReinforcementBarPitchOfWall - Description: Naturoll 035 - 170mm; Reference: NLRS_21_WA_Naturoll 035_170x580x4350mm
Type - Pset_WallCommon - IsExternal: no; Reference: NLRS_21_WA_Naturoll 035_170x580x4350mm; ThermalTransmittance: 0.205882 kg/K/s3
Classification: 21 Buitenwanden (Uniformat)
BaseQuantities - Height: 2500 mm; Width: 170 mm
Constraints - Related to Mass: no; Room Bounding: yes; Base Constraint: Level: Begane grond; Base Extension Distance: 0 mm; Base is Attached: no; Base Offset: 0 mm; Top Constraint: Level: Lengte; Top Extension Distance: 0 mm; Top is Attached: no; Top Offset: 0 mm; Unconnected Height: 2500 mm
Other - Family: Basic Wall: NLRS_21_WA_Naturoll 035_170x580x4350mm; Family and Type: Basic Wall: NLRS_21_WA_Naturoll 035_170x580x4350mm; Type: Basic Wall: NLRS_21_WA_Naturoll 035_170x580x4350mm; Type Id: Basic Wall: NLRS_21_WA_Naturoll 035_170x580x4350mm
Phasing - Phase Created: New Construction
Structural - Enable Analytical Model: no; Structural: no; Structural Usage: Non-bearing
Pset_WallCommon - LoadBearing: no; IsExternal: yes; ExtendToStructure: no
Name (Basic Wall:NLRS_21_WA_Naturoll 035_170x580x4350mm:...) | BaseQuantities, Length (mm) = Dimensions, Length (mm) | GrossFootprintArea (m2) | NetVolume (m3) | NetSideArea (m2) | Location Line | Area (m2) | Volume (m3)
35192 | 2000 | 0.34 | 850000000 | 5000000 | Core Face: Interior | 5 | 0.85
35194 | 1000 | 0.17 | 425000000 | 2500000 | Wall Centerline | 2.5 | 0.425

# IfcWallStandardCase: Basic Wall:NLRS_21_WA_Naturoll 035_185x380x4000mm (2)
In: Begane grond
Type - PredefinedType: STANDARD; Material: Knauf Insulation_Ecose® glaswol_naturoll 035 185 mm
Type - Analytical Properties - Roughness: 1; Thermal mass: 0; Absorptance: 0.1; Heat Transfer Coefficient (U): 0.189189; Thermal Resistance (R): 5.28571
Type - Construction - Function: Exterior; Wrapping at Inserts: Do not wrap; Width: 185 mm
Type - Graphics - Coarse Scale Fill Color: 0
Type - Identity Data - Type Image: Raster image: Naturoll 035 .jpg (2); Assembly Code: 21; Assembly Description: Buitenwanden; Description: Naturoll 035 - 185mm; Manufacturer: Knauf Insulation B.V.; Model: Naturoll 035 is een onbeklede glaswoldeken met ECOSE® Technology; Type Name: NLRS_21_WA_Naturoll 035_185x380x4000mm; URL: www.knaufinsulation.nl
Type - Other - Category: Walls; Family Name: Basic Wall
Type - Pset_ElementShading - Roughness: 304.8 mm
Type - Pset_ManufacturerTypeInformation - Manufacturer: Knauf Insulation B.V.
Type - Pset_ProductRequirements - Category: Walls
Type - Pset_QuantityTakeOff - Reference: NLRS_21_WA_Naturoll 035_185x380x4000mm
Type - Pset_ReinforcementBarPitchOfWall - Description: Naturoll 035 - 185mm; Reference: NLRS_21_WA_Naturoll 035_185x380x4000mm
Type - Pset_WallCommon - IsExternal: no; Reference: NLRS_21_WA_Naturoll 035_185x380x4000mm; ThermalTransmittance: 0.189189 kg/K/s3
Classification: 21 Buitenwanden (Uniformat)
BaseQuantities - Height: 2500 mm; Width: 185 mm
Constraints - Related to Mass: no; Room Bounding: yes; Base Constraint: Level: Begane grond; Base Extension Distance: 0 mm; Base is Attached: no; Base Offset: 0 mm; Top Constraint: Level: Lengte; Top Extension Distance: 0 mm; Top is Attached: no; Top Offset: 0 mm; Unconnected Height: 2500 mm
Other - Family: Basic Wall: NLRS_21_WA_Naturoll 035_185x380x4000mm; Family and Type: Basic Wall: NLRS_21_WA_Naturoll 035_185x380x4000mm; Type: Basic Wall: NLRS_21_WA_Naturoll 035_185x380x4000mm; Type Id: Basic Wall: NLRS_21_WA_Naturoll 035_185x380x4000mm
Phasing - Phase Created: New Construction
Structural - Enable Analytical Model: no; Structural: no; Structural Usage: Non-bearing
Pset_WallCommon - LoadBearing: no; IsExternal: yes; ExtendToStructure: no
Name (Basic Wall:NLRS_21_WA_Naturoll 035_185x380x4000mm:...) | BaseQuantities, Length (mm) = Dimensions, Length (mm) | GrossFootprintArea (m2) | NetVolume (m3) | NetSideArea (m2) | Location Line | Area (m2) | Volume (m3)
35212 | 2000 | 0.37 | 925000000 | 5000000 | Core Face: Interior | 5 | 0.925
35214 | 1000 | 0.185 | 462500000 | 2500000 | Wall Centerline | 2.5 | 0.4625

# IfcWallStandardCase: Basic Wall:NLRS_21_WA_Naturoll 035_185x580x4000mm (2)
In: Begane grond
Type - PredefinedType: STANDARD; Material: Knauf Insulation_Ecose® glaswol_naturoll 035 185 mm
Type - Analytical Properties - Roughness: 1; Thermal mass: 0; Absorptance: 0.1; Heat Transfer Coefficient (U): 0.189189; Thermal Resistance (R): 5.28571
Type - Construction - Function: Exterior; Wrapping at Inserts: Do not wrap; Width: 185 mm
Type - Graphics - Coarse Scale Fill Color: 0
Type - Identity Data - Type Image: Raster image: Naturoll 035 .jpg (2); Assembly Code: 21; Assembly Description: Buitenwanden; Description: Naturoll 035 - 185mm; Manufacturer: Knauf Insulation B.V.; Model: Naturoll 035 is een onbeklede glaswoldeken met ECOSE® Technology; Type Name: NLRS_21_WA_Naturoll 035_185x580x4000mm; URL: www.knaufinsulation.nl
Type - Other - Category: Walls; Family Name: Basic Wall
Type - Pset_ElementShading - Roughness: 304.8 mm
Type - Pset_ManufacturerTypeInformation - Manufacturer: Knauf Insulation B.V.
Type - Pset_ProductRequirements - Category: Walls
Type - Pset_QuantityTakeOff - Reference: NLRS_21_WA_Naturoll 035_185x580x4000mm
Type - Pset_ReinforcementBarPitchOfWall - Description: Naturoll 035 - 185mm; Reference: NLRS_21_WA_Naturoll 035_185x580x4000mm
Type - Pset_WallCommon - IsExternal: no; Reference: NLRS_21_WA_Naturoll 035_185x580x4000mm; ThermalTransmittance: 0.189189 kg/K/s3
Classification: 21 Buitenwanden (Uniformat)
BaseQuantities - Height: 2500 mm; Width: 185 mm
Constraints - Related to Mass: no; Room Bounding: yes; Base Constraint: Level: Begane grond; Base Extension Distance: 0 mm; Base is Attached: no; Base Offset: 0 mm; Top Constraint: Level: Lengte; Top Extension Distance: 0 mm; Top is Attached: no; Top Offset: 0 mm; Unconnected Height: 2500 mm
Other - Family: Basic Wall: NLRS_21_WA_Naturoll 035_185x580x4000mm; Family and Type: Basic Wall: NLRS_21_WA_Naturoll 035_185x580x4000mm; Type: Basic Wall: NLRS_21_WA_Naturoll 035_185x580x4000mm; Type Id: Basic Wall: NLRS_21_WA_Naturoll 035_185x580x4000mm
Phasing - Phase Created: New Construction
Structural - Enable Analytical Model: no; Structural: no; Structural Usage: Non-bearing
Pset_WallCommon - LoadBearing: no; IsExternal: yes; ExtendToStructure: no
Name (Basic Wall:NLRS_21_WA_Naturoll 035_185x580x4000mm:...) | BaseQuantities, Length (mm) = Dimensions, Length (mm) | GrossFootprintArea (m2) | NetVolume (m3) | NetSideArea (m2) | Location Line | Area (m2) | Volume (m3)
37500 | 2000 | 0.37 | 925000000 | 5000000 | Core Face: Interior | 5 | 0.925
37502 | 1000 | 0.185 | 462500000 | 2500000 | Wall Centerline | 2.5 | 0.4625

# IfcWallStandardCase: Basic Wall:NLRS_21_WA_Naturoll 035_195x580x3800mm (2)
In: Begane grond
Type - PredefinedType: STANDARD; Material: Knauf Insulation_Ecose® glaswol_naturoll 035 195 mm
Type - Analytical Properties - Roughness: 1; Thermal mass: 0; Absorptance: 0.1; Heat Transfer Coefficient (U): 0.179487; Thermal Resistance (R): 5.57143
Type - Construction - Function: Exterior; Wrapping at Inserts: Do not wrap; Width: 195 mm
Type - Graphics - Coarse Scale Fill Color: 0
Type - Identity Data - Type Image: Raster image: Naturoll 035 .jpg (2); Assembly Code: 21; Assembly Description: Buitenwanden; Description: Naturoll 035 - 195mm; Manufacturer: Knauf Insulation B.V.; Model: Naturoll 035 is een onbeklede glaswoldeken met ECOSE® Technology; Type Name: NLRS_21_WA_Naturoll 035_195x580x3800mm; URL: www.knaufinsulation.nl
Type - Other - Category: Walls; Family Name: Basic Wall
Type - Pset_ElementShading - Roughness: 304.8 mm
Type - Pset_ManufacturerTypeInformation - Manufacturer: Knauf Insulation B.V.
Type - Pset_ProductRequirements - Category: Walls
Type - Pset_QuantityTakeOff - Reference: NLRS_21_WA_Naturoll 035_195x580x3800mm
Type - Pset_ReinforcementBarPitchOfWall - Description: Naturoll 035 - 195mm; Reference: NLRS_21_WA_Naturoll 035_195x580x3800mm
Type - Pset_WallCommon - IsExternal: no; Reference: NLRS_21_WA_Naturoll 035_195x580x3800mm; ThermalTransmittance: 0.179487 kg/K/s3
Classification: 21 Buitenwanden (Uniformat)
BaseQuantities - Height: 2500 mm; Width: 195 mm
Constraints - Related to Mass: no; Room Bounding: yes; Base Constraint: Level: Begane grond; Base Extension Distance: 0 mm; Base is Attached: no; Base Offset: 0 mm; Top Constraint: Level: Lengte; Top Extension Distance: 0 mm; Top is Attached: no; Top Offset: 0 mm; Unconnected Height: 2500 mm
Other - Family: Basic Wall: NLRS_21_WA_Naturoll 035_195x580x3800mm; Family and Type: Basic Wall: NLRS_21_WA_Naturoll 035_195x580x3800mm; Type: Basic Wall: NLRS_21_WA_Naturoll 035_195x580x3800mm; Type Id: Basic Wall: NLRS_21_WA_Naturoll 035_195x580x3800mm
Phasing - Phase Created: New Construction
Structural - Enable Analytical Model: no; Structural: no; Structural Usage: Non-bearing
Pset_WallCommon - LoadBearing: no; IsExternal: yes; ExtendToStructure: no
Name (Basic Wall:NLRS_21_WA_Naturoll 035_195x580x3800mm:...) | BaseQuantities, Length (mm) = Dimensions, Length (mm) | GrossFootprintArea (m2) | NetVolume (m3) | NetSideArea (m2) | Location Line | Area (m2) | Volume (m3)
35639 | 2000 | 0.39 | 975000000 | 5000000 | Core Face: Interior | 5 | 0.975
35641 | 1000 | 0.195 | 487500000 | 2500000 | Wall Centerline | 2.5 | 0.4875

# IfcWallStandardCase: Basic Wall:NLRS_21_WA_Naturoll 035_200x580x3700mm (2)
In: Begane grond
Type - PredefinedType: STANDARD; Material: Knauf Insulation_Ecose® glaswol_naturoll 035 200 mm
Type - Analytical Properties - Roughness: 1; Thermal mass: 0; Absorptance: 0.1; Heat Transfer Coefficient (U): 0.175; Thermal Resistance (R): 5.71429
Type - Construction - Function: Exterior; Wrapping at Inserts: Do not wrap; Width: 200 mm
Type - Graphics - Coarse Scale Fill Color: 0
Type - Identity Data - Type Image: Raster image: Naturoll 035 .jpg (2); Assembly Code: 21; Assembly Description: Buitenwanden; Description: Naturoll 035 - 200mm; Manufacturer: Knauf Insulation B.V.; Model: Naturoll 035 is een onbeklede glaswoldeken met ECOSE® Technology; Type Name: NLRS_21_WA_Naturoll 035_200x580x3700mm; URL: www.knaufinsulation.nl
Type - Other - Category: Walls; Family Name: Basic Wall
Type - Pset_ElementShading - Roughness: 304.8 mm
Type - Pset_ManufacturerTypeInformation - Manufacturer: Knauf Insulation B.V.
Type - Pset_ProductRequirements - Category: Walls
Type - Pset_QuantityTakeOff - Reference: NLRS_21_WA_Naturoll 035_200x580x3700mm
Type - Pset_ReinforcementBarPitchOfWall - Description: Naturoll 035 - 200mm; Reference: NLRS_21_WA_Naturoll 035_200x580x3700mm
Type - Pset_WallCommon - IsExternal: no; Reference: NLRS_21_WA_Naturoll 035_200x580x3700mm; ThermalTransmittance: 0.175 kg/K/s3
Classification: 21 Buitenwanden (Uniformat)
BaseQuantities - Height: 2500 mm; Width: 200 mm
Constraints - Related to Mass: no; Room Bounding: yes; Base Constraint: Level: Begane grond; Base Extension Distance: 0 mm; Base is Attached: no; Base Offset: 0 mm; Top Constraint: Level: Lengte; Top Extension Distance: 0 mm; Top is Attached: no; Top Offset: 0 mm; Unconnected Height: 2500 mm
Other - Family: Basic Wall: NLRS_21_WA_Naturoll 035_200x580x3700mm; Family and Type: Basic Wall: NLRS_21_WA_Naturoll 035_200x580x3700mm; Type: Basic Wall: NLRS_21_WA_Naturoll 035_200x580x3700mm; Type Id: Basic Wall: NLRS_21_WA_Naturoll 035_200x580x3700mm
Phasing - Phase Created: New Construction
Structural - Enable Analytical Model: no; Structural: no; Structural Usage: Non-bearing
Pset_WallCommon - LoadBearing: no; IsExternal: yes; ExtendToStructure: no
Name (Basic Wall:NLRS_21_WA_Naturoll 035_200x580x3700mm:...) | BaseQuantities, Length (mm) = Dimensions, Length (mm) | GrossFootprintArea (m2) | NetVolume (m3) | NetSideArea (m2) | Location Line | Area (m2) | Volume (m3)
35400 | 2000 | 0.4 | 1000000000 | 5000000 | Core Face: Interior | 5 | 1
35402 | 1000 | 0.2 | 500000000 | 2500000 | Wall Centerline | 2.5 | 0.5

# IfcWallStandardCase: Basic Wall:NLRS_21_WA_Naturoll 035_220x380x3400mm (2)
In: Begane grond
Type - PredefinedType: STANDARD; Material: Knauf Insulation_Ecose® glaswol_naturoll 035 220 mm
Type - Analytical Properties - Roughness: 1; Thermal mass: 0; Absorptance: 0.1; Heat Transfer Coefficient (U): 0.159091; Thermal Resistance (R): 6.28571
Type - Construction - Function: Exterior; Wrapping at Inserts: Do not wrap; Width: 220 mm
Type - Graphics - Coarse Scale Fill Color: 0
Type - Identity Data - Type Image: Raster image: Naturoll 035 .jpg (2); Assembly Code: 21; Assembly Description: Buitenwanden; Description: Naturoll 035 - 220mm; Manufacturer: Knauf Insulation B.V.; Model: Naturoll 035 is een onbeklede glaswoldeken met ECOSE® Technology; Type Name: NLRS_21_WA_Naturoll 035_220x380x3400mm; URL: www.knaufinsulation.nl
Type - Other - Category: Walls; Family Name: Basic Wall
Type - Pset_ElementShading - Roughness: 304.8 mm
Type - Pset_ManufacturerTypeInformation - Manufacturer: Knauf Insulation B.V.
Type - Pset_ProductRequirements - Category: Walls
Type - Pset_QuantityTakeOff - Reference: NLRS_21_WA_Naturoll 035_220x380x3400mm
Type - Pset_ReinforcementBarPitchOfWall - Description: Naturoll 035 - 220mm; Reference: NLRS_21_WA_Naturoll 035_220x380x3400mm
Type - Pset_WallCommon - IsExternal: no; Reference: NLRS_21_WA_Naturoll 035_220x380x3400mm; ThermalTransmittance: 0.159091 kg/K/s3
Classification: 21 Buitenwanden (Uniformat)
BaseQuantities - Height: 2500 mm; Width: 220 mm
Constraints - Related to Mass: no; Room Bounding: yes; Base Constraint: Level: Begane grond; Base Extension Distance: 0 mm; Base is Attached: no; Base Offset: 0 mm; Top Constraint: Level: Lengte; Top Extension Distance: 0 mm; Top is Attached: no; Top Offset: 0 mm; Unconnected Height: 2500 mm
Other - Family: Basic Wall: NLRS_21_WA_Naturoll 035_220x380x3400mm; Family and Type: Basic Wall: NLRS_21_WA_Naturoll 035_220x380x3400mm; Type: Basic Wall: NLRS_21_WA_Naturoll 035_220x380x3400mm; Type Id: Basic Wall: NLRS_21_WA_Naturoll 035_220x380x3400mm
Phasing - Phase Created: New Construction
Structural - Enable Analytical Model: no; Structural: no; Structural Usage: Non-bearing
Pset_WallCommon - LoadBearing: no; IsExternal: yes; ExtendToStructure: no
Name (Basic Wall:NLRS_21_WA_Naturoll 035_220x380x3400mm:...) | BaseQuantities, Length (mm) = Dimensions, Length (mm) | GrossFootprintArea (m2) | NetVolume (m3) | NetSideArea (m2) | Location Line | Area (m2) | Volume (m3)
35419 | 2000 | 0.44 | 1100000000 | 5000000 | Core Face: Interior | 5 | 1.1
35421 | 1000 | 0.22 | 550000000 | 2500000 | Wall Centerline | 2.5 | 0.55

# IfcWallStandardCase: Basic Wall:NLRS_21_WA_Naturoll 035_220x580x3400mm (2)
In: Begane grond
Type - PredefinedType: STANDARD; Material: Knauf Insulation_Ecose® glaswol_naturoll 035 220 mm
Type - Analytical Properties - Roughness: 1; Thermal mass: 0; Absorptance: 0.1; Heat Transfer Coefficient (U): 0.159091; Thermal Resistance (R): 6.28571
Type - Construction - Function: Exterior; Wrapping at Inserts: Do not wrap; Width: 220 mm
Type - Graphics - Coarse Scale Fill Color: 0
Type - Identity Data - Type Image: Raster image: Naturoll 035 .jpg (2); Assembly Code: 21; Assembly Description: Buitenwanden; Description: Naturoll 035 - 220mm; Manufacturer: Knauf Insulation B.V.; Model: Naturoll 035 is een onbeklede glaswoldeken met ECOSE® Technology; Type Name: NLRS_21_WA_Naturoll 035_220x580x3400mm; URL: www.knaufinsulation.nl
Type - Other - Category: Walls; Family Name: Basic Wall
Type - Pset_ElementShading - Roughness: 304.8 mm
Type - Pset_ManufacturerTypeInformation - Manufacturer: Knauf Insulation B.V.
Type - Pset_ProductRequirements - Category: Walls
Type - Pset_QuantityTakeOff - Reference: NLRS_21_WA_Naturoll 035_220x580x3400mm
Type - Pset_ReinforcementBarPitchOfWall - Description: Naturoll 035 - 220mm; Reference: NLRS_21_WA_Naturoll 035_220x580x3400mm
Type - Pset_WallCommon - IsExternal: no; Reference: NLRS_21_WA_Naturoll 035_220x580x3400mm; ThermalTransmittance: 0.159091 kg/K/s3
Classification: 21 Buitenwanden (Uniformat)
BaseQuantities - Height: 2500 mm; Width: 220 mm
Constraints - Related to Mass: no; Room Bounding: yes; Base Constraint: Level: Begane grond; Base Extension Distance: 0 mm; Base is Attached: no; Base Offset: 0 mm; Top Constraint: Level: Lengte; Top Extension Distance: 0 mm; Top is Attached: no; Top Offset: 0 mm; Unconnected Height: 2500 mm
Other - Family: Basic Wall: NLRS_21_WA_Naturoll 035_220x580x3400mm; Family and Type: Basic Wall: NLRS_21_WA_Naturoll 035_220x580x3400mm; Type: Basic Wall: NLRS_21_WA_Naturoll 035_220x580x3400mm; Type Id: Basic Wall: NLRS_21_WA_Naturoll 035_220x580x3400mm
Phasing - Phase Created: New Construction
Structural - Enable Analytical Model: no; Structural: no; Structural Usage: Non-bearing
Pset_WallCommon - LoadBearing: no; IsExternal: yes; ExtendToStructure: no
Name (Basic Wall:NLRS_21_WA_Naturoll 035_220x580x3400mm:...) | BaseQuantities, Length (mm) = Dimensions, Length (mm) | GrossFootprintArea (m2) | NetVolume (m3) | NetSideArea (m2) | Location Line | Area (m2) | Volume (m3)
35438 | 2000 | 0.44 | 1100000000 | 5000000 | Core Face: Interior | 5 | 1.1
35440 | 1000 | 0.22 | 550000000 | 2500000 | Wall Centerline | 2.5 | 0.55

# IfcWallStandardCase: Basic Wall:NLRS_21_WA_Naturoll 035_235x580x3100mm (2)
In: Begane grond
Type - PredefinedType: STANDARD; Material: Knauf Insulation_Ecose® glaswol_naturoll 035 235 mm
Type - Analytical Properties - Roughness: 1; Thermal mass: 0; Absorptance: 0.1; Heat Transfer Coefficient (U): 0.148936; Thermal Resistance (R): 6.71429
Type - Construction - Function: Exterior; Wrapping at Inserts: Do not wrap; Width: 235 mm
Type - Graphics - Coarse Scale Fill Color: 0
Type - Identity Data - Type Image: Raster image: Naturoll 035 .jpg (2); Assembly Code: 21; Assembly Description: Buitenwanden; Description: Naturoll 035 - 235mm; Manufacturer: Knauf Insulation B.V.; Model: Naturoll 035 is een onbeklede glaswoldeken met ECOSE® Technology; Type Name: NLRS_21_WA_Naturoll 035_235x580x3100mm; URL: www.knaufinsulation.nl
Type - Other - Category: Walls; Family Name: Basic Wall
Type - Pset_ElementShading - Roughness: 304.8 mm
Type - Pset_ManufacturerTypeInformation - Manufacturer: Knauf Insulation B.V.
Type - Pset_ProductRequirements - Category: Walls
Type - Pset_QuantityTakeOff - Reference: NLRS_21_WA_Naturoll 035_235x580x3100mm
Type - Pset_ReinforcementBarPitchOfWall - Description: Naturoll 035 - 235mm; Reference: NLRS_21_WA_Naturoll 035_235x580x3100mm
Type - Pset_WallCommon - IsExternal: no; Reference: NLRS_21_WA_Naturoll 035_235x580x3100mm; ThermalTransmittance: 0.148936 kg/K/s3
Classification: 21 Buitenwanden (Uniformat)
BaseQuantities - Height: 2500 mm; Width: 235 mm
Constraints - Related to Mass: no; Room Bounding: yes; Base Constraint: Level: Begane grond; Base Extension Distance: 0 mm; Base is Attached: no; Base Offset: 0 mm; Top Constraint: Level: Lengte; Top Extension Distance: 0 mm; Top is Attached: no; Top Offset: 0 mm; Unconnected Height: 2500 mm
Other - Family: Basic Wall: NLRS_21_WA_Naturoll 035_235x580x3100mm; Family and Type: Basic Wall: NLRS_21_WA_Naturoll 035_235x580x3100mm; Type: Basic Wall: NLRS_21_WA_Naturoll 035_235x580x3100mm; Type Id: Basic Wall: NLRS_21_WA_Naturoll 035_235x580x3100mm
Phasing - Phase Created: New Construction
Structural - Enable Analytical Model: no; Structural: no; Structural Usage: Non-bearing
Pset_WallCommon - LoadBearing: no; IsExternal: yes; ExtendToStructure: no
Name (Basic Wall:NLRS_21_WA_Naturoll 035_235x580x3100mm:...) | BaseQuantities, Length (mm) = Dimensions, Length (mm) | GrossFootprintArea (m2) | NetVolume (m3) | NetSideArea (m2) | Location Line | Area (m2) | Volume (m3)
35457 | 2000 | 0.47 | 1175000000 | 5000000 | Core Face: Interior | 5 | 1.175
35459 | 1000 | 0.235 | 587500000 | 2500000 | Wall Centerline | 2.5 | 0.5875

# IfcWallStandardCase: Basic Wall:NLRS_21_WA_Naturoll 035_240x580x3100mm (2)
In: Begane grond
Type - PredefinedType: STANDARD; Material: Knauf Insulation_Ecose® glaswol_naturoll 035 240 mm
Type - Analytical Properties - Roughness: 1; Thermal mass: 0; Absorptance: 0.1; Heat Transfer Coefficient (U): 0.145833; Thermal Resistance (R): 6.85714
Type - Construction - Function: Exterior; Wrapping at Inserts: Do not wrap; Width: 240 mm
Type - Graphics - Coarse Scale Fill Color: 0
Type - Identity Data - Type Image: Raster image: Naturoll 035 .jpg (2); Assembly Code: 21; Assembly Description: Buitenwanden; Description: Naturoll 035 - 240mm; Manufacturer: Knauf Insulation B.V.; Model: Naturoll 035 is een onbeklede glaswoldeken met ECOSE® Technology; Type Name: NLRS_21_WA_Naturoll 035_240x580x3100mm; URL: www.knaufinsulation.nl
Type - Other - Category: Walls; Family Name: Basic Wall
Type - Pset_ElementShading - Roughness: 304.8 mm
Type - Pset_ManufacturerTypeInformation - Manufacturer: Knauf Insulation B.V.
Type - Pset_ProductRequirements - Category: Walls
Type - Pset_QuantityTakeOff - Reference: NLRS_21_WA_Naturoll 035_240x580x3100mm
Type - Pset_ReinforcementBarPitchOfWall - Description: Naturoll 035 - 240mm; Reference: NLRS_21_WA_Naturoll 035_240x580x3100mm
Type - Pset_WallCommon - IsExternal: no; Reference: NLRS_21_WA_Naturoll 035_240x580x3100mm; ThermalTransmittance: 0.145833 kg/K/s3
Classification: 21 Buitenwanden (Uniformat)
BaseQuantities - Height: 2500 mm; Width: 240 mm
Constraints - Related to Mass: no; Room Bounding: yes; Base Constraint: Level: Begane grond; Base Extension Distance: 0 mm; Base is Attached: no; Base Offset: 0 mm; Top Constraint: Level: Lengte; Top Extension Distance: 0 mm; Top is Attached: no; Top Offset: 0 mm; Unconnected Height: 2500 mm
Other - Family: Basic Wall: NLRS_21_WA_Naturoll 035_240x580x3100mm; Family and Type: Basic Wall: NLRS_21_WA_Naturoll 035_240x580x3100mm; Type: Basic Wall: NLRS_21_WA_Naturoll 035_240x580x3100mm; Type Id: Basic Wall: NLRS_21_WA_Naturoll 035_240x580x3100mm
Phasing - Phase Created: New Construction
Structural - Enable Analytical Model: no; Structural: no; Structural Usage: Non-bearing
Pset_WallCommon - LoadBearing: no; IsExternal: yes; ExtendToStructure: no
Name (Basic Wall:NLRS_21_WA_Naturoll 035_240x580x3100mm:...) | BaseQuantities, Length (mm) = Dimensions, Length (mm) | GrossFootprintArea (m2) | NetVolume (m3) | NetSideArea (m2) | Location Line | Area (m2) | Volume (m3)
35476 | 2000 | 0.48 | 1200000000 | 5000000 | Core Face: Interior | 5 | 1.2
35478 | 1000 | 0.24 | 600000000 | 2500000 | Wall Centerline | 2.5 | 0.6

# IfcWallStandardCase: Basic Wall:NLRS_21_WA_Naturoll 035_270x590x2600mm (2)
In: Begane grond
Type - PredefinedType: STANDARD; Material: Knauf Insulation_Ecose® glaswol_naturoll 035 240 mm
Type - Analytical Properties - Roughness: 1; Thermal mass: 0; Absorptance: 0.1; Heat Transfer Coefficient (U): 0.145833; Thermal Resistance (R): 6.85714
Type - Construction - Function: Exterior; Wrapping at Inserts: Do not wrap; Width: 240 mm
Type - Graphics - Coarse Scale Fill Color: 0
Type - Identity Data - Type Image: Raster image: Naturoll 035 .jpg (2); Assembly Code: 21; Assembly Description: Buitenwanden; Description: Naturoll 035 - 270mm; Manufacturer: Knauf Insulation B.V.; Model: Naturoll 035 is een onbeklede glaswoldeken met ECOSE® Technology; Type Name: NLRS_21_WA_Naturoll 035_270x590x2600mm; URL: www.knaufinsulation.nl
Type - Other - Category: Walls; Family Name: Basic Wall
Type - Pset_ElementShading - Roughness: 304.8 mm
Type - Pset_ManufacturerTypeInformation - Manufacturer: Knauf Insulation B.V.
Type - Pset_ProductRequirements - Category: Walls
Type - Pset_QuantityTakeOff - Reference: NLRS_21_WA_Naturoll 035_270x590x2600mm
Type - Pset_ReinforcementBarPitchOfWall - Description: Naturoll 035 - 270mm; Reference: NLRS_21_WA_Naturoll 035_270x590x2600mm
Type - Pset_WallCommon - IsExternal: no; Reference: NLRS_21_WA_Naturoll 035_270x590x2600mm; ThermalTransmittance: 0.145833 kg/K/s3
Classification: 21 Buitenwanden (Uniformat)
BaseQuantities - Height: 2500 mm; Width: 240 mm
Constraints - Related to Mass: no; Room Bounding: yes; Base Constraint: Level: Begane grond; Base Extension Distance: 0 mm; Base is Attached: no; Base Offset: 0 mm; Top Constraint: Level: Lengte; Top Extension Distance: 0 mm; Top is Attached: no; Top Offset: 0 mm; Unconnected Height: 2500 mm
Other - Family: Basic Wall: NLRS_21_WA_Naturoll 035_270x590x2600mm; Family and Type: Basic Wall: NLRS_21_WA_Naturoll 035_270x590x2600mm; Type: Basic Wall: NLRS_21_WA_Naturoll 035_270x590x2600mm; Type Id: Basic Wall: NLRS_21_WA_Naturoll 035_270x590x2600mm
Phasing - Phase Created: New Construction
Structural - Enable Analytical Model: no; Structural: no; Structural Usage: Non-bearing
Pset_WallCommon - LoadBearing: no; IsExternal: yes; ExtendToStructure: no
Name (Basic Wall:NLRS_21_WA_Naturoll 035_270x590x2600mm:...) | BaseQuantities, Length (mm) = Dimensions, Length (mm) | GrossFootprintArea (m2) | NetVolume (m3) | NetSideArea (m2) | Location Line | Area (m2) | Volume (m3)
35495 | 2000 | 0.48 | 1200000000 | 5000000 | Core Face: Interior | 5 | 1.2
35497 | 1000 | 0.24 | 600000000 | 2500000 | Wall Centerline | 2.5 | 0.6

# IfcWallStandardCase: Basic Wall:NLRS_21_WA_Naturoll 035_90x380x7600mm (2)
In: Begane grond
Type - PredefinedType: STANDARD; Material: Knauf Insulation_Ecose® glaswol_naturoll 035 90 mm
Type - Analytical Properties - Roughness: 1; Thermal mass: 0; Absorptance: 0.1; Heat Transfer Coefficient (U): 0.388889; Thermal Resistance (R): 2.57143
Type - Construction - Function: Exterior; Width: 90 mm; Wrapping at Inserts: Do not wrap
Type - Graphics - Coarse Scale Fill Color: 0
Type - Identity Data - Type Image: Raster image: Naturoll 035 .jpg (2); Assembly Code: 21; Assembly Description: Buitenwanden; Description: Naturoll 035 - 90mm; Manufacturer: Knauf Insulation B.V.; Model: Naturoll 035 is een onbeklede glaswoldeken met ECOSE® Technology; Type Name: NLRS_21_WA_Naturoll 035_90x380x7600mm; URL: www.knaufinsulation.nl
Type - Other - Category: Walls; Family Name: Basic Wall
Type - Pset_ElementShading - Roughness: 304.8 mm
Type - Pset_ManufacturerTypeInformation - Manufacturer: Knauf Insulation B.V.
Type - Pset_ProductRequirements - Category: Walls
Type - Pset_QuantityTakeOff - Reference: NLRS_21_WA_Naturoll 035_90x380x7600mm
Type - Pset_ReinforcementBarPitchOfWall - Description: Naturoll 035 - 90mm; Reference: NLRS_21_WA_Naturoll 035_90x380x7600mm
Type - Pset_WallCommon - IsExternal: no; Reference: NLRS_21_WA_Naturoll 035_90x380x7600mm; ThermalTransmittance: 0.388889 kg/K/s3
Classification: 21 Buitenwanden (Uniformat)
BaseQuantities - Height: 2500 mm; Width: 90 mm
Constraints - Related to Mass: no; Room Bounding: yes; Base Constraint: Level: Begane grond; Base Extension Distance: 0 mm; Base is Attached: no; Base Offset: 0 mm; Top Constraint: Level: Lengte; Top Extension Distance: 0 mm; Top is Attached: no; Top Offset: 0 mm; Unconnected Height: 2500 mm
Other - Family: Basic Wall: NLRS_21_WA_Naturoll 035_90x380x7600mm; Family and Type: Basic Wall: NLRS_21_WA_Naturoll 035_90x380x7600mm; Type: Basic Wall: NLRS_21_WA_Naturoll 035_90x380x7600mm; Type Id: Basic Wall: NLRS_21_WA_Naturoll 035_90x380x7600mm
Phasing - Phase Created: New Construction
Structural - Enable Analytical Model: no; Structural: no; Structural Usage: Non-bearing
Pset_WallCommon - LoadBearing: no; IsExternal: yes; ExtendToStructure: no
Name (Basic Wall:NLRS_21_WA_Naturoll 035_90x380x7600mm:...) | BaseQuantities, Length (mm) = Dimensions, Length (mm) | GrossFootprintArea (m2) | NetVolume (m3) | NetSideArea (m2) | Location Line | Area (m2) | Volume (m3)
34411 | 2000 | 0.18 | 450000000 | 5000000 | Core Face: Interior | 5 | 0.45
34652 | 1000 | 0.09 | 225000000 | 2500000 | Wall Centerline | 2.5 | 0.225

# IfcWallStandardCase: Basic Wall:NLRS_21_WA_Naturoll 035_90x580x7600mm (2)
In: Begane grond
Type - PredefinedType: STANDARD; Material: Knauf Insulation_Ecose® glaswol_naturoll 035 90 mm
Type - Analytical Properties - Roughness: 1; Thermal mass: 0; Absorptance: 0.1; Heat Transfer Coefficient (U): 0.388889; Thermal Resistance (R): 2.57143
Type - Construction - Function: Exterior; Wrapping at Inserts: Do not wrap; Width: 90 mm
Type - Graphics - Coarse Scale Fill Color: 0
Type - Identity Data - Type Image: Raster image: Naturoll 035 .jpg (2); Assembly Code: 21; Assembly Description: Buitenwanden; Description: Naturoll 035 - 90mm; Manufacturer: Knauf Insulation B.V.; Model: Naturoll 035 is een onbeklede glaswoldeken met ECOSE® Technology; Type Name: NLRS_21_WA_Naturoll 035_90x580x7600mm; URL: www.knaufinsulation.nl
Type - Other - Category: Walls; Family Name: Basic Wall
Type - Pset_ElementShading - Roughness: 304.8 mm
Type - Pset_ManufacturerTypeInformation - Manufacturer: Knauf Insulation B.V.
Type - Pset_ProductRequirements - Category: Walls
Type - Pset_QuantityTakeOff - Reference: NLRS_21_WA_Naturoll 035_90x580x7600mm
Type - Pset_ReinforcementBarPitchOfWall - Description: Naturoll 035 - 90mm; Reference: NLRS_21_WA_Naturoll 035_90x580x7600mm
Type - Pset_WallCommon - IsExternal: no; Reference: NLRS_21_WA_Naturoll 035_90x580x7600mm; ThermalTransmittance: 0.388889 kg/K/s3
Classification: 21 Buitenwanden (Uniformat)
BaseQuantities - Height: 2500 mm; Width: 90 mm
Constraints - Related to Mass: no; Room Bounding: yes; Base Constraint: Level: Begane grond; Base Extension Distance: 0 mm; Base is Attached: no; Base Offset: 0 mm; Top Constraint: Level: Lengte; Top Extension Distance: 0 mm; Top is Attached: no; Top Offset: 0 mm; Unconnected Height: 2500 mm
Other - Family: Basic Wall: NLRS_21_WA_Naturoll 035_90x580x7600mm; Family and Type: Basic Wall: NLRS_21_WA_Naturoll 035_90x580x7600mm; Type: Basic Wall: NLRS_21_WA_Naturoll 035_90x580x7600mm; Type Id: Basic Wall: NLRS_21_WA_Naturoll 035_90x580x7600mm
Phasing - Phase Created: New Construction
Structural - Enable Analytical Model: no; Structural: no; Structural Usage: Non-bearing
Pset_WallCommon - LoadBearing: no; IsExternal: yes; ExtendToStructure: no
Name (Basic Wall:NLRS_21_WA_Naturoll 035_90x580x7600mm:...) | BaseQuantities, Length (mm) = Dimensions, Length (mm) | GrossFootprintArea (m2) | NetVolume (m3) | NetSideArea (m2) | Location Line | Area (m2) | Volume (m3)
34916 | 2000 | 0.18 | 450000000 | 5000000 | Core Face: Interior | 5 | 0.45
34918 | 1000 | 0.09 | 225000000 | 2500000 | Wall Centerline | 2.5 | 0.225
